VERSION 5.8 ;
BUSBITCHARS "[]" ;
DIVIDERCHAR "/" ;
UNITS
    DATABASE MICRONS 1000 ;
END UNITS

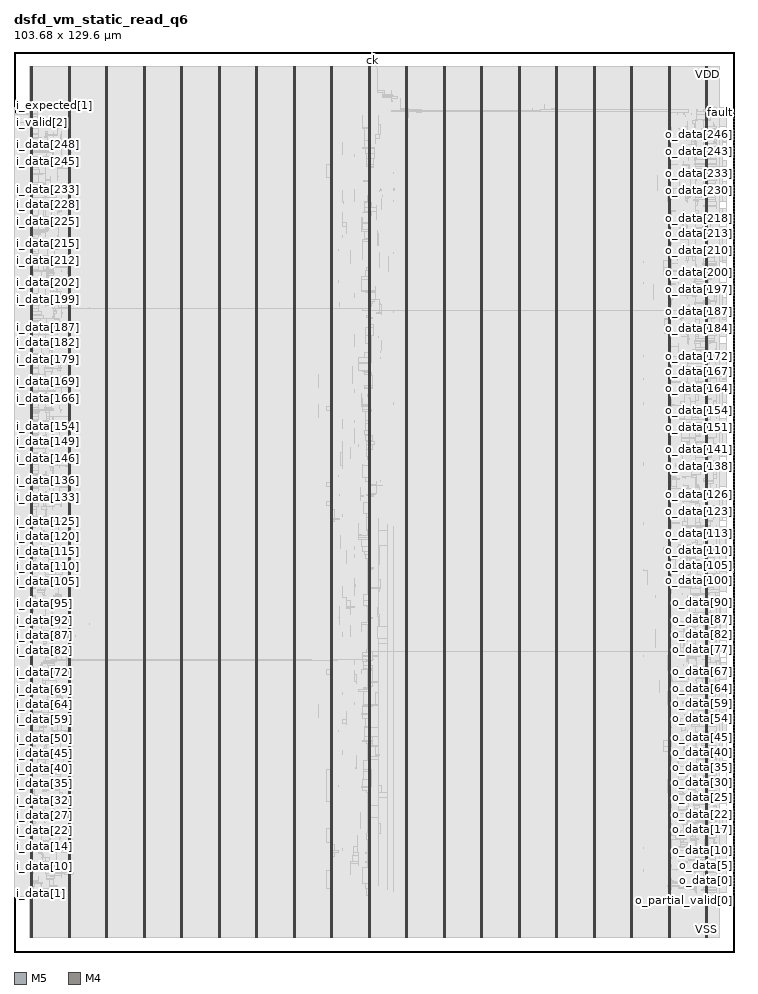
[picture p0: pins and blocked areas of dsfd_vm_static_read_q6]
MACRO dsfd_vm_static_read_q6
  FOREIGN dsfd_vm_static_read_q6 0 0 ;
  CLASS BLOCK ;
  SIZE 103.68 BY 129.6 ;
  PIN ck
    DIRECTION INPUT ;
    USE SIGNAL ;
    PORT
      LAYER M5 ;
        RECT  51.6 129.516 51.624 129.6 ;
    END
  END ck
  PIN fault
    DIRECTION OUTPUT ;
    USE SIGNAL ;
    PORT
      LAYER M4 ;
        RECT  103.596 120.912 103.68 120.936 ;
    END
  END fault
  PIN i_data[0]
    DIRECTION INPUT ;
    USE SIGNAL ;
    PORT
      LAYER M4 ;
        RECT  0 7.968 0.084 7.992 ;
    END
  END i_data[0]
  PIN i_data[100]
    DIRECTION INPUT ;
    USE SIGNAL ;
    PORT
      LAYER M4 ;
        RECT  0 51.168 0.084 51.192 ;
    END
  END i_data[100]
  PIN i_data[101]
    DIRECTION INPUT ;
    USE SIGNAL ;
    PORT
      LAYER M4 ;
        RECT  0 51.6 0.084 51.624 ;
    END
  END i_data[101]
  PIN i_data[102]
    DIRECTION INPUT ;
    USE SIGNAL ;
    PORT
      LAYER M4 ;
        RECT  0 52.032 0.084 52.056 ;
    END
  END i_data[102]
  PIN i_data[103]
    DIRECTION INPUT ;
    USE SIGNAL ;
    PORT
      LAYER M4 ;
        RECT  0 52.464 0.084 52.488 ;
    END
  END i_data[103]
  PIN i_data[104]
    DIRECTION INPUT ;
    USE SIGNAL ;
    PORT
      LAYER M4 ;
        RECT  0 52.896 0.084 52.92 ;
    END
  END i_data[104]
  PIN i_data[105]
    DIRECTION INPUT ;
    USE SIGNAL ;
    PORT
      LAYER M4 ;
        RECT  0 53.328 0.084 53.352 ;
    END
  END i_data[105]
  PIN i_data[106]
    DIRECTION INPUT ;
    USE SIGNAL ;
    PORT
      LAYER M4 ;
        RECT  0 53.76 0.084 53.784 ;
    END
  END i_data[106]
  PIN i_data[107]
    DIRECTION INPUT ;
    USE SIGNAL ;
    PORT
      LAYER M4 ;
        RECT  0 54.192 0.084 54.216 ;
    END
  END i_data[107]
  PIN i_data[108]
    DIRECTION INPUT ;
    USE SIGNAL ;
    PORT
      LAYER M4 ;
        RECT  0 54.624 0.084 54.648 ;
    END
  END i_data[108]
  PIN i_data[109]
    DIRECTION INPUT ;
    USE SIGNAL ;
    PORT
      LAYER M4 ;
        RECT  0 55.056 0.084 55.08 ;
    END
  END i_data[109]
  PIN i_data[10]
    DIRECTION INPUT ;
    USE SIGNAL ;
    PORT
      LAYER M4 ;
        RECT  0 12.288 0.084 12.312 ;
    END
  END i_data[10]
  PIN i_data[110]
    DIRECTION INPUT ;
    USE SIGNAL ;
    PORT
      LAYER M4 ;
        RECT  0 55.488 0.084 55.512 ;
    END
  END i_data[110]
  PIN i_data[111]
    DIRECTION INPUT ;
    USE SIGNAL ;
    PORT
      LAYER M4 ;
        RECT  0 55.92 0.084 55.944 ;
    END
  END i_data[111]
  PIN i_data[112]
    DIRECTION INPUT ;
    USE SIGNAL ;
    PORT
      LAYER M4 ;
        RECT  0 56.352 0.084 56.376 ;
    END
  END i_data[112]
  PIN i_data[113]
    DIRECTION INPUT ;
    USE SIGNAL ;
    PORT
      LAYER M4 ;
        RECT  0 56.784 0.084 56.808 ;
    END
  END i_data[113]
  PIN i_data[114]
    DIRECTION INPUT ;
    USE SIGNAL ;
    PORT
      LAYER M4 ;
        RECT  0 57.216 0.084 57.24 ;
    END
  END i_data[114]
  PIN i_data[115]
    DIRECTION INPUT ;
    USE SIGNAL ;
    PORT
      LAYER M4 ;
        RECT  0 57.648 0.084 57.672 ;
    END
  END i_data[115]
  PIN i_data[116]
    DIRECTION INPUT ;
    USE SIGNAL ;
    PORT
      LAYER M4 ;
        RECT  0 58.08 0.084 58.104 ;
    END
  END i_data[116]
  PIN i_data[117]
    DIRECTION INPUT ;
    USE SIGNAL ;
    PORT
      LAYER M4 ;
        RECT  0 58.512 0.084 58.536 ;
    END
  END i_data[117]
  PIN i_data[118]
    DIRECTION INPUT ;
    USE SIGNAL ;
    PORT
      LAYER M4 ;
        RECT  0 58.944 0.084 58.968 ;
    END
  END i_data[118]
  PIN i_data[119]
    DIRECTION INPUT ;
    USE SIGNAL ;
    PORT
      LAYER M4 ;
        RECT  0 59.376 0.084 59.4 ;
    END
  END i_data[119]
  PIN i_data[11]
    DIRECTION INPUT ;
    USE SIGNAL ;
    PORT
      LAYER M4 ;
        RECT  0 12.72 0.084 12.744 ;
    END
  END i_data[11]
  PIN i_data[120]
    DIRECTION INPUT ;
    USE SIGNAL ;
    PORT
      LAYER M4 ;
        RECT  0 59.808 0.084 59.832 ;
    END
  END i_data[120]
  PIN i_data[121]
    DIRECTION INPUT ;
    USE SIGNAL ;
    PORT
      LAYER M4 ;
        RECT  0 60.24 0.084 60.264 ;
    END
  END i_data[121]
  PIN i_data[122]
    DIRECTION INPUT ;
    USE SIGNAL ;
    PORT
      LAYER M4 ;
        RECT  0 60.672 0.084 60.696 ;
    END
  END i_data[122]
  PIN i_data[123]
    DIRECTION INPUT ;
    USE SIGNAL ;
    PORT
      LAYER M4 ;
        RECT  0 61.104 0.084 61.128 ;
    END
  END i_data[123]
  PIN i_data[124]
    DIRECTION INPUT ;
    USE SIGNAL ;
    PORT
      LAYER M4 ;
        RECT  0 61.536 0.084 61.56 ;
    END
  END i_data[124]
  PIN i_data[125]
    DIRECTION INPUT ;
    USE SIGNAL ;
    PORT
      LAYER M4 ;
        RECT  0 61.968 0.084 61.992 ;
    END
  END i_data[125]
  PIN i_data[126]
    DIRECTION INPUT ;
    USE SIGNAL ;
    PORT
      LAYER M4 ;
        RECT  0 62.4 0.084 62.424 ;
    END
  END i_data[126]
  PIN i_data[127]
    DIRECTION INPUT ;
    USE SIGNAL ;
    PORT
      LAYER M4 ;
        RECT  0 62.832 0.084 62.856 ;
    END
  END i_data[127]
  PIN i_data[128]
    DIRECTION INPUT ;
    USE SIGNAL ;
    PORT
      LAYER M4 ;
        RECT  0 63.264 0.084 63.288 ;
    END
  END i_data[128]
  PIN i_data[129]
    DIRECTION INPUT ;
    USE SIGNAL ;
    PORT
      LAYER M4 ;
        RECT  0 63.696 0.084 63.72 ;
    END
  END i_data[129]
  PIN i_data[12]
    DIRECTION INPUT ;
    USE SIGNAL ;
    PORT
      LAYER M4 ;
        RECT  0 13.152 0.084 13.176 ;
    END
  END i_data[12]
  PIN i_data[130]
    DIRECTION INPUT ;
    USE SIGNAL ;
    PORT
      LAYER M4 ;
        RECT  0 64.128 0.084 64.152 ;
    END
  END i_data[130]
  PIN i_data[131]
    DIRECTION INPUT ;
    USE SIGNAL ;
    PORT
      LAYER M4 ;
        RECT  0 64.56 0.084 64.584 ;
    END
  END i_data[131]
  PIN i_data[132]
    DIRECTION INPUT ;
    USE SIGNAL ;
    PORT
      LAYER M4 ;
        RECT  0 64.992 0.084 65.016 ;
    END
  END i_data[132]
  PIN i_data[133]
    DIRECTION INPUT ;
    USE SIGNAL ;
    PORT
      LAYER M4 ;
        RECT  0 65.424 0.084 65.448 ;
    END
  END i_data[133]
  PIN i_data[134]
    DIRECTION INPUT ;
    USE SIGNAL ;
    PORT
      LAYER M4 ;
        RECT  0 65.856 0.084 65.88 ;
    END
  END i_data[134]
  PIN i_data[135]
    DIRECTION INPUT ;
    USE SIGNAL ;
    PORT
      LAYER M4 ;
        RECT  0 66.288 0.084 66.312 ;
    END
  END i_data[135]
  PIN i_data[136]
    DIRECTION INPUT ;
    USE SIGNAL ;
    PORT
      LAYER M4 ;
        RECT  0 66.72 0.084 66.744 ;
    END
  END i_data[136]
  PIN i_data[137]
    DIRECTION INPUT ;
    USE SIGNAL ;
    PORT
      LAYER M4 ;
        RECT  0 67.152 0.084 67.176 ;
    END
  END i_data[137]
  PIN i_data[138]
    DIRECTION INPUT ;
    USE SIGNAL ;
    PORT
      LAYER M4 ;
        RECT  0 67.584 0.084 67.608 ;
    END
  END i_data[138]
  PIN i_data[139]
    DIRECTION INPUT ;
    USE SIGNAL ;
    PORT
      LAYER M4 ;
        RECT  0 68.016 0.084 68.04 ;
    END
  END i_data[139]
  PIN i_data[13]
    DIRECTION INPUT ;
    USE SIGNAL ;
    PORT
      LAYER M4 ;
        RECT  0 13.584 0.084 13.608 ;
    END
  END i_data[13]
  PIN i_data[140]
    DIRECTION INPUT ;
    USE SIGNAL ;
    PORT
      LAYER M4 ;
        RECT  0 68.448 0.084 68.472 ;
    END
  END i_data[140]
  PIN i_data[141]
    DIRECTION INPUT ;
    USE SIGNAL ;
    PORT
      LAYER M4 ;
        RECT  0 68.88 0.084 68.904 ;
    END
  END i_data[141]
  PIN i_data[142]
    DIRECTION INPUT ;
    USE SIGNAL ;
    PORT
      LAYER M4 ;
        RECT  0 69.312 0.084 69.336 ;
    END
  END i_data[142]
  PIN i_data[143]
    DIRECTION INPUT ;
    USE SIGNAL ;
    PORT
      LAYER M4 ;
        RECT  0 69.744 0.084 69.768 ;
    END
  END i_data[143]
  PIN i_data[144]
    DIRECTION INPUT ;
    USE SIGNAL ;
    PORT
      LAYER M4 ;
        RECT  0 70.176 0.084 70.2 ;
    END
  END i_data[144]
  PIN i_data[145]
    DIRECTION INPUT ;
    USE SIGNAL ;
    PORT
      LAYER M4 ;
        RECT  0 70.608 0.084 70.632 ;
    END
  END i_data[145]
  PIN i_data[146]
    DIRECTION INPUT ;
    USE SIGNAL ;
    PORT
      LAYER M4 ;
        RECT  0 71.04 0.084 71.064 ;
    END
  END i_data[146]
  PIN i_data[147]
    DIRECTION INPUT ;
    USE SIGNAL ;
    PORT
      LAYER M4 ;
        RECT  0 71.472 0.084 71.496 ;
    END
  END i_data[147]
  PIN i_data[148]
    DIRECTION INPUT ;
    USE SIGNAL ;
    PORT
      LAYER M4 ;
        RECT  0 71.904 0.084 71.928 ;
    END
  END i_data[148]
  PIN i_data[149]
    DIRECTION INPUT ;
    USE SIGNAL ;
    PORT
      LAYER M4 ;
        RECT  0 72.336 0.084 72.36 ;
    END
  END i_data[149]
  PIN i_data[14]
    DIRECTION INPUT ;
    USE SIGNAL ;
    PORT
      LAYER M4 ;
        RECT  0 14.016 0.084 14.04 ;
    END
  END i_data[14]
  PIN i_data[150]
    DIRECTION INPUT ;
    USE SIGNAL ;
    PORT
      LAYER M4 ;
        RECT  0 72.768 0.084 72.792 ;
    END
  END i_data[150]
  PIN i_data[151]
    DIRECTION INPUT ;
    USE SIGNAL ;
    PORT
      LAYER M4 ;
        RECT  0 73.2 0.084 73.224 ;
    END
  END i_data[151]
  PIN i_data[152]
    DIRECTION INPUT ;
    USE SIGNAL ;
    PORT
      LAYER M4 ;
        RECT  0 73.632 0.084 73.656 ;
    END
  END i_data[152]
  PIN i_data[153]
    DIRECTION INPUT ;
    USE SIGNAL ;
    PORT
      LAYER M4 ;
        RECT  0 74.064 0.084 74.088 ;
    END
  END i_data[153]
  PIN i_data[154]
    DIRECTION INPUT ;
    USE SIGNAL ;
    PORT
      LAYER M4 ;
        RECT  0 74.496 0.084 74.52 ;
    END
  END i_data[154]
  PIN i_data[155]
    DIRECTION INPUT ;
    USE SIGNAL ;
    PORT
      LAYER M4 ;
        RECT  0 74.928 0.084 74.952 ;
    END
  END i_data[155]
  PIN i_data[156]
    DIRECTION INPUT ;
    USE SIGNAL ;
    PORT
      LAYER M4 ;
        RECT  0 75.36 0.084 75.384 ;
    END
  END i_data[156]
  PIN i_data[157]
    DIRECTION INPUT ;
    USE SIGNAL ;
    PORT
      LAYER M4 ;
        RECT  0 75.792 0.084 75.816 ;
    END
  END i_data[157]
  PIN i_data[158]
    DIRECTION INPUT ;
    USE SIGNAL ;
    PORT
      LAYER M4 ;
        RECT  0 76.224 0.084 76.248 ;
    END
  END i_data[158]
  PIN i_data[159]
    DIRECTION INPUT ;
    USE SIGNAL ;
    PORT
      LAYER M4 ;
        RECT  0 76.656 0.084 76.68 ;
    END
  END i_data[159]
  PIN i_data[15]
    DIRECTION INPUT ;
    USE SIGNAL ;
    PORT
      LAYER M4 ;
        RECT  0 14.448 0.084 14.472 ;
    END
  END i_data[15]
  PIN i_data[160]
    DIRECTION INPUT ;
    USE SIGNAL ;
    PORT
      LAYER M4 ;
        RECT  0 77.088 0.084 77.112 ;
    END
  END i_data[160]
  PIN i_data[161]
    DIRECTION INPUT ;
    USE SIGNAL ;
    PORT
      LAYER M4 ;
        RECT  0 77.52 0.084 77.544 ;
    END
  END i_data[161]
  PIN i_data[162]
    DIRECTION INPUT ;
    USE SIGNAL ;
    PORT
      LAYER M4 ;
        RECT  0 77.952 0.084 77.976 ;
    END
  END i_data[162]
  PIN i_data[163]
    DIRECTION INPUT ;
    USE SIGNAL ;
    PORT
      LAYER M4 ;
        RECT  0 78.384 0.084 78.408 ;
    END
  END i_data[163]
  PIN i_data[164]
    DIRECTION INPUT ;
    USE SIGNAL ;
    PORT
      LAYER M4 ;
        RECT  0 78.816 0.084 78.84 ;
    END
  END i_data[164]
  PIN i_data[165]
    DIRECTION INPUT ;
    USE SIGNAL ;
    PORT
      LAYER M4 ;
        RECT  0 79.248 0.084 79.272 ;
    END
  END i_data[165]
  PIN i_data[166]
    DIRECTION INPUT ;
    USE SIGNAL ;
    PORT
      LAYER M4 ;
        RECT  0 79.68 0.084 79.704 ;
    END
  END i_data[166]
  PIN i_data[167]
    DIRECTION INPUT ;
    USE SIGNAL ;
    PORT
      LAYER M4 ;
        RECT  0 80.112 0.084 80.136 ;
    END
  END i_data[167]
  PIN i_data[168]
    DIRECTION INPUT ;
    USE SIGNAL ;
    PORT
      LAYER M4 ;
        RECT  0 80.544 0.084 80.568 ;
    END
  END i_data[168]
  PIN i_data[169]
    DIRECTION INPUT ;
    USE SIGNAL ;
    PORT
      LAYER M4 ;
        RECT  0 80.976 0.084 81 ;
    END
  END i_data[169]
  PIN i_data[16]
    DIRECTION INPUT ;
    USE SIGNAL ;
    PORT
      LAYER M4 ;
        RECT  0 14.88 0.084 14.904 ;
    END
  END i_data[16]
  PIN i_data[170]
    DIRECTION INPUT ;
    USE SIGNAL ;
    PORT
      LAYER M4 ;
        RECT  0 81.408 0.084 81.432 ;
    END
  END i_data[170]
  PIN i_data[171]
    DIRECTION INPUT ;
    USE SIGNAL ;
    PORT
      LAYER M4 ;
        RECT  0 81.84 0.084 81.864 ;
    END
  END i_data[171]
  PIN i_data[172]
    DIRECTION INPUT ;
    USE SIGNAL ;
    PORT
      LAYER M4 ;
        RECT  0 82.272 0.084 82.296 ;
    END
  END i_data[172]
  PIN i_data[173]
    DIRECTION INPUT ;
    USE SIGNAL ;
    PORT
      LAYER M4 ;
        RECT  0 82.704 0.084 82.728 ;
    END
  END i_data[173]
  PIN i_data[174]
    DIRECTION INPUT ;
    USE SIGNAL ;
    PORT
      LAYER M4 ;
        RECT  0 83.136 0.084 83.16 ;
    END
  END i_data[174]
  PIN i_data[175]
    DIRECTION INPUT ;
    USE SIGNAL ;
    PORT
      LAYER M4 ;
        RECT  0 83.568 0.084 83.592 ;
    END
  END i_data[175]
  PIN i_data[176]
    DIRECTION INPUT ;
    USE SIGNAL ;
    PORT
      LAYER M4 ;
        RECT  0 84 0.084 84.024 ;
    END
  END i_data[176]
  PIN i_data[177]
    DIRECTION INPUT ;
    USE SIGNAL ;
    PORT
      LAYER M4 ;
        RECT  0 84.432 0.084 84.456 ;
    END
  END i_data[177]
  PIN i_data[178]
    DIRECTION INPUT ;
    USE SIGNAL ;
    PORT
      LAYER M4 ;
        RECT  0 84.864 0.084 84.888 ;
    END
  END i_data[178]
  PIN i_data[179]
    DIRECTION INPUT ;
    USE SIGNAL ;
    PORT
      LAYER M4 ;
        RECT  0 85.296 0.084 85.32 ;
    END
  END i_data[179]
  PIN i_data[17]
    DIRECTION INPUT ;
    USE SIGNAL ;
    PORT
      LAYER M4 ;
        RECT  0 15.312 0.084 15.336 ;
    END
  END i_data[17]
  PIN i_data[180]
    DIRECTION INPUT ;
    USE SIGNAL ;
    PORT
      LAYER M4 ;
        RECT  0 85.728 0.084 85.752 ;
    END
  END i_data[180]
  PIN i_data[181]
    DIRECTION INPUT ;
    USE SIGNAL ;
    PORT
      LAYER M4 ;
        RECT  0 86.16 0.084 86.184 ;
    END
  END i_data[181]
  PIN i_data[182]
    DIRECTION INPUT ;
    USE SIGNAL ;
    PORT
      LAYER M4 ;
        RECT  0 86.592 0.084 86.616 ;
    END
  END i_data[182]
  PIN i_data[183]
    DIRECTION INPUT ;
    USE SIGNAL ;
    PORT
      LAYER M4 ;
        RECT  0 87.024 0.084 87.048 ;
    END
  END i_data[183]
  PIN i_data[184]
    DIRECTION INPUT ;
    USE SIGNAL ;
    PORT
      LAYER M4 ;
        RECT  0 87.456 0.084 87.48 ;
    END
  END i_data[184]
  PIN i_data[185]
    DIRECTION INPUT ;
    USE SIGNAL ;
    PORT
      LAYER M4 ;
        RECT  0 87.888 0.084 87.912 ;
    END
  END i_data[185]
  PIN i_data[186]
    DIRECTION INPUT ;
    USE SIGNAL ;
    PORT
      LAYER M4 ;
        RECT  0 88.32 0.084 88.344 ;
    END
  END i_data[186]
  PIN i_data[187]
    DIRECTION INPUT ;
    USE SIGNAL ;
    PORT
      LAYER M4 ;
        RECT  0 88.752 0.084 88.776 ;
    END
  END i_data[187]
  PIN i_data[188]
    DIRECTION INPUT ;
    USE SIGNAL ;
    PORT
      LAYER M4 ;
        RECT  0 89.184 0.084 89.208 ;
    END
  END i_data[188]
  PIN i_data[189]
    DIRECTION INPUT ;
    USE SIGNAL ;
    PORT
      LAYER M4 ;
        RECT  0 89.616 0.084 89.64 ;
    END
  END i_data[189]
  PIN i_data[18]
    DIRECTION INPUT ;
    USE SIGNAL ;
    PORT
      LAYER M4 ;
        RECT  0 15.744 0.084 15.768 ;
    END
  END i_data[18]
  PIN i_data[190]
    DIRECTION INPUT ;
    USE SIGNAL ;
    PORT
      LAYER M4 ;
        RECT  0 90.048 0.084 90.072 ;
    END
  END i_data[190]
  PIN i_data[191]
    DIRECTION INPUT ;
    USE SIGNAL ;
    PORT
      LAYER M4 ;
        RECT  0 90.48 0.084 90.504 ;
    END
  END i_data[191]
  PIN i_data[192]
    DIRECTION INPUT ;
    USE SIGNAL ;
    PORT
      LAYER M4 ;
        RECT  0 90.912 0.084 90.936 ;
    END
  END i_data[192]
  PIN i_data[193]
    DIRECTION INPUT ;
    USE SIGNAL ;
    PORT
      LAYER M4 ;
        RECT  0 91.344 0.084 91.368 ;
    END
  END i_data[193]
  PIN i_data[194]
    DIRECTION INPUT ;
    USE SIGNAL ;
    PORT
      LAYER M4 ;
        RECT  0 91.776 0.084 91.8 ;
    END
  END i_data[194]
  PIN i_data[195]
    DIRECTION INPUT ;
    USE SIGNAL ;
    PORT
      LAYER M4 ;
        RECT  0 92.208 0.084 92.232 ;
    END
  END i_data[195]
  PIN i_data[196]
    DIRECTION INPUT ;
    USE SIGNAL ;
    PORT
      LAYER M4 ;
        RECT  0 92.64 0.084 92.664 ;
    END
  END i_data[196]
  PIN i_data[197]
    DIRECTION INPUT ;
    USE SIGNAL ;
    PORT
      LAYER M4 ;
        RECT  0 93.072 0.084 93.096 ;
    END
  END i_data[197]
  PIN i_data[198]
    DIRECTION INPUT ;
    USE SIGNAL ;
    PORT
      LAYER M4 ;
        RECT  0 93.504 0.084 93.528 ;
    END
  END i_data[198]
  PIN i_data[199]
    DIRECTION INPUT ;
    USE SIGNAL ;
    PORT
      LAYER M4 ;
        RECT  0 93.936 0.084 93.96 ;
    END
  END i_data[199]
  PIN i_data[19]
    DIRECTION INPUT ;
    USE SIGNAL ;
    PORT
      LAYER M4 ;
        RECT  0 16.176 0.084 16.2 ;
    END
  END i_data[19]
  PIN i_data[1]
    DIRECTION INPUT ;
    USE SIGNAL ;
    PORT
      LAYER M4 ;
        RECT  0 8.4 0.084 8.424 ;
    END
  END i_data[1]
  PIN i_data[200]
    DIRECTION INPUT ;
    USE SIGNAL ;
    PORT
      LAYER M4 ;
        RECT  0 94.368 0.084 94.392 ;
    END
  END i_data[200]
  PIN i_data[201]
    DIRECTION INPUT ;
    USE SIGNAL ;
    PORT
      LAYER M4 ;
        RECT  0 94.8 0.084 94.824 ;
    END
  END i_data[201]
  PIN i_data[202]
    DIRECTION INPUT ;
    USE SIGNAL ;
    PORT
      LAYER M4 ;
        RECT  0 95.232 0.084 95.256 ;
    END
  END i_data[202]
  PIN i_data[203]
    DIRECTION INPUT ;
    USE SIGNAL ;
    PORT
      LAYER M4 ;
        RECT  0 95.664 0.084 95.688 ;
    END
  END i_data[203]
  PIN i_data[204]
    DIRECTION INPUT ;
    USE SIGNAL ;
    PORT
      LAYER M4 ;
        RECT  0 96.096 0.084 96.12 ;
    END
  END i_data[204]
  PIN i_data[205]
    DIRECTION INPUT ;
    USE SIGNAL ;
    PORT
      LAYER M4 ;
        RECT  0 96.528 0.084 96.552 ;
    END
  END i_data[205]
  PIN i_data[206]
    DIRECTION INPUT ;
    USE SIGNAL ;
    PORT
      LAYER M4 ;
        RECT  0 96.96 0.084 96.984 ;
    END
  END i_data[206]
  PIN i_data[207]
    DIRECTION INPUT ;
    USE SIGNAL ;
    PORT
      LAYER M4 ;
        RECT  0 97.392 0.084 97.416 ;
    END
  END i_data[207]
  PIN i_data[208]
    DIRECTION INPUT ;
    USE SIGNAL ;
    PORT
      LAYER M4 ;
        RECT  0 97.824 0.084 97.848 ;
    END
  END i_data[208]
  PIN i_data[209]
    DIRECTION INPUT ;
    USE SIGNAL ;
    PORT
      LAYER M4 ;
        RECT  0 98.256 0.084 98.28 ;
    END
  END i_data[209]
  PIN i_data[20]
    DIRECTION INPUT ;
    USE SIGNAL ;
    PORT
      LAYER M4 ;
        RECT  0 16.608 0.084 16.632 ;
    END
  END i_data[20]
  PIN i_data[210]
    DIRECTION INPUT ;
    USE SIGNAL ;
    PORT
      LAYER M4 ;
        RECT  0 98.688 0.084 98.712 ;
    END
  END i_data[210]
  PIN i_data[211]
    DIRECTION INPUT ;
    USE SIGNAL ;
    PORT
      LAYER M4 ;
        RECT  0 99.12 0.084 99.144 ;
    END
  END i_data[211]
  PIN i_data[212]
    DIRECTION INPUT ;
    USE SIGNAL ;
    PORT
      LAYER M4 ;
        RECT  0 99.552 0.084 99.576 ;
    END
  END i_data[212]
  PIN i_data[213]
    DIRECTION INPUT ;
    USE SIGNAL ;
    PORT
      LAYER M4 ;
        RECT  0 99.984 0.084 100.008 ;
    END
  END i_data[213]
  PIN i_data[214]
    DIRECTION INPUT ;
    USE SIGNAL ;
    PORT
      LAYER M4 ;
        RECT  0 100.416 0.084 100.44 ;
    END
  END i_data[214]
  PIN i_data[215]
    DIRECTION INPUT ;
    USE SIGNAL ;
    PORT
      LAYER M4 ;
        RECT  0 100.848 0.084 100.872 ;
    END
  END i_data[215]
  PIN i_data[216]
    DIRECTION INPUT ;
    USE SIGNAL ;
    PORT
      LAYER M4 ;
        RECT  0 101.28 0.084 101.304 ;
    END
  END i_data[216]
  PIN i_data[217]
    DIRECTION INPUT ;
    USE SIGNAL ;
    PORT
      LAYER M4 ;
        RECT  0 101.712 0.084 101.736 ;
    END
  END i_data[217]
  PIN i_data[218]
    DIRECTION INPUT ;
    USE SIGNAL ;
    PORT
      LAYER M4 ;
        RECT  0 102.144 0.084 102.168 ;
    END
  END i_data[218]
  PIN i_data[219]
    DIRECTION INPUT ;
    USE SIGNAL ;
    PORT
      LAYER M4 ;
        RECT  0 102.576 0.084 102.6 ;
    END
  END i_data[219]
  PIN i_data[21]
    DIRECTION INPUT ;
    USE SIGNAL ;
    PORT
      LAYER M4 ;
        RECT  0 17.04 0.084 17.064 ;
    END
  END i_data[21]
  PIN i_data[220]
    DIRECTION INPUT ;
    USE SIGNAL ;
    PORT
      LAYER M4 ;
        RECT  0 103.008 0.084 103.032 ;
    END
  END i_data[220]
  PIN i_data[221]
    DIRECTION INPUT ;
    USE SIGNAL ;
    PORT
      LAYER M4 ;
        RECT  0 103.44 0.084 103.464 ;
    END
  END i_data[221]
  PIN i_data[222]
    DIRECTION INPUT ;
    USE SIGNAL ;
    PORT
      LAYER M4 ;
        RECT  0 103.872 0.084 103.896 ;
    END
  END i_data[222]
  PIN i_data[223]
    DIRECTION INPUT ;
    USE SIGNAL ;
    PORT
      LAYER M4 ;
        RECT  0 104.304 0.084 104.328 ;
    END
  END i_data[223]
  PIN i_data[224]
    DIRECTION INPUT ;
    USE SIGNAL ;
    PORT
      LAYER M4 ;
        RECT  0 104.736 0.084 104.76 ;
    END
  END i_data[224]
  PIN i_data[225]
    DIRECTION INPUT ;
    USE SIGNAL ;
    PORT
      LAYER M4 ;
        RECT  0 105.168 0.084 105.192 ;
    END
  END i_data[225]
  PIN i_data[226]
    DIRECTION INPUT ;
    USE SIGNAL ;
    PORT
      LAYER M4 ;
        RECT  0 105.6 0.084 105.624 ;
    END
  END i_data[226]
  PIN i_data[227]
    DIRECTION INPUT ;
    USE SIGNAL ;
    PORT
      LAYER M4 ;
        RECT  0 106.032 0.084 106.056 ;
    END
  END i_data[227]
  PIN i_data[228]
    DIRECTION INPUT ;
    USE SIGNAL ;
    PORT
      LAYER M4 ;
        RECT  0 106.464 0.084 106.488 ;
    END
  END i_data[228]
  PIN i_data[229]
    DIRECTION INPUT ;
    USE SIGNAL ;
    PORT
      LAYER M4 ;
        RECT  0 106.896 0.084 106.92 ;
    END
  END i_data[229]
  PIN i_data[22]
    DIRECTION INPUT ;
    USE SIGNAL ;
    PORT
      LAYER M4 ;
        RECT  0 17.472 0.084 17.496 ;
    END
  END i_data[22]
  PIN i_data[230]
    DIRECTION INPUT ;
    USE SIGNAL ;
    PORT
      LAYER M4 ;
        RECT  0 107.328 0.084 107.352 ;
    END
  END i_data[230]
  PIN i_data[231]
    DIRECTION INPUT ;
    USE SIGNAL ;
    PORT
      LAYER M4 ;
        RECT  0 107.76 0.084 107.784 ;
    END
  END i_data[231]
  PIN i_data[232]
    DIRECTION INPUT ;
    USE SIGNAL ;
    PORT
      LAYER M4 ;
        RECT  0 108.192 0.084 108.216 ;
    END
  END i_data[232]
  PIN i_data[233]
    DIRECTION INPUT ;
    USE SIGNAL ;
    PORT
      LAYER M4 ;
        RECT  0 108.624 0.084 108.648 ;
    END
  END i_data[233]
  PIN i_data[234]
    DIRECTION INPUT ;
    USE SIGNAL ;
    PORT
      LAYER M4 ;
        RECT  0 109.056 0.084 109.08 ;
    END
  END i_data[234]
  PIN i_data[235]
    DIRECTION INPUT ;
    USE SIGNAL ;
    PORT
      LAYER M4 ;
        RECT  0 109.488 0.084 109.512 ;
    END
  END i_data[235]
  PIN i_data[236]
    DIRECTION INPUT ;
    USE SIGNAL ;
    PORT
      LAYER M4 ;
        RECT  0 109.92 0.084 109.944 ;
    END
  END i_data[236]
  PIN i_data[237]
    DIRECTION INPUT ;
    USE SIGNAL ;
    PORT
      LAYER M4 ;
        RECT  0 110.352 0.084 110.376 ;
    END
  END i_data[237]
  PIN i_data[238]
    DIRECTION INPUT ;
    USE SIGNAL ;
    PORT
      LAYER M4 ;
        RECT  0 110.784 0.084 110.808 ;
    END
  END i_data[238]
  PIN i_data[239]
    DIRECTION INPUT ;
    USE SIGNAL ;
    PORT
      LAYER M4 ;
        RECT  0 111.216 0.084 111.24 ;
    END
  END i_data[239]
  PIN i_data[23]
    DIRECTION INPUT ;
    USE SIGNAL ;
    PORT
      LAYER M4 ;
        RECT  0 17.904 0.084 17.928 ;
    END
  END i_data[23]
  PIN i_data[240]
    DIRECTION INPUT ;
    USE SIGNAL ;
    PORT
      LAYER M4 ;
        RECT  0 111.648 0.084 111.672 ;
    END
  END i_data[240]
  PIN i_data[241]
    DIRECTION INPUT ;
    USE SIGNAL ;
    PORT
      LAYER M4 ;
        RECT  0 112.08 0.084 112.104 ;
    END
  END i_data[241]
  PIN i_data[242]
    DIRECTION INPUT ;
    USE SIGNAL ;
    PORT
      LAYER M4 ;
        RECT  0 112.512 0.084 112.536 ;
    END
  END i_data[242]
  PIN i_data[243]
    DIRECTION INPUT ;
    USE SIGNAL ;
    PORT
      LAYER M4 ;
        RECT  0 112.944 0.084 112.968 ;
    END
  END i_data[243]
  PIN i_data[244]
    DIRECTION INPUT ;
    USE SIGNAL ;
    PORT
      LAYER M4 ;
        RECT  0 113.376 0.084 113.4 ;
    END
  END i_data[244]
  PIN i_data[245]
    DIRECTION INPUT ;
    USE SIGNAL ;
    PORT
      LAYER M4 ;
        RECT  0 113.808 0.084 113.832 ;
    END
  END i_data[245]
  PIN i_data[246]
    DIRECTION INPUT ;
    USE SIGNAL ;
    PORT
      LAYER M4 ;
        RECT  0 114.24 0.084 114.264 ;
    END
  END i_data[246]
  PIN i_data[247]
    DIRECTION INPUT ;
    USE SIGNAL ;
    PORT
      LAYER M4 ;
        RECT  0 114.672 0.084 114.696 ;
    END
  END i_data[247]
  PIN i_data[248]
    DIRECTION INPUT ;
    USE SIGNAL ;
    PORT
      LAYER M4 ;
        RECT  0 115.104 0.084 115.128 ;
    END
  END i_data[248]
  PIN i_data[249]
    DIRECTION INPUT ;
    USE SIGNAL ;
    PORT
      LAYER M4 ;
        RECT  0 115.536 0.084 115.56 ;
    END
  END i_data[249]
  PIN i_data[24]
    DIRECTION INPUT ;
    USE SIGNAL ;
    PORT
      LAYER M4 ;
        RECT  0 18.336 0.084 18.36 ;
    END
  END i_data[24]
  PIN i_data[250]
    DIRECTION INPUT ;
    USE SIGNAL ;
    PORT
      LAYER M4 ;
        RECT  0 115.968 0.084 115.992 ;
    END
  END i_data[250]
  PIN i_data[251]
    DIRECTION INPUT ;
    USE SIGNAL ;
    PORT
      LAYER M4 ;
        RECT  0 116.4 0.084 116.424 ;
    END
  END i_data[251]
  PIN i_data[252]
    DIRECTION INPUT ;
    USE SIGNAL ;
    PORT
      LAYER M4 ;
        RECT  0 116.832 0.084 116.856 ;
    END
  END i_data[252]
  PIN i_data[253]
    DIRECTION INPUT ;
    USE SIGNAL ;
    PORT
      LAYER M4 ;
        RECT  0 117.264 0.084 117.288 ;
    END
  END i_data[253]
  PIN i_data[254]
    DIRECTION INPUT ;
    USE SIGNAL ;
    PORT
      LAYER M4 ;
        RECT  0 117.696 0.084 117.72 ;
    END
  END i_data[254]
  PIN i_data[255]
    DIRECTION INPUT ;
    USE SIGNAL ;
    PORT
      LAYER M4 ;
        RECT  0 118.128 0.084 118.152 ;
    END
  END i_data[255]
  PIN i_data[25]
    DIRECTION INPUT ;
    USE SIGNAL ;
    PORT
      LAYER M4 ;
        RECT  0 18.768 0.084 18.792 ;
    END
  END i_data[25]
  PIN i_data[26]
    DIRECTION INPUT ;
    USE SIGNAL ;
    PORT
      LAYER M4 ;
        RECT  0 19.2 0.084 19.224 ;
    END
  END i_data[26]
  PIN i_data[27]
    DIRECTION INPUT ;
    USE SIGNAL ;
    PORT
      LAYER M4 ;
        RECT  0 19.632 0.084 19.656 ;
    END
  END i_data[27]
  PIN i_data[28]
    DIRECTION INPUT ;
    USE SIGNAL ;
    PORT
      LAYER M4 ;
        RECT  0 20.064 0.084 20.088 ;
    END
  END i_data[28]
  PIN i_data[29]
    DIRECTION INPUT ;
    USE SIGNAL ;
    PORT
      LAYER M4 ;
        RECT  0 20.496 0.084 20.52 ;
    END
  END i_data[29]
  PIN i_data[2]
    DIRECTION INPUT ;
    USE SIGNAL ;
    PORT
      LAYER M4 ;
        RECT  0 8.832 0.084 8.856 ;
    END
  END i_data[2]
  PIN i_data[30]
    DIRECTION INPUT ;
    USE SIGNAL ;
    PORT
      LAYER M4 ;
        RECT  0 20.928 0.084 20.952 ;
    END
  END i_data[30]
  PIN i_data[31]
    DIRECTION INPUT ;
    USE SIGNAL ;
    PORT
      LAYER M4 ;
        RECT  0 21.36 0.084 21.384 ;
    END
  END i_data[31]
  PIN i_data[32]
    DIRECTION INPUT ;
    USE SIGNAL ;
    PORT
      LAYER M4 ;
        RECT  0 21.792 0.084 21.816 ;
    END
  END i_data[32]
  PIN i_data[33]
    DIRECTION INPUT ;
    USE SIGNAL ;
    PORT
      LAYER M4 ;
        RECT  0 22.224 0.084 22.248 ;
    END
  END i_data[33]
  PIN i_data[34]
    DIRECTION INPUT ;
    USE SIGNAL ;
    PORT
      LAYER M4 ;
        RECT  0 22.656 0.084 22.68 ;
    END
  END i_data[34]
  PIN i_data[35]
    DIRECTION INPUT ;
    USE SIGNAL ;
    PORT
      LAYER M4 ;
        RECT  0 23.088 0.084 23.112 ;
    END
  END i_data[35]
  PIN i_data[36]
    DIRECTION INPUT ;
    USE SIGNAL ;
    PORT
      LAYER M4 ;
        RECT  0 23.52 0.084 23.544 ;
    END
  END i_data[36]
  PIN i_data[37]
    DIRECTION INPUT ;
    USE SIGNAL ;
    PORT
      LAYER M4 ;
        RECT  0 23.952 0.084 23.976 ;
    END
  END i_data[37]
  PIN i_data[38]
    DIRECTION INPUT ;
    USE SIGNAL ;
    PORT
      LAYER M4 ;
        RECT  0 24.384 0.084 24.408 ;
    END
  END i_data[38]
  PIN i_data[39]
    DIRECTION INPUT ;
    USE SIGNAL ;
    PORT
      LAYER M4 ;
        RECT  0 24.816 0.084 24.84 ;
    END
  END i_data[39]
  PIN i_data[3]
    DIRECTION INPUT ;
    USE SIGNAL ;
    PORT
      LAYER M4 ;
        RECT  0 9.264 0.084 9.288 ;
    END
  END i_data[3]
  PIN i_data[40]
    DIRECTION INPUT ;
    USE SIGNAL ;
    PORT
      LAYER M4 ;
        RECT  0 25.248 0.084 25.272 ;
    END
  END i_data[40]
  PIN i_data[41]
    DIRECTION INPUT ;
    USE SIGNAL ;
    PORT
      LAYER M4 ;
        RECT  0 25.68 0.084 25.704 ;
    END
  END i_data[41]
  PIN i_data[42]
    DIRECTION INPUT ;
    USE SIGNAL ;
    PORT
      LAYER M4 ;
        RECT  0 26.112 0.084 26.136 ;
    END
  END i_data[42]
  PIN i_data[43]
    DIRECTION INPUT ;
    USE SIGNAL ;
    PORT
      LAYER M4 ;
        RECT  0 26.544 0.084 26.568 ;
    END
  END i_data[43]
  PIN i_data[44]
    DIRECTION INPUT ;
    USE SIGNAL ;
    PORT
      LAYER M4 ;
        RECT  0 26.976 0.084 27 ;
    END
  END i_data[44]
  PIN i_data[45]
    DIRECTION INPUT ;
    USE SIGNAL ;
    PORT
      LAYER M4 ;
        RECT  0 27.408 0.084 27.432 ;
    END
  END i_data[45]
  PIN i_data[46]
    DIRECTION INPUT ;
    USE SIGNAL ;
    PORT
      LAYER M4 ;
        RECT  0 27.84 0.084 27.864 ;
    END
  END i_data[46]
  PIN i_data[47]
    DIRECTION INPUT ;
    USE SIGNAL ;
    PORT
      LAYER M4 ;
        RECT  0 28.272 0.084 28.296 ;
    END
  END i_data[47]
  PIN i_data[48]
    DIRECTION INPUT ;
    USE SIGNAL ;
    PORT
      LAYER M4 ;
        RECT  0 28.704 0.084 28.728 ;
    END
  END i_data[48]
  PIN i_data[49]
    DIRECTION INPUT ;
    USE SIGNAL ;
    PORT
      LAYER M4 ;
        RECT  0 29.136 0.084 29.16 ;
    END
  END i_data[49]
  PIN i_data[4]
    DIRECTION INPUT ;
    USE SIGNAL ;
    PORT
      LAYER M4 ;
        RECT  0 9.696 0.084 9.72 ;
    END
  END i_data[4]
  PIN i_data[50]
    DIRECTION INPUT ;
    USE SIGNAL ;
    PORT
      LAYER M4 ;
        RECT  0 29.568 0.084 29.592 ;
    END
  END i_data[50]
  PIN i_data[51]
    DIRECTION INPUT ;
    USE SIGNAL ;
    PORT
      LAYER M4 ;
        RECT  0 30 0.084 30.024 ;
    END
  END i_data[51]
  PIN i_data[52]
    DIRECTION INPUT ;
    USE SIGNAL ;
    PORT
      LAYER M4 ;
        RECT  0 30.432 0.084 30.456 ;
    END
  END i_data[52]
  PIN i_data[53]
    DIRECTION INPUT ;
    USE SIGNAL ;
    PORT
      LAYER M4 ;
        RECT  0 30.864 0.084 30.888 ;
    END
  END i_data[53]
  PIN i_data[54]
    DIRECTION INPUT ;
    USE SIGNAL ;
    PORT
      LAYER M4 ;
        RECT  0 31.296 0.084 31.32 ;
    END
  END i_data[54]
  PIN i_data[55]
    DIRECTION INPUT ;
    USE SIGNAL ;
    PORT
      LAYER M4 ;
        RECT  0 31.728 0.084 31.752 ;
    END
  END i_data[55]
  PIN i_data[56]
    DIRECTION INPUT ;
    USE SIGNAL ;
    PORT
      LAYER M4 ;
        RECT  0 32.16 0.084 32.184 ;
    END
  END i_data[56]
  PIN i_data[57]
    DIRECTION INPUT ;
    USE SIGNAL ;
    PORT
      LAYER M4 ;
        RECT  0 32.592 0.084 32.616 ;
    END
  END i_data[57]
  PIN i_data[58]
    DIRECTION INPUT ;
    USE SIGNAL ;
    PORT
      LAYER M4 ;
        RECT  0 33.024 0.084 33.048 ;
    END
  END i_data[58]
  PIN i_data[59]
    DIRECTION INPUT ;
    USE SIGNAL ;
    PORT
      LAYER M4 ;
        RECT  0 33.456 0.084 33.48 ;
    END
  END i_data[59]
  PIN i_data[5]
    DIRECTION INPUT ;
    USE SIGNAL ;
    PORT
      LAYER M4 ;
        RECT  0 10.128 0.084 10.152 ;
    END
  END i_data[5]
  PIN i_data[60]
    DIRECTION INPUT ;
    USE SIGNAL ;
    PORT
      LAYER M4 ;
        RECT  0 33.888 0.084 33.912 ;
    END
  END i_data[60]
  PIN i_data[61]
    DIRECTION INPUT ;
    USE SIGNAL ;
    PORT
      LAYER M4 ;
        RECT  0 34.32 0.084 34.344 ;
    END
  END i_data[61]
  PIN i_data[62]
    DIRECTION INPUT ;
    USE SIGNAL ;
    PORT
      LAYER M4 ;
        RECT  0 34.752 0.084 34.776 ;
    END
  END i_data[62]
  PIN i_data[63]
    DIRECTION INPUT ;
    USE SIGNAL ;
    PORT
      LAYER M4 ;
        RECT  0 35.184 0.084 35.208 ;
    END
  END i_data[63]
  PIN i_data[64]
    DIRECTION INPUT ;
    USE SIGNAL ;
    PORT
      LAYER M4 ;
        RECT  0 35.616 0.084 35.64 ;
    END
  END i_data[64]
  PIN i_data[65]
    DIRECTION INPUT ;
    USE SIGNAL ;
    PORT
      LAYER M4 ;
        RECT  0 36.048 0.084 36.072 ;
    END
  END i_data[65]
  PIN i_data[66]
    DIRECTION INPUT ;
    USE SIGNAL ;
    PORT
      LAYER M4 ;
        RECT  0 36.48 0.084 36.504 ;
    END
  END i_data[66]
  PIN i_data[67]
    DIRECTION INPUT ;
    USE SIGNAL ;
    PORT
      LAYER M4 ;
        RECT  0 36.912 0.084 36.936 ;
    END
  END i_data[67]
  PIN i_data[68]
    DIRECTION INPUT ;
    USE SIGNAL ;
    PORT
      LAYER M4 ;
        RECT  0 37.344 0.084 37.368 ;
    END
  END i_data[68]
  PIN i_data[69]
    DIRECTION INPUT ;
    USE SIGNAL ;
    PORT
      LAYER M4 ;
        RECT  0 37.776 0.084 37.8 ;
    END
  END i_data[69]
  PIN i_data[6]
    DIRECTION INPUT ;
    USE SIGNAL ;
    PORT
      LAYER M4 ;
        RECT  0 10.56 0.084 10.584 ;
    END
  END i_data[6]
  PIN i_data[70]
    DIRECTION INPUT ;
    USE SIGNAL ;
    PORT
      LAYER M4 ;
        RECT  0 38.208 0.084 38.232 ;
    END
  END i_data[70]
  PIN i_data[71]
    DIRECTION INPUT ;
    USE SIGNAL ;
    PORT
      LAYER M4 ;
        RECT  0 38.64 0.084 38.664 ;
    END
  END i_data[71]
  PIN i_data[72]
    DIRECTION INPUT ;
    USE SIGNAL ;
    PORT
      LAYER M4 ;
        RECT  0 39.072 0.084 39.096 ;
    END
  END i_data[72]
  PIN i_data[73]
    DIRECTION INPUT ;
    USE SIGNAL ;
    PORT
      LAYER M4 ;
        RECT  0 39.504 0.084 39.528 ;
    END
  END i_data[73]
  PIN i_data[74]
    DIRECTION INPUT ;
    USE SIGNAL ;
    PORT
      LAYER M4 ;
        RECT  0 39.936 0.084 39.96 ;
    END
  END i_data[74]
  PIN i_data[75]
    DIRECTION INPUT ;
    USE SIGNAL ;
    PORT
      LAYER M4 ;
        RECT  0 40.368 0.084 40.392 ;
    END
  END i_data[75]
  PIN i_data[76]
    DIRECTION INPUT ;
    USE SIGNAL ;
    PORT
      LAYER M4 ;
        RECT  0 40.8 0.084 40.824 ;
    END
  END i_data[76]
  PIN i_data[77]
    DIRECTION INPUT ;
    USE SIGNAL ;
    PORT
      LAYER M4 ;
        RECT  0 41.232 0.084 41.256 ;
    END
  END i_data[77]
  PIN i_data[78]
    DIRECTION INPUT ;
    USE SIGNAL ;
    PORT
      LAYER M4 ;
        RECT  0 41.664 0.084 41.688 ;
    END
  END i_data[78]
  PIN i_data[79]
    DIRECTION INPUT ;
    USE SIGNAL ;
    PORT
      LAYER M4 ;
        RECT  0 42.096 0.084 42.12 ;
    END
  END i_data[79]
  PIN i_data[7]
    DIRECTION INPUT ;
    USE SIGNAL ;
    PORT
      LAYER M4 ;
        RECT  0 10.992 0.084 11.016 ;
    END
  END i_data[7]
  PIN i_data[80]
    DIRECTION INPUT ;
    USE SIGNAL ;
    PORT
      LAYER M4 ;
        RECT  0 42.528 0.084 42.552 ;
    END
  END i_data[80]
  PIN i_data[81]
    DIRECTION INPUT ;
    USE SIGNAL ;
    PORT
      LAYER M4 ;
        RECT  0 42.96 0.084 42.984 ;
    END
  END i_data[81]
  PIN i_data[82]
    DIRECTION INPUT ;
    USE SIGNAL ;
    PORT
      LAYER M4 ;
        RECT  0 43.392 0.084 43.416 ;
    END
  END i_data[82]
  PIN i_data[83]
    DIRECTION INPUT ;
    USE SIGNAL ;
    PORT
      LAYER M4 ;
        RECT  0 43.824 0.084 43.848 ;
    END
  END i_data[83]
  PIN i_data[84]
    DIRECTION INPUT ;
    USE SIGNAL ;
    PORT
      LAYER M4 ;
        RECT  0 44.256 0.084 44.28 ;
    END
  END i_data[84]
  PIN i_data[85]
    DIRECTION INPUT ;
    USE SIGNAL ;
    PORT
      LAYER M4 ;
        RECT  0 44.688 0.084 44.712 ;
    END
  END i_data[85]
  PIN i_data[86]
    DIRECTION INPUT ;
    USE SIGNAL ;
    PORT
      LAYER M4 ;
        RECT  0 45.12 0.084 45.144 ;
    END
  END i_data[86]
  PIN i_data[87]
    DIRECTION INPUT ;
    USE SIGNAL ;
    PORT
      LAYER M4 ;
        RECT  0 45.552 0.084 45.576 ;
    END
  END i_data[87]
  PIN i_data[88]
    DIRECTION INPUT ;
    USE SIGNAL ;
    PORT
      LAYER M4 ;
        RECT  0 45.984 0.084 46.008 ;
    END
  END i_data[88]
  PIN i_data[89]
    DIRECTION INPUT ;
    USE SIGNAL ;
    PORT
      LAYER M4 ;
        RECT  0 46.416 0.084 46.44 ;
    END
  END i_data[89]
  PIN i_data[8]
    DIRECTION INPUT ;
    USE SIGNAL ;
    PORT
      LAYER M4 ;
        RECT  0 11.424 0.084 11.448 ;
    END
  END i_data[8]
  PIN i_data[90]
    DIRECTION INPUT ;
    USE SIGNAL ;
    PORT
      LAYER M4 ;
        RECT  0 46.848 0.084 46.872 ;
    END
  END i_data[90]
  PIN i_data[91]
    DIRECTION INPUT ;
    USE SIGNAL ;
    PORT
      LAYER M4 ;
        RECT  0 47.28 0.084 47.304 ;
    END
  END i_data[91]
  PIN i_data[92]
    DIRECTION INPUT ;
    USE SIGNAL ;
    PORT
      LAYER M4 ;
        RECT  0 47.712 0.084 47.736 ;
    END
  END i_data[92]
  PIN i_data[93]
    DIRECTION INPUT ;
    USE SIGNAL ;
    PORT
      LAYER M4 ;
        RECT  0 48.144 0.084 48.168 ;
    END
  END i_data[93]
  PIN i_data[94]
    DIRECTION INPUT ;
    USE SIGNAL ;
    PORT
      LAYER M4 ;
        RECT  0 48.576 0.084 48.6 ;
    END
  END i_data[94]
  PIN i_data[95]
    DIRECTION INPUT ;
    USE SIGNAL ;
    PORT
      LAYER M4 ;
        RECT  0 49.008 0.084 49.032 ;
    END
  END i_data[95]
  PIN i_data[96]
    DIRECTION INPUT ;
    USE SIGNAL ;
    PORT
      LAYER M4 ;
        RECT  0 49.44 0.084 49.464 ;
    END
  END i_data[96]
  PIN i_data[97]
    DIRECTION INPUT ;
    USE SIGNAL ;
    PORT
      LAYER M4 ;
        RECT  0 49.872 0.084 49.896 ;
    END
  END i_data[97]
  PIN i_data[98]
    DIRECTION INPUT ;
    USE SIGNAL ;
    PORT
      LAYER M4 ;
        RECT  0 50.304 0.084 50.328 ;
    END
  END i_data[98]
  PIN i_data[99]
    DIRECTION INPUT ;
    USE SIGNAL ;
    PORT
      LAYER M4 ;
        RECT  0 50.736 0.084 50.76 ;
    END
  END i_data[99]
  PIN i_data[9]
    DIRECTION INPUT ;
    USE SIGNAL ;
    PORT
      LAYER M4 ;
        RECT  0 11.856 0.084 11.88 ;
    END
  END i_data[9]
  PIN i_expected[0]
    DIRECTION INPUT ;
    USE SIGNAL ;
    PORT
      LAYER M4 ;
        RECT  0 120.288 0.084 120.312 ;
    END
  END i_expected[0]
  PIN i_expected[1]
    DIRECTION INPUT ;
    USE SIGNAL ;
    PORT
      LAYER M4 ;
        RECT  0 120.72 0.084 120.744 ;
    END
  END i_expected[1]
  PIN i_expected[2]
    DIRECTION INPUT ;
    USE SIGNAL ;
    PORT
      LAYER M4 ;
        RECT  0 121.152 0.084 121.176 ;
    END
  END i_expected[2]
  PIN i_expected[3]
    DIRECTION INPUT ;
    USE SIGNAL ;
    PORT
      LAYER M4 ;
        RECT  0 121.584 0.084 121.608 ;
    END
  END i_expected[3]
  PIN i_valid[0]
    DIRECTION INPUT ;
    USE SIGNAL ;
    PORT
      LAYER M4 ;
        RECT  0 118.56 0.084 118.584 ;
    END
  END i_valid[0]
  PIN i_valid[1]
    DIRECTION INPUT ;
    USE SIGNAL ;
    PORT
      LAYER M4 ;
        RECT  0 118.992 0.084 119.016 ;
    END
  END i_valid[1]
  PIN i_valid[2]
    DIRECTION INPUT ;
    USE SIGNAL ;
    PORT
      LAYER M4 ;
        RECT  0 119.424 0.084 119.448 ;
    END
  END i_valid[2]
  PIN i_valid[3]
    DIRECTION INPUT ;
    USE SIGNAL ;
    PORT
      LAYER M4 ;
        RECT  0 119.856 0.084 119.88 ;
    END
  END i_valid[3]
  PIN o_data[0]
    DIRECTION OUTPUT ;
    USE SIGNAL ;
    PORT
      LAYER M4 ;
        RECT  103.596 10.32 103.68 10.344 ;
    END
  END o_data[0]
  PIN o_data[100]
    DIRECTION OUTPUT ;
    USE SIGNAL ;
    PORT
      LAYER M4 ;
        RECT  103.596 53.52 103.68 53.544 ;
    END
  END o_data[100]
  PIN o_data[101]
    DIRECTION OUTPUT ;
    USE SIGNAL ;
    PORT
      LAYER M4 ;
        RECT  103.596 53.952 103.68 53.976 ;
    END
  END o_data[101]
  PIN o_data[102]
    DIRECTION OUTPUT ;
    USE SIGNAL ;
    PORT
      LAYER M4 ;
        RECT  103.596 54.384 103.68 54.408 ;
    END
  END o_data[102]
  PIN o_data[103]
    DIRECTION OUTPUT ;
    USE SIGNAL ;
    PORT
      LAYER M4 ;
        RECT  103.596 54.816 103.68 54.84 ;
    END
  END o_data[103]
  PIN o_data[104]
    DIRECTION OUTPUT ;
    USE SIGNAL ;
    PORT
      LAYER M4 ;
        RECT  103.596 55.248 103.68 55.272 ;
    END
  END o_data[104]
  PIN o_data[105]
    DIRECTION OUTPUT ;
    USE SIGNAL ;
    PORT
      LAYER M4 ;
        RECT  103.596 55.68 103.68 55.704 ;
    END
  END o_data[105]
  PIN o_data[106]
    DIRECTION OUTPUT ;
    USE SIGNAL ;
    PORT
      LAYER M4 ;
        RECT  103.596 56.112 103.68 56.136 ;
    END
  END o_data[106]
  PIN o_data[107]
    DIRECTION OUTPUT ;
    USE SIGNAL ;
    PORT
      LAYER M4 ;
        RECT  103.596 56.544 103.68 56.568 ;
    END
  END o_data[107]
  PIN o_data[108]
    DIRECTION OUTPUT ;
    USE SIGNAL ;
    PORT
      LAYER M4 ;
        RECT  103.596 56.976 103.68 57 ;
    END
  END o_data[108]
  PIN o_data[109]
    DIRECTION OUTPUT ;
    USE SIGNAL ;
    PORT
      LAYER M4 ;
        RECT  103.596 57.408 103.68 57.432 ;
    END
  END o_data[109]
  PIN o_data[10]
    DIRECTION OUTPUT ;
    USE SIGNAL ;
    PORT
      LAYER M4 ;
        RECT  103.596 14.64 103.68 14.664 ;
    END
  END o_data[10]
  PIN o_data[110]
    DIRECTION OUTPUT ;
    USE SIGNAL ;
    PORT
      LAYER M4 ;
        RECT  103.596 57.84 103.68 57.864 ;
    END
  END o_data[110]
  PIN o_data[111]
    DIRECTION OUTPUT ;
    USE SIGNAL ;
    PORT
      LAYER M4 ;
        RECT  103.596 58.272 103.68 58.296 ;
    END
  END o_data[111]
  PIN o_data[112]
    DIRECTION OUTPUT ;
    USE SIGNAL ;
    PORT
      LAYER M4 ;
        RECT  103.596 58.704 103.68 58.728 ;
    END
  END o_data[112]
  PIN o_data[113]
    DIRECTION OUTPUT ;
    USE SIGNAL ;
    PORT
      LAYER M4 ;
        RECT  103.596 59.136 103.68 59.16 ;
    END
  END o_data[113]
  PIN o_data[114]
    DIRECTION OUTPUT ;
    USE SIGNAL ;
    PORT
      LAYER M4 ;
        RECT  103.596 59.568 103.68 59.592 ;
    END
  END o_data[114]
  PIN o_data[115]
    DIRECTION OUTPUT ;
    USE SIGNAL ;
    PORT
      LAYER M4 ;
        RECT  103.596 60 103.68 60.024 ;
    END
  END o_data[115]
  PIN o_data[116]
    DIRECTION OUTPUT ;
    USE SIGNAL ;
    PORT
      LAYER M4 ;
        RECT  103.596 60.432 103.68 60.456 ;
    END
  END o_data[116]
  PIN o_data[117]
    DIRECTION OUTPUT ;
    USE SIGNAL ;
    PORT
      LAYER M4 ;
        RECT  103.596 60.864 103.68 60.888 ;
    END
  END o_data[117]
  PIN o_data[118]
    DIRECTION OUTPUT ;
    USE SIGNAL ;
    PORT
      LAYER M4 ;
        RECT  103.596 61.296 103.68 61.32 ;
    END
  END o_data[118]
  PIN o_data[119]
    DIRECTION OUTPUT ;
    USE SIGNAL ;
    PORT
      LAYER M4 ;
        RECT  103.596 61.728 103.68 61.752 ;
    END
  END o_data[119]
  PIN o_data[11]
    DIRECTION OUTPUT ;
    USE SIGNAL ;
    PORT
      LAYER M4 ;
        RECT  103.596 15.072 103.68 15.096 ;
    END
  END o_data[11]
  PIN o_data[120]
    DIRECTION OUTPUT ;
    USE SIGNAL ;
    PORT
      LAYER M4 ;
        RECT  103.596 62.16 103.68 62.184 ;
    END
  END o_data[120]
  PIN o_data[121]
    DIRECTION OUTPUT ;
    USE SIGNAL ;
    PORT
      LAYER M4 ;
        RECT  103.596 62.592 103.68 62.616 ;
    END
  END o_data[121]
  PIN o_data[122]
    DIRECTION OUTPUT ;
    USE SIGNAL ;
    PORT
      LAYER M4 ;
        RECT  103.596 63.024 103.68 63.048 ;
    END
  END o_data[122]
  PIN o_data[123]
    DIRECTION OUTPUT ;
    USE SIGNAL ;
    PORT
      LAYER M4 ;
        RECT  103.596 63.456 103.68 63.48 ;
    END
  END o_data[123]
  PIN o_data[124]
    DIRECTION OUTPUT ;
    USE SIGNAL ;
    PORT
      LAYER M4 ;
        RECT  103.596 63.888 103.68 63.912 ;
    END
  END o_data[124]
  PIN o_data[125]
    DIRECTION OUTPUT ;
    USE SIGNAL ;
    PORT
      LAYER M4 ;
        RECT  103.596 64.32 103.68 64.344 ;
    END
  END o_data[125]
  PIN o_data[126]
    DIRECTION OUTPUT ;
    USE SIGNAL ;
    PORT
      LAYER M4 ;
        RECT  103.596 64.752 103.68 64.776 ;
    END
  END o_data[126]
  PIN o_data[127]
    DIRECTION OUTPUT ;
    USE SIGNAL ;
    PORT
      LAYER M4 ;
        RECT  103.596 65.184 103.68 65.208 ;
    END
  END o_data[127]
  PIN o_data[128]
    DIRECTION OUTPUT ;
    USE SIGNAL ;
    PORT
      LAYER M4 ;
        RECT  103.596 65.616 103.68 65.64 ;
    END
  END o_data[128]
  PIN o_data[129]
    DIRECTION OUTPUT ;
    USE SIGNAL ;
    PORT
      LAYER M4 ;
        RECT  103.596 66.048 103.68 66.072 ;
    END
  END o_data[129]
  PIN o_data[12]
    DIRECTION OUTPUT ;
    USE SIGNAL ;
    PORT
      LAYER M4 ;
        RECT  103.596 15.504 103.68 15.528 ;
    END
  END o_data[12]
  PIN o_data[130]
    DIRECTION OUTPUT ;
    USE SIGNAL ;
    PORT
      LAYER M4 ;
        RECT  103.596 66.48 103.68 66.504 ;
    END
  END o_data[130]
  PIN o_data[131]
    DIRECTION OUTPUT ;
    USE SIGNAL ;
    PORT
      LAYER M4 ;
        RECT  103.596 66.912 103.68 66.936 ;
    END
  END o_data[131]
  PIN o_data[132]
    DIRECTION OUTPUT ;
    USE SIGNAL ;
    PORT
      LAYER M4 ;
        RECT  103.596 67.344 103.68 67.368 ;
    END
  END o_data[132]
  PIN o_data[133]
    DIRECTION OUTPUT ;
    USE SIGNAL ;
    PORT
      LAYER M4 ;
        RECT  103.596 67.776 103.68 67.8 ;
    END
  END o_data[133]
  PIN o_data[134]
    DIRECTION OUTPUT ;
    USE SIGNAL ;
    PORT
      LAYER M4 ;
        RECT  103.596 68.208 103.68 68.232 ;
    END
  END o_data[134]
  PIN o_data[135]
    DIRECTION OUTPUT ;
    USE SIGNAL ;
    PORT
      LAYER M4 ;
        RECT  103.596 68.64 103.68 68.664 ;
    END
  END o_data[135]
  PIN o_data[136]
    DIRECTION OUTPUT ;
    USE SIGNAL ;
    PORT
      LAYER M4 ;
        RECT  103.596 69.072 103.68 69.096 ;
    END
  END o_data[136]
  PIN o_data[137]
    DIRECTION OUTPUT ;
    USE SIGNAL ;
    PORT
      LAYER M4 ;
        RECT  103.596 69.504 103.68 69.528 ;
    END
  END o_data[137]
  PIN o_data[138]
    DIRECTION OUTPUT ;
    USE SIGNAL ;
    PORT
      LAYER M4 ;
        RECT  103.596 69.936 103.68 69.96 ;
    END
  END o_data[138]
  PIN o_data[139]
    DIRECTION OUTPUT ;
    USE SIGNAL ;
    PORT
      LAYER M4 ;
        RECT  103.596 70.368 103.68 70.392 ;
    END
  END o_data[139]
  PIN o_data[13]
    DIRECTION OUTPUT ;
    USE SIGNAL ;
    PORT
      LAYER M4 ;
        RECT  103.596 15.936 103.68 15.96 ;
    END
  END o_data[13]
  PIN o_data[140]
    DIRECTION OUTPUT ;
    USE SIGNAL ;
    PORT
      LAYER M4 ;
        RECT  103.596 70.8 103.68 70.824 ;
    END
  END o_data[140]
  PIN o_data[141]
    DIRECTION OUTPUT ;
    USE SIGNAL ;
    PORT
      LAYER M4 ;
        RECT  103.596 71.232 103.68 71.256 ;
    END
  END o_data[141]
  PIN o_data[142]
    DIRECTION OUTPUT ;
    USE SIGNAL ;
    PORT
      LAYER M4 ;
        RECT  103.596 71.664 103.68 71.688 ;
    END
  END o_data[142]
  PIN o_data[143]
    DIRECTION OUTPUT ;
    USE SIGNAL ;
    PORT
      LAYER M4 ;
        RECT  103.596 72.096 103.68 72.12 ;
    END
  END o_data[143]
  PIN o_data[144]
    DIRECTION OUTPUT ;
    USE SIGNAL ;
    PORT
      LAYER M4 ;
        RECT  103.596 72.528 103.68 72.552 ;
    END
  END o_data[144]
  PIN o_data[145]
    DIRECTION OUTPUT ;
    USE SIGNAL ;
    PORT
      LAYER M4 ;
        RECT  103.596 72.96 103.68 72.984 ;
    END
  END o_data[145]
  PIN o_data[146]
    DIRECTION OUTPUT ;
    USE SIGNAL ;
    PORT
      LAYER M4 ;
        RECT  103.596 73.392 103.68 73.416 ;
    END
  END o_data[146]
  PIN o_data[147]
    DIRECTION OUTPUT ;
    USE SIGNAL ;
    PORT
      LAYER M4 ;
        RECT  103.596 73.824 103.68 73.848 ;
    END
  END o_data[147]
  PIN o_data[148]
    DIRECTION OUTPUT ;
    USE SIGNAL ;
    PORT
      LAYER M4 ;
        RECT  103.596 74.256 103.68 74.28 ;
    END
  END o_data[148]
  PIN o_data[149]
    DIRECTION OUTPUT ;
    USE SIGNAL ;
    PORT
      LAYER M4 ;
        RECT  103.596 74.688 103.68 74.712 ;
    END
  END o_data[149]
  PIN o_data[14]
    DIRECTION OUTPUT ;
    USE SIGNAL ;
    PORT
      LAYER M4 ;
        RECT  103.596 16.368 103.68 16.392 ;
    END
  END o_data[14]
  PIN o_data[150]
    DIRECTION OUTPUT ;
    USE SIGNAL ;
    PORT
      LAYER M4 ;
        RECT  103.596 75.12 103.68 75.144 ;
    END
  END o_data[150]
  PIN o_data[151]
    DIRECTION OUTPUT ;
    USE SIGNAL ;
    PORT
      LAYER M4 ;
        RECT  103.596 75.552 103.68 75.576 ;
    END
  END o_data[151]
  PIN o_data[152]
    DIRECTION OUTPUT ;
    USE SIGNAL ;
    PORT
      LAYER M4 ;
        RECT  103.596 75.984 103.68 76.008 ;
    END
  END o_data[152]
  PIN o_data[153]
    DIRECTION OUTPUT ;
    USE SIGNAL ;
    PORT
      LAYER M4 ;
        RECT  103.596 76.416 103.68 76.44 ;
    END
  END o_data[153]
  PIN o_data[154]
    DIRECTION OUTPUT ;
    USE SIGNAL ;
    PORT
      LAYER M4 ;
        RECT  103.596 76.848 103.68 76.872 ;
    END
  END o_data[154]
  PIN o_data[155]
    DIRECTION OUTPUT ;
    USE SIGNAL ;
    PORT
      LAYER M4 ;
        RECT  103.596 77.28 103.68 77.304 ;
    END
  END o_data[155]
  PIN o_data[156]
    DIRECTION OUTPUT ;
    USE SIGNAL ;
    PORT
      LAYER M4 ;
        RECT  103.596 77.712 103.68 77.736 ;
    END
  END o_data[156]
  PIN o_data[157]
    DIRECTION OUTPUT ;
    USE SIGNAL ;
    PORT
      LAYER M4 ;
        RECT  103.596 78.144 103.68 78.168 ;
    END
  END o_data[157]
  PIN o_data[158]
    DIRECTION OUTPUT ;
    USE SIGNAL ;
    PORT
      LAYER M4 ;
        RECT  103.596 78.576 103.68 78.6 ;
    END
  END o_data[158]
  PIN o_data[159]
    DIRECTION OUTPUT ;
    USE SIGNAL ;
    PORT
      LAYER M4 ;
        RECT  103.596 79.008 103.68 79.032 ;
    END
  END o_data[159]
  PIN o_data[15]
    DIRECTION OUTPUT ;
    USE SIGNAL ;
    PORT
      LAYER M4 ;
        RECT  103.596 16.8 103.68 16.824 ;
    END
  END o_data[15]
  PIN o_data[160]
    DIRECTION OUTPUT ;
    USE SIGNAL ;
    PORT
      LAYER M4 ;
        RECT  103.596 79.44 103.68 79.464 ;
    END
  END o_data[160]
  PIN o_data[161]
    DIRECTION OUTPUT ;
    USE SIGNAL ;
    PORT
      LAYER M4 ;
        RECT  103.596 79.872 103.68 79.896 ;
    END
  END o_data[161]
  PIN o_data[162]
    DIRECTION OUTPUT ;
    USE SIGNAL ;
    PORT
      LAYER M4 ;
        RECT  103.596 80.304 103.68 80.328 ;
    END
  END o_data[162]
  PIN o_data[163]
    DIRECTION OUTPUT ;
    USE SIGNAL ;
    PORT
      LAYER M4 ;
        RECT  103.596 80.736 103.68 80.76 ;
    END
  END o_data[163]
  PIN o_data[164]
    DIRECTION OUTPUT ;
    USE SIGNAL ;
    PORT
      LAYER M4 ;
        RECT  103.596 81.168 103.68 81.192 ;
    END
  END o_data[164]
  PIN o_data[165]
    DIRECTION OUTPUT ;
    USE SIGNAL ;
    PORT
      LAYER M4 ;
        RECT  103.596 81.6 103.68 81.624 ;
    END
  END o_data[165]
  PIN o_data[166]
    DIRECTION OUTPUT ;
    USE SIGNAL ;
    PORT
      LAYER M4 ;
        RECT  103.596 82.032 103.68 82.056 ;
    END
  END o_data[166]
  PIN o_data[167]
    DIRECTION OUTPUT ;
    USE SIGNAL ;
    PORT
      LAYER M4 ;
        RECT  103.596 82.464 103.68 82.488 ;
    END
  END o_data[167]
  PIN o_data[168]
    DIRECTION OUTPUT ;
    USE SIGNAL ;
    PORT
      LAYER M4 ;
        RECT  103.596 82.896 103.68 82.92 ;
    END
  END o_data[168]
  PIN o_data[169]
    DIRECTION OUTPUT ;
    USE SIGNAL ;
    PORT
      LAYER M4 ;
        RECT  103.596 83.328 103.68 83.352 ;
    END
  END o_data[169]
  PIN o_data[16]
    DIRECTION OUTPUT ;
    USE SIGNAL ;
    PORT
      LAYER M4 ;
        RECT  103.596 17.232 103.68 17.256 ;
    END
  END o_data[16]
  PIN o_data[170]
    DIRECTION OUTPUT ;
    USE SIGNAL ;
    PORT
      LAYER M4 ;
        RECT  103.596 83.76 103.68 83.784 ;
    END
  END o_data[170]
  PIN o_data[171]
    DIRECTION OUTPUT ;
    USE SIGNAL ;
    PORT
      LAYER M4 ;
        RECT  103.596 84.192 103.68 84.216 ;
    END
  END o_data[171]
  PIN o_data[172]
    DIRECTION OUTPUT ;
    USE SIGNAL ;
    PORT
      LAYER M4 ;
        RECT  103.596 84.624 103.68 84.648 ;
    END
  END o_data[172]
  PIN o_data[173]
    DIRECTION OUTPUT ;
    USE SIGNAL ;
    PORT
      LAYER M4 ;
        RECT  103.596 85.056 103.68 85.08 ;
    END
  END o_data[173]
  PIN o_data[174]
    DIRECTION OUTPUT ;
    USE SIGNAL ;
    PORT
      LAYER M4 ;
        RECT  103.596 85.488 103.68 85.512 ;
    END
  END o_data[174]
  PIN o_data[175]
    DIRECTION OUTPUT ;
    USE SIGNAL ;
    PORT
      LAYER M4 ;
        RECT  103.596 85.92 103.68 85.944 ;
    END
  END o_data[175]
  PIN o_data[176]
    DIRECTION OUTPUT ;
    USE SIGNAL ;
    PORT
      LAYER M4 ;
        RECT  103.596 86.352 103.68 86.376 ;
    END
  END o_data[176]
  PIN o_data[177]
    DIRECTION OUTPUT ;
    USE SIGNAL ;
    PORT
      LAYER M4 ;
        RECT  103.596 86.784 103.68 86.808 ;
    END
  END o_data[177]
  PIN o_data[178]
    DIRECTION OUTPUT ;
    USE SIGNAL ;
    PORT
      LAYER M4 ;
        RECT  103.596 87.216 103.68 87.24 ;
    END
  END o_data[178]
  PIN o_data[179]
    DIRECTION OUTPUT ;
    USE SIGNAL ;
    PORT
      LAYER M4 ;
        RECT  103.596 87.648 103.68 87.672 ;
    END
  END o_data[179]
  PIN o_data[17]
    DIRECTION OUTPUT ;
    USE SIGNAL ;
    PORT
      LAYER M4 ;
        RECT  103.596 17.664 103.68 17.688 ;
    END
  END o_data[17]
  PIN o_data[180]
    DIRECTION OUTPUT ;
    USE SIGNAL ;
    PORT
      LAYER M4 ;
        RECT  103.596 88.08 103.68 88.104 ;
    END
  END o_data[180]
  PIN o_data[181]
    DIRECTION OUTPUT ;
    USE SIGNAL ;
    PORT
      LAYER M4 ;
        RECT  103.596 88.512 103.68 88.536 ;
    END
  END o_data[181]
  PIN o_data[182]
    DIRECTION OUTPUT ;
    USE SIGNAL ;
    PORT
      LAYER M4 ;
        RECT  103.596 88.944 103.68 88.968 ;
    END
  END o_data[182]
  PIN o_data[183]
    DIRECTION OUTPUT ;
    USE SIGNAL ;
    PORT
      LAYER M4 ;
        RECT  103.596 89.376 103.68 89.4 ;
    END
  END o_data[183]
  PIN o_data[184]
    DIRECTION OUTPUT ;
    USE SIGNAL ;
    PORT
      LAYER M4 ;
        RECT  103.596 89.808 103.68 89.832 ;
    END
  END o_data[184]
  PIN o_data[185]
    DIRECTION OUTPUT ;
    USE SIGNAL ;
    PORT
      LAYER M4 ;
        RECT  103.596 90.24 103.68 90.264 ;
    END
  END o_data[185]
  PIN o_data[186]
    DIRECTION OUTPUT ;
    USE SIGNAL ;
    PORT
      LAYER M4 ;
        RECT  103.596 90.672 103.68 90.696 ;
    END
  END o_data[186]
  PIN o_data[187]
    DIRECTION OUTPUT ;
    USE SIGNAL ;
    PORT
      LAYER M4 ;
        RECT  103.596 91.104 103.68 91.128 ;
    END
  END o_data[187]
  PIN o_data[188]
    DIRECTION OUTPUT ;
    USE SIGNAL ;
    PORT
      LAYER M4 ;
        RECT  103.596 91.536 103.68 91.56 ;
    END
  END o_data[188]
  PIN o_data[189]
    DIRECTION OUTPUT ;
    USE SIGNAL ;
    PORT
      LAYER M4 ;
        RECT  103.596 91.968 103.68 91.992 ;
    END
  END o_data[189]
  PIN o_data[18]
    DIRECTION OUTPUT ;
    USE SIGNAL ;
    PORT
      LAYER M4 ;
        RECT  103.596 18.096 103.68 18.12 ;
    END
  END o_data[18]
  PIN o_data[190]
    DIRECTION OUTPUT ;
    USE SIGNAL ;
    PORT
      LAYER M4 ;
        RECT  103.596 92.4 103.68 92.424 ;
    END
  END o_data[190]
  PIN o_data[191]
    DIRECTION OUTPUT ;
    USE SIGNAL ;
    PORT
      LAYER M4 ;
        RECT  103.596 92.832 103.68 92.856 ;
    END
  END o_data[191]
  PIN o_data[192]
    DIRECTION OUTPUT ;
    USE SIGNAL ;
    PORT
      LAYER M4 ;
        RECT  103.596 93.264 103.68 93.288 ;
    END
  END o_data[192]
  PIN o_data[193]
    DIRECTION OUTPUT ;
    USE SIGNAL ;
    PORT
      LAYER M4 ;
        RECT  103.596 93.696 103.68 93.72 ;
    END
  END o_data[193]
  PIN o_data[194]
    DIRECTION OUTPUT ;
    USE SIGNAL ;
    PORT
      LAYER M4 ;
        RECT  103.596 94.128 103.68 94.152 ;
    END
  END o_data[194]
  PIN o_data[195]
    DIRECTION OUTPUT ;
    USE SIGNAL ;
    PORT
      LAYER M4 ;
        RECT  103.596 94.56 103.68 94.584 ;
    END
  END o_data[195]
  PIN o_data[196]
    DIRECTION OUTPUT ;
    USE SIGNAL ;
    PORT
      LAYER M4 ;
        RECT  103.596 94.992 103.68 95.016 ;
    END
  END o_data[196]
  PIN o_data[197]
    DIRECTION OUTPUT ;
    USE SIGNAL ;
    PORT
      LAYER M4 ;
        RECT  103.596 95.424 103.68 95.448 ;
    END
  END o_data[197]
  PIN o_data[198]
    DIRECTION OUTPUT ;
    USE SIGNAL ;
    PORT
      LAYER M4 ;
        RECT  103.596 95.856 103.68 95.88 ;
    END
  END o_data[198]
  PIN o_data[199]
    DIRECTION OUTPUT ;
    USE SIGNAL ;
    PORT
      LAYER M4 ;
        RECT  103.596 96.288 103.68 96.312 ;
    END
  END o_data[199]
  PIN o_data[19]
    DIRECTION OUTPUT ;
    USE SIGNAL ;
    PORT
      LAYER M4 ;
        RECT  103.596 18.528 103.68 18.552 ;
    END
  END o_data[19]
  PIN o_data[1]
    DIRECTION OUTPUT ;
    USE SIGNAL ;
    PORT
      LAYER M4 ;
        RECT  103.596 10.752 103.68 10.776 ;
    END
  END o_data[1]
  PIN o_data[200]
    DIRECTION OUTPUT ;
    USE SIGNAL ;
    PORT
      LAYER M4 ;
        RECT  103.596 96.72 103.68 96.744 ;
    END
  END o_data[200]
  PIN o_data[201]
    DIRECTION OUTPUT ;
    USE SIGNAL ;
    PORT
      LAYER M4 ;
        RECT  103.596 97.152 103.68 97.176 ;
    END
  END o_data[201]
  PIN o_data[202]
    DIRECTION OUTPUT ;
    USE SIGNAL ;
    PORT
      LAYER M4 ;
        RECT  103.596 97.584 103.68 97.608 ;
    END
  END o_data[202]
  PIN o_data[203]
    DIRECTION OUTPUT ;
    USE SIGNAL ;
    PORT
      LAYER M4 ;
        RECT  103.596 98.016 103.68 98.04 ;
    END
  END o_data[203]
  PIN o_data[204]
    DIRECTION OUTPUT ;
    USE SIGNAL ;
    PORT
      LAYER M4 ;
        RECT  103.596 98.448 103.68 98.472 ;
    END
  END o_data[204]
  PIN o_data[205]
    DIRECTION OUTPUT ;
    USE SIGNAL ;
    PORT
      LAYER M4 ;
        RECT  103.596 98.88 103.68 98.904 ;
    END
  END o_data[205]
  PIN o_data[206]
    DIRECTION OUTPUT ;
    USE SIGNAL ;
    PORT
      LAYER M4 ;
        RECT  103.596 99.312 103.68 99.336 ;
    END
  END o_data[206]
  PIN o_data[207]
    DIRECTION OUTPUT ;
    USE SIGNAL ;
    PORT
      LAYER M4 ;
        RECT  103.596 99.744 103.68 99.768 ;
    END
  END o_data[207]
  PIN o_data[208]
    DIRECTION OUTPUT ;
    USE SIGNAL ;
    PORT
      LAYER M4 ;
        RECT  103.596 100.176 103.68 100.2 ;
    END
  END o_data[208]
  PIN o_data[209]
    DIRECTION OUTPUT ;
    USE SIGNAL ;
    PORT
      LAYER M4 ;
        RECT  103.596 100.608 103.68 100.632 ;
    END
  END o_data[209]
  PIN o_data[20]
    DIRECTION OUTPUT ;
    USE SIGNAL ;
    PORT
      LAYER M4 ;
        RECT  103.596 18.96 103.68 18.984 ;
    END
  END o_data[20]
  PIN o_data[210]
    DIRECTION OUTPUT ;
    USE SIGNAL ;
    PORT
      LAYER M4 ;
        RECT  103.596 101.04 103.68 101.064 ;
    END
  END o_data[210]
  PIN o_data[211]
    DIRECTION OUTPUT ;
    USE SIGNAL ;
    PORT
      LAYER M4 ;
        RECT  103.596 101.472 103.68 101.496 ;
    END
  END o_data[211]
  PIN o_data[212]
    DIRECTION OUTPUT ;
    USE SIGNAL ;
    PORT
      LAYER M4 ;
        RECT  103.596 101.904 103.68 101.928 ;
    END
  END o_data[212]
  PIN o_data[213]
    DIRECTION OUTPUT ;
    USE SIGNAL ;
    PORT
      LAYER M4 ;
        RECT  103.596 102.336 103.68 102.36 ;
    END
  END o_data[213]
  PIN o_data[214]
    DIRECTION OUTPUT ;
    USE SIGNAL ;
    PORT
      LAYER M4 ;
        RECT  103.596 102.768 103.68 102.792 ;
    END
  END o_data[214]
  PIN o_data[215]
    DIRECTION OUTPUT ;
    USE SIGNAL ;
    PORT
      LAYER M4 ;
        RECT  103.596 103.2 103.68 103.224 ;
    END
  END o_data[215]
  PIN o_data[216]
    DIRECTION OUTPUT ;
    USE SIGNAL ;
    PORT
      LAYER M4 ;
        RECT  103.596 103.632 103.68 103.656 ;
    END
  END o_data[216]
  PIN o_data[217]
    DIRECTION OUTPUT ;
    USE SIGNAL ;
    PORT
      LAYER M4 ;
        RECT  103.596 104.064 103.68 104.088 ;
    END
  END o_data[217]
  PIN o_data[218]
    DIRECTION OUTPUT ;
    USE SIGNAL ;
    PORT
      LAYER M4 ;
        RECT  103.596 104.496 103.68 104.52 ;
    END
  END o_data[218]
  PIN o_data[219]
    DIRECTION OUTPUT ;
    USE SIGNAL ;
    PORT
      LAYER M4 ;
        RECT  103.596 104.928 103.68 104.952 ;
    END
  END o_data[219]
  PIN o_data[21]
    DIRECTION OUTPUT ;
    USE SIGNAL ;
    PORT
      LAYER M4 ;
        RECT  103.596 19.392 103.68 19.416 ;
    END
  END o_data[21]
  PIN o_data[220]
    DIRECTION OUTPUT ;
    USE SIGNAL ;
    PORT
      LAYER M4 ;
        RECT  103.596 105.36 103.68 105.384 ;
    END
  END o_data[220]
  PIN o_data[221]
    DIRECTION OUTPUT ;
    USE SIGNAL ;
    PORT
      LAYER M4 ;
        RECT  103.596 105.792 103.68 105.816 ;
    END
  END o_data[221]
  PIN o_data[222]
    DIRECTION OUTPUT ;
    USE SIGNAL ;
    PORT
      LAYER M4 ;
        RECT  103.596 106.224 103.68 106.248 ;
    END
  END o_data[222]
  PIN o_data[223]
    DIRECTION OUTPUT ;
    USE SIGNAL ;
    PORT
      LAYER M4 ;
        RECT  103.596 106.656 103.68 106.68 ;
    END
  END o_data[223]
  PIN o_data[224]
    DIRECTION OUTPUT ;
    USE SIGNAL ;
    PORT
      LAYER M4 ;
        RECT  103.596 107.088 103.68 107.112 ;
    END
  END o_data[224]
  PIN o_data[225]
    DIRECTION OUTPUT ;
    USE SIGNAL ;
    PORT
      LAYER M4 ;
        RECT  103.596 107.52 103.68 107.544 ;
    END
  END o_data[225]
  PIN o_data[226]
    DIRECTION OUTPUT ;
    USE SIGNAL ;
    PORT
      LAYER M4 ;
        RECT  103.596 107.952 103.68 107.976 ;
    END
  END o_data[226]
  PIN o_data[227]
    DIRECTION OUTPUT ;
    USE SIGNAL ;
    PORT
      LAYER M4 ;
        RECT  103.596 108.384 103.68 108.408 ;
    END
  END o_data[227]
  PIN o_data[228]
    DIRECTION OUTPUT ;
    USE SIGNAL ;
    PORT
      LAYER M4 ;
        RECT  103.596 108.816 103.68 108.84 ;
    END
  END o_data[228]
  PIN o_data[229]
    DIRECTION OUTPUT ;
    USE SIGNAL ;
    PORT
      LAYER M4 ;
        RECT  103.596 109.248 103.68 109.272 ;
    END
  END o_data[229]
  PIN o_data[22]
    DIRECTION OUTPUT ;
    USE SIGNAL ;
    PORT
      LAYER M4 ;
        RECT  103.596 19.824 103.68 19.848 ;
    END
  END o_data[22]
  PIN o_data[230]
    DIRECTION OUTPUT ;
    USE SIGNAL ;
    PORT
      LAYER M4 ;
        RECT  103.596 109.68 103.68 109.704 ;
    END
  END o_data[230]
  PIN o_data[231]
    DIRECTION OUTPUT ;
    USE SIGNAL ;
    PORT
      LAYER M4 ;
        RECT  103.596 110.112 103.68 110.136 ;
    END
  END o_data[231]
  PIN o_data[232]
    DIRECTION OUTPUT ;
    USE SIGNAL ;
    PORT
      LAYER M4 ;
        RECT  103.596 110.544 103.68 110.568 ;
    END
  END o_data[232]
  PIN o_data[233]
    DIRECTION OUTPUT ;
    USE SIGNAL ;
    PORT
      LAYER M4 ;
        RECT  103.596 110.976 103.68 111 ;
    END
  END o_data[233]
  PIN o_data[234]
    DIRECTION OUTPUT ;
    USE SIGNAL ;
    PORT
      LAYER M4 ;
        RECT  103.596 111.408 103.68 111.432 ;
    END
  END o_data[234]
  PIN o_data[235]
    DIRECTION OUTPUT ;
    USE SIGNAL ;
    PORT
      LAYER M4 ;
        RECT  103.596 111.84 103.68 111.864 ;
    END
  END o_data[235]
  PIN o_data[236]
    DIRECTION OUTPUT ;
    USE SIGNAL ;
    PORT
      LAYER M4 ;
        RECT  103.596 112.272 103.68 112.296 ;
    END
  END o_data[236]
  PIN o_data[237]
    DIRECTION OUTPUT ;
    USE SIGNAL ;
    PORT
      LAYER M4 ;
        RECT  103.596 112.704 103.68 112.728 ;
    END
  END o_data[237]
  PIN o_data[238]
    DIRECTION OUTPUT ;
    USE SIGNAL ;
    PORT
      LAYER M4 ;
        RECT  103.596 113.136 103.68 113.16 ;
    END
  END o_data[238]
  PIN o_data[239]
    DIRECTION OUTPUT ;
    USE SIGNAL ;
    PORT
      LAYER M4 ;
        RECT  103.596 113.568 103.68 113.592 ;
    END
  END o_data[239]
  PIN o_data[23]
    DIRECTION OUTPUT ;
    USE SIGNAL ;
    PORT
      LAYER M4 ;
        RECT  103.596 20.256 103.68 20.28 ;
    END
  END o_data[23]
  PIN o_data[240]
    DIRECTION OUTPUT ;
    USE SIGNAL ;
    PORT
      LAYER M4 ;
        RECT  103.596 114 103.68 114.024 ;
    END
  END o_data[240]
  PIN o_data[241]
    DIRECTION OUTPUT ;
    USE SIGNAL ;
    PORT
      LAYER M4 ;
        RECT  103.596 114.432 103.68 114.456 ;
    END
  END o_data[241]
  PIN o_data[242]
    DIRECTION OUTPUT ;
    USE SIGNAL ;
    PORT
      LAYER M4 ;
        RECT  103.596 114.864 103.68 114.888 ;
    END
  END o_data[242]
  PIN o_data[243]
    DIRECTION OUTPUT ;
    USE SIGNAL ;
    PORT
      LAYER M4 ;
        RECT  103.596 115.296 103.68 115.32 ;
    END
  END o_data[243]
  PIN o_data[244]
    DIRECTION OUTPUT ;
    USE SIGNAL ;
    PORT
      LAYER M4 ;
        RECT  103.596 115.728 103.68 115.752 ;
    END
  END o_data[244]
  PIN o_data[245]
    DIRECTION OUTPUT ;
    USE SIGNAL ;
    PORT
      LAYER M4 ;
        RECT  103.596 116.16 103.68 116.184 ;
    END
  END o_data[245]
  PIN o_data[246]
    DIRECTION OUTPUT ;
    USE SIGNAL ;
    PORT
      LAYER M4 ;
        RECT  103.596 116.592 103.68 116.616 ;
    END
  END o_data[246]
  PIN o_data[247]
    DIRECTION OUTPUT ;
    USE SIGNAL ;
    PORT
      LAYER M4 ;
        RECT  103.596 117.024 103.68 117.048 ;
    END
  END o_data[247]
  PIN o_data[248]
    DIRECTION OUTPUT ;
    USE SIGNAL ;
    PORT
      LAYER M4 ;
        RECT  103.596 117.456 103.68 117.48 ;
    END
  END o_data[248]
  PIN o_data[249]
    DIRECTION OUTPUT ;
    USE SIGNAL ;
    PORT
      LAYER M4 ;
        RECT  103.596 117.888 103.68 117.912 ;
    END
  END o_data[249]
  PIN o_data[24]
    DIRECTION OUTPUT ;
    USE SIGNAL ;
    PORT
      LAYER M4 ;
        RECT  103.596 20.688 103.68 20.712 ;
    END
  END o_data[24]
  PIN o_data[250]
    DIRECTION OUTPUT ;
    USE SIGNAL ;
    PORT
      LAYER M4 ;
        RECT  103.596 118.32 103.68 118.344 ;
    END
  END o_data[250]
  PIN o_data[251]
    DIRECTION OUTPUT ;
    USE SIGNAL ;
    PORT
      LAYER M4 ;
        RECT  103.596 118.752 103.68 118.776 ;
    END
  END o_data[251]
  PIN o_data[252]
    DIRECTION OUTPUT ;
    USE SIGNAL ;
    PORT
      LAYER M4 ;
        RECT  103.596 119.184 103.68 119.208 ;
    END
  END o_data[252]
  PIN o_data[253]
    DIRECTION OUTPUT ;
    USE SIGNAL ;
    PORT
      LAYER M4 ;
        RECT  103.596 119.616 103.68 119.64 ;
    END
  END o_data[253]
  PIN o_data[254]
    DIRECTION OUTPUT ;
    USE SIGNAL ;
    PORT
      LAYER M4 ;
        RECT  103.596 120.048 103.68 120.072 ;
    END
  END o_data[254]
  PIN o_data[255]
    DIRECTION OUTPUT ;
    USE SIGNAL ;
    PORT
      LAYER M4 ;
        RECT  103.596 120.48 103.68 120.504 ;
    END
  END o_data[255]
  PIN o_data[25]
    DIRECTION OUTPUT ;
    USE SIGNAL ;
    PORT
      LAYER M4 ;
        RECT  103.596 21.12 103.68 21.144 ;
    END
  END o_data[25]
  PIN o_data[26]
    DIRECTION OUTPUT ;
    USE SIGNAL ;
    PORT
      LAYER M4 ;
        RECT  103.596 21.552 103.68 21.576 ;
    END
  END o_data[26]
  PIN o_data[27]
    DIRECTION OUTPUT ;
    USE SIGNAL ;
    PORT
      LAYER M4 ;
        RECT  103.596 21.984 103.68 22.008 ;
    END
  END o_data[27]
  PIN o_data[28]
    DIRECTION OUTPUT ;
    USE SIGNAL ;
    PORT
      LAYER M4 ;
        RECT  103.596 22.416 103.68 22.44 ;
    END
  END o_data[28]
  PIN o_data[29]
    DIRECTION OUTPUT ;
    USE SIGNAL ;
    PORT
      LAYER M4 ;
        RECT  103.596 22.848 103.68 22.872 ;
    END
  END o_data[29]
  PIN o_data[2]
    DIRECTION OUTPUT ;
    USE SIGNAL ;
    PORT
      LAYER M4 ;
        RECT  103.596 11.184 103.68 11.208 ;
    END
  END o_data[2]
  PIN o_data[30]
    DIRECTION OUTPUT ;
    USE SIGNAL ;
    PORT
      LAYER M4 ;
        RECT  103.596 23.28 103.68 23.304 ;
    END
  END o_data[30]
  PIN o_data[31]
    DIRECTION OUTPUT ;
    USE SIGNAL ;
    PORT
      LAYER M4 ;
        RECT  103.596 23.712 103.68 23.736 ;
    END
  END o_data[31]
  PIN o_data[32]
    DIRECTION OUTPUT ;
    USE SIGNAL ;
    PORT
      LAYER M4 ;
        RECT  103.596 24.144 103.68 24.168 ;
    END
  END o_data[32]
  PIN o_data[33]
    DIRECTION OUTPUT ;
    USE SIGNAL ;
    PORT
      LAYER M4 ;
        RECT  103.596 24.576 103.68 24.6 ;
    END
  END o_data[33]
  PIN o_data[34]
    DIRECTION OUTPUT ;
    USE SIGNAL ;
    PORT
      LAYER M4 ;
        RECT  103.596 25.008 103.68 25.032 ;
    END
  END o_data[34]
  PIN o_data[35]
    DIRECTION OUTPUT ;
    USE SIGNAL ;
    PORT
      LAYER M4 ;
        RECT  103.596 25.44 103.68 25.464 ;
    END
  END o_data[35]
  PIN o_data[36]
    DIRECTION OUTPUT ;
    USE SIGNAL ;
    PORT
      LAYER M4 ;
        RECT  103.596 25.872 103.68 25.896 ;
    END
  END o_data[36]
  PIN o_data[37]
    DIRECTION OUTPUT ;
    USE SIGNAL ;
    PORT
      LAYER M4 ;
        RECT  103.596 26.304 103.68 26.328 ;
    END
  END o_data[37]
  PIN o_data[38]
    DIRECTION OUTPUT ;
    USE SIGNAL ;
    PORT
      LAYER M4 ;
        RECT  103.596 26.736 103.68 26.76 ;
    END
  END o_data[38]
  PIN o_data[39]
    DIRECTION OUTPUT ;
    USE SIGNAL ;
    PORT
      LAYER M4 ;
        RECT  103.596 27.168 103.68 27.192 ;
    END
  END o_data[39]
  PIN o_data[3]
    DIRECTION OUTPUT ;
    USE SIGNAL ;
    PORT
      LAYER M4 ;
        RECT  103.596 11.616 103.68 11.64 ;
    END
  END o_data[3]
  PIN o_data[40]
    DIRECTION OUTPUT ;
    USE SIGNAL ;
    PORT
      LAYER M4 ;
        RECT  103.596 27.6 103.68 27.624 ;
    END
  END o_data[40]
  PIN o_data[41]
    DIRECTION OUTPUT ;
    USE SIGNAL ;
    PORT
      LAYER M4 ;
        RECT  103.596 28.032 103.68 28.056 ;
    END
  END o_data[41]
  PIN o_data[42]
    DIRECTION OUTPUT ;
    USE SIGNAL ;
    PORT
      LAYER M4 ;
        RECT  103.596 28.464 103.68 28.488 ;
    END
  END o_data[42]
  PIN o_data[43]
    DIRECTION OUTPUT ;
    USE SIGNAL ;
    PORT
      LAYER M4 ;
        RECT  103.596 28.896 103.68 28.92 ;
    END
  END o_data[43]
  PIN o_data[44]
    DIRECTION OUTPUT ;
    USE SIGNAL ;
    PORT
      LAYER M4 ;
        RECT  103.596 29.328 103.68 29.352 ;
    END
  END o_data[44]
  PIN o_data[45]
    DIRECTION OUTPUT ;
    USE SIGNAL ;
    PORT
      LAYER M4 ;
        RECT  103.596 29.76 103.68 29.784 ;
    END
  END o_data[45]
  PIN o_data[46]
    DIRECTION OUTPUT ;
    USE SIGNAL ;
    PORT
      LAYER M4 ;
        RECT  103.596 30.192 103.68 30.216 ;
    END
  END o_data[46]
  PIN o_data[47]
    DIRECTION OUTPUT ;
    USE SIGNAL ;
    PORT
      LAYER M4 ;
        RECT  103.596 30.624 103.68 30.648 ;
    END
  END o_data[47]
  PIN o_data[48]
    DIRECTION OUTPUT ;
    USE SIGNAL ;
    PORT
      LAYER M4 ;
        RECT  103.596 31.056 103.68 31.08 ;
    END
  END o_data[48]
  PIN o_data[49]
    DIRECTION OUTPUT ;
    USE SIGNAL ;
    PORT
      LAYER M4 ;
        RECT  103.596 31.488 103.68 31.512 ;
    END
  END o_data[49]
  PIN o_data[4]
    DIRECTION OUTPUT ;
    USE SIGNAL ;
    PORT
      LAYER M4 ;
        RECT  103.596 12.048 103.68 12.072 ;
    END
  END o_data[4]
  PIN o_data[50]
    DIRECTION OUTPUT ;
    USE SIGNAL ;
    PORT
      LAYER M4 ;
        RECT  103.596 31.92 103.68 31.944 ;
    END
  END o_data[50]
  PIN o_data[51]
    DIRECTION OUTPUT ;
    USE SIGNAL ;
    PORT
      LAYER M4 ;
        RECT  103.596 32.352 103.68 32.376 ;
    END
  END o_data[51]
  PIN o_data[52]
    DIRECTION OUTPUT ;
    USE SIGNAL ;
    PORT
      LAYER M4 ;
        RECT  103.596 32.784 103.68 32.808 ;
    END
  END o_data[52]
  PIN o_data[53]
    DIRECTION OUTPUT ;
    USE SIGNAL ;
    PORT
      LAYER M4 ;
        RECT  103.596 33.216 103.68 33.24 ;
    END
  END o_data[53]
  PIN o_data[54]
    DIRECTION OUTPUT ;
    USE SIGNAL ;
    PORT
      LAYER M4 ;
        RECT  103.596 33.648 103.68 33.672 ;
    END
  END o_data[54]
  PIN o_data[55]
    DIRECTION OUTPUT ;
    USE SIGNAL ;
    PORT
      LAYER M4 ;
        RECT  103.596 34.08 103.68 34.104 ;
    END
  END o_data[55]
  PIN o_data[56]
    DIRECTION OUTPUT ;
    USE SIGNAL ;
    PORT
      LAYER M4 ;
        RECT  103.596 34.512 103.68 34.536 ;
    END
  END o_data[56]
  PIN o_data[57]
    DIRECTION OUTPUT ;
    USE SIGNAL ;
    PORT
      LAYER M4 ;
        RECT  103.596 34.944 103.68 34.968 ;
    END
  END o_data[57]
  PIN o_data[58]
    DIRECTION OUTPUT ;
    USE SIGNAL ;
    PORT
      LAYER M4 ;
        RECT  103.596 35.376 103.68 35.4 ;
    END
  END o_data[58]
  PIN o_data[59]
    DIRECTION OUTPUT ;
    USE SIGNAL ;
    PORT
      LAYER M4 ;
        RECT  103.596 35.808 103.68 35.832 ;
    END
  END o_data[59]
  PIN o_data[5]
    DIRECTION OUTPUT ;
    USE SIGNAL ;
    PORT
      LAYER M4 ;
        RECT  103.596 12.48 103.68 12.504 ;
    END
  END o_data[5]
  PIN o_data[60]
    DIRECTION OUTPUT ;
    USE SIGNAL ;
    PORT
      LAYER M4 ;
        RECT  103.596 36.24 103.68 36.264 ;
    END
  END o_data[60]
  PIN o_data[61]
    DIRECTION OUTPUT ;
    USE SIGNAL ;
    PORT
      LAYER M4 ;
        RECT  103.596 36.672 103.68 36.696 ;
    END
  END o_data[61]
  PIN o_data[62]
    DIRECTION OUTPUT ;
    USE SIGNAL ;
    PORT
      LAYER M4 ;
        RECT  103.596 37.104 103.68 37.128 ;
    END
  END o_data[62]
  PIN o_data[63]
    DIRECTION OUTPUT ;
    USE SIGNAL ;
    PORT
      LAYER M4 ;
        RECT  103.596 37.536 103.68 37.56 ;
    END
  END o_data[63]
  PIN o_data[64]
    DIRECTION OUTPUT ;
    USE SIGNAL ;
    PORT
      LAYER M4 ;
        RECT  103.596 37.968 103.68 37.992 ;
    END
  END o_data[64]
  PIN o_data[65]
    DIRECTION OUTPUT ;
    USE SIGNAL ;
    PORT
      LAYER M4 ;
        RECT  103.596 38.4 103.68 38.424 ;
    END
  END o_data[65]
  PIN o_data[66]
    DIRECTION OUTPUT ;
    USE SIGNAL ;
    PORT
      LAYER M4 ;
        RECT  103.596 38.832 103.68 38.856 ;
    END
  END o_data[66]
  PIN o_data[67]
    DIRECTION OUTPUT ;
    USE SIGNAL ;
    PORT
      LAYER M4 ;
        RECT  103.596 39.264 103.68 39.288 ;
    END
  END o_data[67]
  PIN o_data[68]
    DIRECTION OUTPUT ;
    USE SIGNAL ;
    PORT
      LAYER M4 ;
        RECT  103.596 39.696 103.68 39.72 ;
    END
  END o_data[68]
  PIN o_data[69]
    DIRECTION OUTPUT ;
    USE SIGNAL ;
    PORT
      LAYER M4 ;
        RECT  103.596 40.128 103.68 40.152 ;
    END
  END o_data[69]
  PIN o_data[6]
    DIRECTION OUTPUT ;
    USE SIGNAL ;
    PORT
      LAYER M4 ;
        RECT  103.596 12.912 103.68 12.936 ;
    END
  END o_data[6]
  PIN o_data[70]
    DIRECTION OUTPUT ;
    USE SIGNAL ;
    PORT
      LAYER M4 ;
        RECT  103.596 40.56 103.68 40.584 ;
    END
  END o_data[70]
  PIN o_data[71]
    DIRECTION OUTPUT ;
    USE SIGNAL ;
    PORT
      LAYER M4 ;
        RECT  103.596 40.992 103.68 41.016 ;
    END
  END o_data[71]
  PIN o_data[72]
    DIRECTION OUTPUT ;
    USE SIGNAL ;
    PORT
      LAYER M4 ;
        RECT  103.596 41.424 103.68 41.448 ;
    END
  END o_data[72]
  PIN o_data[73]
    DIRECTION OUTPUT ;
    USE SIGNAL ;
    PORT
      LAYER M4 ;
        RECT  103.596 41.856 103.68 41.88 ;
    END
  END o_data[73]
  PIN o_data[74]
    DIRECTION OUTPUT ;
    USE SIGNAL ;
    PORT
      LAYER M4 ;
        RECT  103.596 42.288 103.68 42.312 ;
    END
  END o_data[74]
  PIN o_data[75]
    DIRECTION OUTPUT ;
    USE SIGNAL ;
    PORT
      LAYER M4 ;
        RECT  103.596 42.72 103.68 42.744 ;
    END
  END o_data[75]
  PIN o_data[76]
    DIRECTION OUTPUT ;
    USE SIGNAL ;
    PORT
      LAYER M4 ;
        RECT  103.596 43.152 103.68 43.176 ;
    END
  END o_data[76]
  PIN o_data[77]
    DIRECTION OUTPUT ;
    USE SIGNAL ;
    PORT
      LAYER M4 ;
        RECT  103.596 43.584 103.68 43.608 ;
    END
  END o_data[77]
  PIN o_data[78]
    DIRECTION OUTPUT ;
    USE SIGNAL ;
    PORT
      LAYER M4 ;
        RECT  103.596 44.016 103.68 44.04 ;
    END
  END o_data[78]
  PIN o_data[79]
    DIRECTION OUTPUT ;
    USE SIGNAL ;
    PORT
      LAYER M4 ;
        RECT  103.596 44.448 103.68 44.472 ;
    END
  END o_data[79]
  PIN o_data[7]
    DIRECTION OUTPUT ;
    USE SIGNAL ;
    PORT
      LAYER M4 ;
        RECT  103.596 13.344 103.68 13.368 ;
    END
  END o_data[7]
  PIN o_data[80]
    DIRECTION OUTPUT ;
    USE SIGNAL ;
    PORT
      LAYER M4 ;
        RECT  103.596 44.88 103.68 44.904 ;
    END
  END o_data[80]
  PIN o_data[81]
    DIRECTION OUTPUT ;
    USE SIGNAL ;
    PORT
      LAYER M4 ;
        RECT  103.596 45.312 103.68 45.336 ;
    END
  END o_data[81]
  PIN o_data[82]
    DIRECTION OUTPUT ;
    USE SIGNAL ;
    PORT
      LAYER M4 ;
        RECT  103.596 45.744 103.68 45.768 ;
    END
  END o_data[82]
  PIN o_data[83]
    DIRECTION OUTPUT ;
    USE SIGNAL ;
    PORT
      LAYER M4 ;
        RECT  103.596 46.176 103.68 46.2 ;
    END
  END o_data[83]
  PIN o_data[84]
    DIRECTION OUTPUT ;
    USE SIGNAL ;
    PORT
      LAYER M4 ;
        RECT  103.596 46.608 103.68 46.632 ;
    END
  END o_data[84]
  PIN o_data[85]
    DIRECTION OUTPUT ;
    USE SIGNAL ;
    PORT
      LAYER M4 ;
        RECT  103.596 47.04 103.68 47.064 ;
    END
  END o_data[85]
  PIN o_data[86]
    DIRECTION OUTPUT ;
    USE SIGNAL ;
    PORT
      LAYER M4 ;
        RECT  103.596 47.472 103.68 47.496 ;
    END
  END o_data[86]
  PIN o_data[87]
    DIRECTION OUTPUT ;
    USE SIGNAL ;
    PORT
      LAYER M4 ;
        RECT  103.596 47.904 103.68 47.928 ;
    END
  END o_data[87]
  PIN o_data[88]
    DIRECTION OUTPUT ;
    USE SIGNAL ;
    PORT
      LAYER M4 ;
        RECT  103.596 48.336 103.68 48.36 ;
    END
  END o_data[88]
  PIN o_data[89]
    DIRECTION OUTPUT ;
    USE SIGNAL ;
    PORT
      LAYER M4 ;
        RECT  103.596 48.768 103.68 48.792 ;
    END
  END o_data[89]
  PIN o_data[8]
    DIRECTION OUTPUT ;
    USE SIGNAL ;
    PORT
      LAYER M4 ;
        RECT  103.596 13.776 103.68 13.8 ;
    END
  END o_data[8]
  PIN o_data[90]
    DIRECTION OUTPUT ;
    USE SIGNAL ;
    PORT
      LAYER M4 ;
        RECT  103.596 49.2 103.68 49.224 ;
    END
  END o_data[90]
  PIN o_data[91]
    DIRECTION OUTPUT ;
    USE SIGNAL ;
    PORT
      LAYER M4 ;
        RECT  103.596 49.632 103.68 49.656 ;
    END
  END o_data[91]
  PIN o_data[92]
    DIRECTION OUTPUT ;
    USE SIGNAL ;
    PORT
      LAYER M4 ;
        RECT  103.596 50.064 103.68 50.088 ;
    END
  END o_data[92]
  PIN o_data[93]
    DIRECTION OUTPUT ;
    USE SIGNAL ;
    PORT
      LAYER M4 ;
        RECT  103.596 50.496 103.68 50.52 ;
    END
  END o_data[93]
  PIN o_data[94]
    DIRECTION OUTPUT ;
    USE SIGNAL ;
    PORT
      LAYER M4 ;
        RECT  103.596 50.928 103.68 50.952 ;
    END
  END o_data[94]
  PIN o_data[95]
    DIRECTION OUTPUT ;
    USE SIGNAL ;
    PORT
      LAYER M4 ;
        RECT  103.596 51.36 103.68 51.384 ;
    END
  END o_data[95]
  PIN o_data[96]
    DIRECTION OUTPUT ;
    USE SIGNAL ;
    PORT
      LAYER M4 ;
        RECT  103.596 51.792 103.68 51.816 ;
    END
  END o_data[96]
  PIN o_data[97]
    DIRECTION OUTPUT ;
    USE SIGNAL ;
    PORT
      LAYER M4 ;
        RECT  103.596 52.224 103.68 52.248 ;
    END
  END o_data[97]
  PIN o_data[98]
    DIRECTION OUTPUT ;
    USE SIGNAL ;
    PORT
      LAYER M4 ;
        RECT  103.596 52.656 103.68 52.68 ;
    END
  END o_data[98]
  PIN o_data[99]
    DIRECTION OUTPUT ;
    USE SIGNAL ;
    PORT
      LAYER M4 ;
        RECT  103.596 53.088 103.68 53.112 ;
    END
  END o_data[99]
  PIN o_data[9]
    DIRECTION OUTPUT ;
    USE SIGNAL ;
    PORT
      LAYER M4 ;
        RECT  103.596 14.208 103.68 14.232 ;
    END
  END o_data[9]
  PIN o_partial_valid[0]
    DIRECTION OUTPUT ;
    USE SIGNAL ;
    PORT
      LAYER M4 ;
        RECT  103.596 8.592 103.68 8.616 ;
    END
  END o_partial_valid[0]
  PIN o_partial_valid[1]
    DIRECTION OUTPUT ;
    USE SIGNAL ;
    PORT
      LAYER M4 ;
        RECT  103.596 9.024 103.68 9.048 ;
    END
  END o_partial_valid[1]
  PIN o_partial_valid[2]
    DIRECTION OUTPUT ;
    USE SIGNAL ;
    PORT
      LAYER M4 ;
        RECT  103.596 9.456 103.68 9.48 ;
    END
  END o_partial_valid[2]
  PIN o_partial_valid[3]
    DIRECTION OUTPUT ;
    USE SIGNAL ;
    PORT
      LAYER M4 ;
        RECT  103.596 9.888 103.68 9.912 ;
    END
  END o_partial_valid[3]
  PIN rst_n
    DIRECTION INPUT ;
    USE SIGNAL ;
    PORT
      LAYER M5 ;
        RECT  52.032 129.516 52.056 129.6 ;
    END
  END rst_n
  PIN VDD
    DIRECTION INOUT ;
    USE POWER ;
    PORT
      LAYER M5 ;
        RECT  99.792 2.151 99.912 127.449 ;
        RECT  94.392 2.151 94.512 127.449 ;
        RECT  88.992 2.151 89.112 127.449 ;
        RECT  83.592 2.151 83.712 127.449 ;
        RECT  78.192 2.151 78.312 127.449 ;
        RECT  72.792 2.151 72.912 127.449 ;
        RECT  67.392 2.151 67.512 127.449 ;
        RECT  61.992 2.151 62.112 127.449 ;
        RECT  56.592 2.151 56.712 127.449 ;
        RECT  51.192 2.151 51.312 127.449 ;
        RECT  45.792 2.151 45.912 127.449 ;
        RECT  40.392 2.151 40.512 127.449 ;
        RECT  34.992 2.151 35.112 127.449 ;
        RECT  29.592 2.151 29.712 127.449 ;
        RECT  24.192 2.151 24.312 127.449 ;
        RECT  18.792 2.151 18.912 127.449 ;
        RECT  13.392 2.151 13.512 127.449 ;
        RECT  7.992 2.151 8.112 127.449 ;
        RECT  2.592 2.151 2.712 127.449 ;
    END
  END VDD
  PIN VSS
    DIRECTION INOUT ;
    USE GROUND ;
    PORT
      LAYER M5 ;
        RECT  99.6 2.137 99.72 127.463 ;
        RECT  94.2 2.137 94.32 127.463 ;
        RECT  88.8 2.137 88.92 127.463 ;
        RECT  83.4 2.137 83.52 127.463 ;
        RECT  78 2.137 78.12 127.463 ;
        RECT  72.6 2.137 72.72 127.463 ;
        RECT  67.2 2.137 67.32 127.463 ;
        RECT  61.8 2.137 61.92 127.463 ;
        RECT  56.4 2.137 56.52 127.463 ;
        RECT  51 2.137 51.12 127.463 ;
        RECT  45.6 2.137 45.72 127.463 ;
        RECT  40.2 2.137 40.32 127.463 ;
        RECT  34.8 2.137 34.92 127.463 ;
        RECT  29.4 2.137 29.52 127.463 ;
        RECT  24 2.137 24.12 127.463 ;
        RECT  18.6 2.137 18.72 127.463 ;
        RECT  13.2 2.137 13.32 127.463 ;
        RECT  7.8 2.137 7.92 127.463 ;
        RECT  2.4 2.137 2.52 127.463 ;
    END
  END VSS
  # OT_OBS_CLOSED layer=M5 d_um=1.536 added=92
  OBS
    LAYER RVTN ;
     RECT  2.16 2.16 101.52 2.295 ;
     RECT  2.16 2.565 101.52 2.835 ;
     RECT  2.16 3.105 101.52 3.375 ;
     RECT  2.16 3.645 101.52 3.915 ;
     RECT  2.16 4.185 101.52 4.455 ;
     RECT  2.16 4.725 101.52 4.995 ;
     RECT  2.16 5.265 101.52 5.535 ;
     RECT  2.16 5.805 101.52 6.075 ;
     RECT  2.16 6.345 101.52 6.615 ;
     RECT  2.16 6.885 101.52 7.155 ;
     RECT  2.16 7.425 101.52 7.695 ;
     RECT  2.16 7.965 101.52 8.235 ;
     RECT  2.16 8.505 101.52 8.775 ;
     RECT  2.16 9.045 101.52 9.315 ;
     RECT  2.16 9.585 101.52 9.855 ;
     RECT  2.16 10.125 101.52 10.395 ;
     RECT  2.16 10.665 101.52 10.935 ;
     RECT  2.16 11.205 101.52 11.475 ;
     RECT  2.16 11.745 101.52 12.015 ;
     RECT  2.16 12.285 101.52 12.555 ;
     RECT  2.16 12.825 101.52 13.095 ;
     RECT  2.16 13.365 101.52 13.635 ;
     RECT  2.16 13.905 101.52 14.175 ;
     RECT  2.16 14.445 101.52 14.715 ;
     RECT  2.16 14.985 101.52 15.255 ;
     RECT  2.16 15.525 101.52 15.795 ;
     RECT  2.16 16.065 101.52 16.335 ;
     RECT  2.16 16.605 101.52 16.875 ;
     RECT  2.16 17.145 101.52 17.415 ;
     RECT  2.16 17.685 101.52 17.955 ;
     RECT  2.16 18.225 101.52 18.495 ;
     RECT  2.16 18.765 101.52 19.035 ;
     RECT  2.16 19.305 101.52 19.575 ;
     RECT  2.16 19.845 101.52 20.115 ;
     RECT  2.16 20.385 101.52 20.655 ;
     RECT  2.16 20.925 101.52 21.195 ;
     RECT  2.16 21.465 101.52 21.735 ;
     RECT  2.16 22.005 101.52 22.275 ;
     RECT  2.16 22.545 101.52 22.815 ;
     RECT  2.16 23.085 101.52 23.355 ;
     RECT  2.16 23.625 101.52 23.895 ;
     RECT  2.16 24.165 101.52 24.435 ;
     RECT  2.16 24.705 101.52 24.975 ;
     RECT  2.16 25.245 101.52 25.515 ;
     RECT  2.16 25.785 101.52 26.055 ;
     RECT  2.16 26.325 101.52 26.595 ;
     RECT  2.16 26.865 101.52 27.135 ;
     RECT  2.16 27.405 101.52 27.675 ;
     RECT  2.16 27.945 101.52 28.215 ;
     RECT  2.16 28.485 101.52 28.755 ;
     RECT  2.16 29.025 101.52 29.295 ;
     RECT  2.16 29.565 101.52 29.835 ;
     RECT  2.16 30.105 101.52 30.375 ;
     RECT  2.16 30.645 101.52 30.915 ;
     RECT  2.16 31.185 101.52 31.455 ;
     RECT  2.16 31.725 101.52 31.995 ;
     RECT  2.16 32.265 101.52 32.535 ;
     RECT  2.16 32.805 101.52 33.075 ;
     RECT  2.16 33.345 101.52 33.615 ;
     RECT  2.16 33.885 101.52 34.155 ;
     RECT  2.16 34.425 101.52 34.695 ;
     RECT  2.16 34.965 101.52 35.235 ;
     RECT  2.16 35.505 101.52 35.775 ;
     RECT  2.16 36.045 101.52 36.315 ;
     RECT  2.16 36.585 101.52 36.855 ;
     RECT  2.16 37.125 101.52 37.395 ;
     RECT  2.16 37.665 101.52 37.935 ;
     RECT  2.16 38.205 101.52 38.475 ;
     RECT  2.16 38.745 101.52 39.015 ;
     RECT  2.16 39.285 101.52 39.555 ;
     RECT  2.16 39.825 101.52 40.095 ;
     RECT  2.16 40.365 101.52 40.635 ;
     RECT  2.16 40.905 101.52 41.175 ;
     RECT  2.16 41.445 101.52 41.715 ;
     RECT  2.16 41.985 101.52 42.255 ;
     RECT  2.16 42.525 101.52 42.795 ;
     RECT  2.16 43.065 101.52 43.335 ;
     RECT  2.16 43.605 101.52 43.875 ;
     RECT  2.16 44.145 101.52 44.415 ;
     RECT  2.16 44.685 101.52 44.955 ;
     RECT  2.16 45.225 101.52 45.495 ;
     RECT  2.16 45.765 101.52 46.035 ;
     RECT  2.16 46.305 101.52 46.575 ;
     RECT  2.16 46.845 101.52 47.115 ;
     RECT  2.16 47.385 101.52 47.655 ;
     RECT  2.16 47.925 101.52 48.195 ;
     RECT  2.16 48.465 101.52 48.735 ;
     RECT  2.16 49.005 101.52 49.275 ;
     RECT  2.16 49.545 101.52 49.815 ;
     RECT  2.16 50.085 101.52 50.355 ;
     RECT  2.16 50.625 101.52 50.895 ;
     RECT  2.16 51.165 101.52 51.435 ;
     RECT  2.16 51.705 101.52 51.975 ;
     RECT  2.16 52.245 101.52 52.515 ;
     RECT  2.16 52.785 101.52 53.055 ;
     RECT  2.16 53.325 101.52 53.595 ;
     RECT  2.16 53.865 101.52 54.135 ;
     RECT  2.16 54.405 101.52 54.675 ;
     RECT  2.16 54.945 101.52 55.215 ;
     RECT  2.16 55.485 101.52 55.755 ;
     RECT  2.16 56.025 101.52 56.295 ;
     RECT  2.16 56.565 101.52 56.835 ;
     RECT  2.16 57.105 101.52 57.375 ;
     RECT  2.16 57.645 101.52 57.915 ;
     RECT  2.16 58.185 101.52 58.455 ;
     RECT  2.16 58.725 101.52 58.995 ;
     RECT  2.16 59.265 101.52 59.535 ;
     RECT  2.16 59.805 101.52 60.075 ;
     RECT  2.16 60.345 101.52 60.615 ;
     RECT  2.16 60.885 101.52 61.155 ;
     RECT  2.16 61.425 101.52 61.695 ;
     RECT  2.16 61.965 101.52 62.235 ;
     RECT  2.16 62.505 101.52 62.775 ;
     RECT  2.16 63.045 101.52 63.315 ;
     RECT  2.16 63.585 101.52 63.855 ;
     RECT  2.16 64.125 101.52 64.395 ;
     RECT  2.16 64.665 101.52 64.935 ;
     RECT  2.16 65.205 101.52 65.475 ;
     RECT  2.16 65.745 101.52 66.015 ;
     RECT  2.16 66.285 101.52 66.555 ;
     RECT  2.16 66.825 101.52 67.095 ;
     RECT  2.16 67.365 101.52 67.635 ;
     RECT  2.16 67.905 101.52 68.175 ;
     RECT  2.16 68.445 101.52 68.715 ;
     RECT  2.16 68.985 101.52 69.255 ;
     RECT  2.16 69.525 101.52 69.795 ;
     RECT  2.16 70.065 101.52 70.335 ;
     RECT  2.16 70.605 101.52 70.875 ;
     RECT  2.16 71.145 101.52 71.415 ;
     RECT  2.16 71.685 101.52 71.955 ;
     RECT  2.16 72.225 101.52 72.495 ;
     RECT  2.16 72.765 101.52 73.035 ;
     RECT  2.16 73.305 101.52 73.575 ;
     RECT  2.16 73.845 101.52 74.115 ;
     RECT  2.16 74.385 101.52 74.655 ;
     RECT  2.16 74.925 101.52 75.195 ;
     RECT  2.16 75.465 101.52 75.735 ;
     RECT  2.16 76.005 101.52 76.275 ;
     RECT  2.16 76.545 101.52 76.815 ;
     RECT  2.16 77.085 101.52 77.355 ;
     RECT  2.16 77.625 101.52 77.895 ;
     RECT  2.16 78.165 101.52 78.435 ;
     RECT  2.16 78.705 101.52 78.975 ;
     RECT  2.16 79.245 101.52 79.515 ;
     RECT  2.16 79.785 101.52 80.055 ;
     RECT  2.16 80.325 101.52 80.595 ;
     RECT  2.16 80.865 101.52 81.135 ;
     RECT  2.16 81.405 101.52 81.675 ;
     RECT  2.16 81.945 101.52 82.215 ;
     RECT  2.16 82.485 101.52 82.755 ;
     RECT  2.16 83.025 101.52 83.295 ;
     RECT  2.16 83.565 101.52 83.835 ;
     RECT  2.16 84.105 101.52 84.375 ;
     RECT  2.16 84.645 101.52 84.915 ;
     RECT  2.16 85.185 101.52 85.455 ;
     RECT  2.16 85.725 101.52 85.995 ;
     RECT  2.16 86.265 101.52 86.535 ;
     RECT  2.16 86.805 101.52 87.075 ;
     RECT  2.16 87.345 101.52 87.615 ;
     RECT  2.16 87.885 101.52 88.155 ;
     RECT  2.16 88.425 101.52 88.695 ;
     RECT  2.16 88.965 101.52 89.235 ;
     RECT  2.16 89.505 101.52 89.775 ;
     RECT  2.16 90.045 101.52 90.315 ;
     RECT  2.16 90.585 101.52 90.855 ;
     RECT  2.16 91.125 101.52 91.395 ;
     RECT  2.16 91.665 101.52 91.935 ;
     RECT  2.16 92.205 101.52 92.475 ;
     RECT  2.16 92.745 101.52 93.015 ;
     RECT  2.16 93.285 101.52 93.555 ;
     RECT  2.16 93.825 101.52 94.095 ;
     RECT  2.16 94.365 101.52 94.635 ;
     RECT  2.16 94.905 101.52 95.175 ;
     RECT  2.16 95.445 101.52 95.715 ;
     RECT  2.16 95.985 101.52 96.255 ;
     RECT  2.16 96.525 101.52 96.795 ;
     RECT  2.16 97.065 101.52 97.335 ;
     RECT  2.16 97.605 101.52 97.875 ;
     RECT  2.16 98.145 101.52 98.415 ;
     RECT  2.16 98.685 101.52 98.955 ;
     RECT  2.16 99.225 101.52 99.495 ;
     RECT  2.16 99.765 101.52 100.035 ;
     RECT  2.16 100.305 101.52 100.575 ;
     RECT  2.16 100.845 101.52 101.115 ;
     RECT  2.16 101.385 101.52 101.655 ;
     RECT  2.16 101.925 101.52 102.195 ;
     RECT  2.16 102.465 101.52 102.735 ;
     RECT  2.16 103.005 101.52 103.275 ;
     RECT  2.16 103.545 101.52 103.815 ;
     RECT  2.16 104.085 101.52 104.355 ;
     RECT  2.16 104.625 101.52 104.895 ;
     RECT  2.16 105.165 101.52 105.435 ;
     RECT  2.16 105.705 101.52 105.975 ;
     RECT  2.16 106.245 101.52 106.515 ;
     RECT  2.16 106.785 101.52 107.055 ;
     RECT  2.16 107.325 101.52 107.595 ;
     RECT  2.16 107.865 101.52 108.135 ;
     RECT  2.16 108.405 101.52 108.675 ;
     RECT  2.16 108.945 101.52 109.215 ;
     RECT  2.16 109.485 101.52 109.755 ;
     RECT  2.16 110.025 101.52 110.295 ;
     RECT  2.16 110.565 101.52 110.835 ;
     RECT  2.16 111.105 101.52 111.375 ;
     RECT  2.16 111.645 101.52 111.915 ;
     RECT  2.16 112.185 101.52 112.455 ;
     RECT  2.16 112.725 101.52 112.995 ;
     RECT  2.16 113.265 101.52 113.535 ;
     RECT  2.16 113.805 101.52 114.075 ;
     RECT  2.16 114.345 101.52 114.615 ;
     RECT  2.16 114.885 101.52 115.155 ;
     RECT  2.16 115.425 101.52 115.695 ;
     RECT  2.16 115.965 101.52 116.235 ;
     RECT  2.16 116.505 101.52 116.775 ;
     RECT  2.16 117.045 101.52 117.315 ;
     RECT  2.16 117.585 101.52 117.855 ;
     RECT  2.16 118.125 101.52 118.395 ;
     RECT  2.16 118.665 101.52 118.935 ;
     RECT  2.16 119.205 101.52 119.475 ;
     RECT  2.16 119.745 101.52 120.015 ;
     RECT  2.16 120.285 101.52 120.555 ;
     RECT  2.16 120.825 101.52 121.095 ;
     RECT  2.16 121.365 101.52 121.635 ;
     RECT  2.16 121.905 101.52 122.175 ;
     RECT  2.16 122.445 101.52 122.715 ;
     RECT  2.16 122.985 101.52 123.255 ;
     RECT  2.16 123.525 101.52 123.795 ;
     RECT  2.16 124.065 101.52 124.335 ;
     RECT  2.16 124.605 101.52 124.875 ;
     RECT  2.16 125.145 101.52 125.415 ;
     RECT  2.16 125.685 101.52 125.955 ;
     RECT  2.16 126.225 101.52 126.495 ;
     RECT  2.16 126.765 101.52 127.035 ;
     RECT  2.16 127.305 101.52 127.44 ;
    LAYER RVTP ;
     RECT  2.16 2.295 101.52 2.565 ;
     RECT  2.16 2.835 101.52 3.105 ;
     RECT  2.16 3.375 101.52 3.645 ;
     RECT  2.16 3.915 101.52 4.185 ;
     RECT  2.16 4.455 101.52 4.725 ;
     RECT  2.16 4.995 101.52 5.265 ;
     RECT  2.16 5.535 101.52 5.805 ;
     RECT  2.16 6.075 101.52 6.345 ;
     RECT  2.16 6.615 101.52 6.885 ;
     RECT  2.16 7.155 101.52 7.425 ;
     RECT  2.16 7.695 101.52 7.965 ;
     RECT  2.16 8.235 101.52 8.505 ;
     RECT  2.16 8.775 101.52 9.045 ;
     RECT  2.16 9.315 101.52 9.585 ;
     RECT  2.16 9.855 101.52 10.125 ;
     RECT  2.16 10.395 101.52 10.665 ;
     RECT  2.16 10.935 101.52 11.205 ;
     RECT  2.16 11.475 101.52 11.745 ;
     RECT  2.16 12.015 101.52 12.285 ;
     RECT  2.16 12.555 101.52 12.825 ;
     RECT  2.16 13.095 101.52 13.365 ;
     RECT  2.16 13.635 101.52 13.905 ;
     RECT  2.16 14.175 101.52 14.445 ;
     RECT  2.16 14.715 101.52 14.985 ;
     RECT  2.16 15.255 101.52 15.525 ;
     RECT  2.16 15.795 101.52 16.065 ;
     RECT  2.16 16.335 101.52 16.605 ;
     RECT  2.16 16.875 101.52 17.145 ;
     RECT  2.16 17.415 101.52 17.685 ;
     RECT  2.16 17.955 101.52 18.225 ;
     RECT  2.16 18.495 101.52 18.765 ;
     RECT  2.16 19.035 101.52 19.305 ;
     RECT  2.16 19.575 101.52 19.845 ;
     RECT  2.16 20.115 101.52 20.385 ;
     RECT  2.16 20.655 101.52 20.925 ;
     RECT  2.16 21.195 101.52 21.465 ;
     RECT  2.16 21.735 101.52 22.005 ;
     RECT  2.16 22.275 101.52 22.545 ;
     RECT  2.16 22.815 101.52 23.085 ;
     RECT  2.16 23.355 101.52 23.625 ;
     RECT  2.16 23.895 101.52 24.165 ;
     RECT  2.16 24.435 101.52 24.705 ;
     RECT  2.16 24.975 101.52 25.245 ;
     RECT  2.16 25.515 101.52 25.785 ;
     RECT  2.16 26.055 101.52 26.325 ;
     RECT  2.16 26.595 101.52 26.865 ;
     RECT  2.16 27.135 101.52 27.405 ;
     RECT  2.16 27.675 101.52 27.945 ;
     RECT  2.16 28.215 101.52 28.485 ;
     RECT  2.16 28.755 101.52 29.025 ;
     RECT  2.16 29.295 101.52 29.565 ;
     RECT  2.16 29.835 101.52 30.105 ;
     RECT  2.16 30.375 101.52 30.645 ;
     RECT  2.16 30.915 101.52 31.185 ;
     RECT  2.16 31.455 101.52 31.725 ;
     RECT  2.16 31.995 101.52 32.265 ;
     RECT  2.16 32.535 101.52 32.805 ;
     RECT  2.16 33.075 101.52 33.345 ;
     RECT  2.16 33.615 101.52 33.885 ;
     RECT  2.16 34.155 101.52 34.425 ;
     RECT  2.16 34.695 101.52 34.965 ;
     RECT  2.16 35.235 101.52 35.505 ;
     RECT  2.16 35.775 101.52 36.045 ;
     RECT  2.16 36.315 101.52 36.585 ;
     RECT  2.16 36.855 101.52 37.125 ;
     RECT  2.16 37.395 101.52 37.665 ;
     RECT  2.16 37.935 101.52 38.205 ;
     RECT  2.16 38.475 101.52 38.745 ;
     RECT  2.16 39.015 101.52 39.285 ;
     RECT  2.16 39.555 101.52 39.825 ;
     RECT  2.16 40.095 101.52 40.365 ;
     RECT  2.16 40.635 101.52 40.905 ;
     RECT  2.16 41.175 101.52 41.445 ;
     RECT  2.16 41.715 101.52 41.985 ;
     RECT  2.16 42.255 101.52 42.525 ;
     RECT  2.16 42.795 101.52 43.065 ;
     RECT  2.16 43.335 101.52 43.605 ;
     RECT  2.16 43.875 101.52 44.145 ;
     RECT  2.16 44.415 101.52 44.685 ;
     RECT  2.16 44.955 101.52 45.225 ;
     RECT  2.16 45.495 101.52 45.765 ;
     RECT  2.16 46.035 101.52 46.305 ;
     RECT  2.16 46.575 101.52 46.845 ;
     RECT  2.16 47.115 101.52 47.385 ;
     RECT  2.16 47.655 101.52 47.925 ;
     RECT  2.16 48.195 101.52 48.465 ;
     RECT  2.16 48.735 101.52 49.005 ;
     RECT  2.16 49.275 101.52 49.545 ;
     RECT  2.16 49.815 101.52 50.085 ;
     RECT  2.16 50.355 101.52 50.625 ;
     RECT  2.16 50.895 101.52 51.165 ;
     RECT  2.16 51.435 101.52 51.705 ;
     RECT  2.16 51.975 101.52 52.245 ;
     RECT  2.16 52.515 101.52 52.785 ;
     RECT  2.16 53.055 101.52 53.325 ;
     RECT  2.16 53.595 101.52 53.865 ;
     RECT  2.16 54.135 101.52 54.405 ;
     RECT  2.16 54.675 101.52 54.945 ;
     RECT  2.16 55.215 101.52 55.485 ;
     RECT  2.16 55.755 101.52 56.025 ;
     RECT  2.16 56.295 101.52 56.565 ;
     RECT  2.16 56.835 101.52 57.105 ;
     RECT  2.16 57.375 101.52 57.645 ;
     RECT  2.16 57.915 101.52 58.185 ;
     RECT  2.16 58.455 101.52 58.725 ;
     RECT  2.16 58.995 101.52 59.265 ;
     RECT  2.16 59.535 101.52 59.805 ;
     RECT  2.16 60.075 101.52 60.345 ;
     RECT  2.16 60.615 101.52 60.885 ;
     RECT  2.16 61.155 101.52 61.425 ;
     RECT  2.16 61.695 101.52 61.965 ;
     RECT  2.16 62.235 101.52 62.505 ;
     RECT  2.16 62.775 101.52 63.045 ;
     RECT  2.16 63.315 101.52 63.585 ;
     RECT  2.16 63.855 101.52 64.125 ;
     RECT  2.16 64.395 101.52 64.665 ;
     RECT  2.16 64.935 101.52 65.205 ;
     RECT  2.16 65.475 101.52 65.745 ;
     RECT  2.16 66.015 101.52 66.285 ;
     RECT  2.16 66.555 101.52 66.825 ;
     RECT  2.16 67.095 101.52 67.365 ;
     RECT  2.16 67.635 101.52 67.905 ;
     RECT  2.16 68.175 101.52 68.445 ;
     RECT  2.16 68.715 101.52 68.985 ;
     RECT  2.16 69.255 101.52 69.525 ;
     RECT  2.16 69.795 101.52 70.065 ;
     RECT  2.16 70.335 101.52 70.605 ;
     RECT  2.16 70.875 101.52 71.145 ;
     RECT  2.16 71.415 101.52 71.685 ;
     RECT  2.16 71.955 101.52 72.225 ;
     RECT  2.16 72.495 101.52 72.765 ;
     RECT  2.16 73.035 101.52 73.305 ;
     RECT  2.16 73.575 101.52 73.845 ;
     RECT  2.16 74.115 101.52 74.385 ;
     RECT  2.16 74.655 101.52 74.925 ;
     RECT  2.16 75.195 101.52 75.465 ;
     RECT  2.16 75.735 101.52 76.005 ;
     RECT  2.16 76.275 101.52 76.545 ;
     RECT  2.16 76.815 101.52 77.085 ;
     RECT  2.16 77.355 101.52 77.625 ;
     RECT  2.16 77.895 101.52 78.165 ;
     RECT  2.16 78.435 101.52 78.705 ;
     RECT  2.16 78.975 101.52 79.245 ;
     RECT  2.16 79.515 101.52 79.785 ;
     RECT  2.16 80.055 101.52 80.325 ;
     RECT  2.16 80.595 101.52 80.865 ;
     RECT  2.16 81.135 101.52 81.405 ;
     RECT  2.16 81.675 101.52 81.945 ;
     RECT  2.16 82.215 101.52 82.485 ;
     RECT  2.16 82.755 101.52 83.025 ;
     RECT  2.16 83.295 101.52 83.565 ;
     RECT  2.16 83.835 101.52 84.105 ;
     RECT  2.16 84.375 101.52 84.645 ;
     RECT  2.16 84.915 101.52 85.185 ;
     RECT  2.16 85.455 101.52 85.725 ;
     RECT  2.16 85.995 101.52 86.265 ;
     RECT  2.16 86.535 101.52 86.805 ;
     RECT  2.16 87.075 101.52 87.345 ;
     RECT  2.16 87.615 101.52 87.885 ;
     RECT  2.16 88.155 101.52 88.425 ;
     RECT  2.16 88.695 101.52 88.965 ;
     RECT  2.16 89.235 101.52 89.505 ;
     RECT  2.16 89.775 101.52 90.045 ;
     RECT  2.16 90.315 101.52 90.585 ;
     RECT  2.16 90.855 101.52 91.125 ;
     RECT  2.16 91.395 101.52 91.665 ;
     RECT  2.16 91.935 101.52 92.205 ;
     RECT  2.16 92.475 101.52 92.745 ;
     RECT  2.16 93.015 101.52 93.285 ;
     RECT  2.16 93.555 101.52 93.825 ;
     RECT  2.16 94.095 101.52 94.365 ;
     RECT  2.16 94.635 101.52 94.905 ;
     RECT  2.16 95.175 101.52 95.445 ;
     RECT  2.16 95.715 101.52 95.985 ;
     RECT  2.16 96.255 101.52 96.525 ;
     RECT  2.16 96.795 101.52 97.065 ;
     RECT  2.16 97.335 101.52 97.605 ;
     RECT  2.16 97.875 101.52 98.145 ;
     RECT  2.16 98.415 101.52 98.685 ;
     RECT  2.16 98.955 101.52 99.225 ;
     RECT  2.16 99.495 101.52 99.765 ;
     RECT  2.16 100.035 101.52 100.305 ;
     RECT  2.16 100.575 101.52 100.845 ;
     RECT  2.16 101.115 101.52 101.385 ;
     RECT  2.16 101.655 101.52 101.925 ;
     RECT  2.16 102.195 101.52 102.465 ;
     RECT  2.16 102.735 101.52 103.005 ;
     RECT  2.16 103.275 101.52 103.545 ;
     RECT  2.16 103.815 101.52 104.085 ;
     RECT  2.16 104.355 101.52 104.625 ;
     RECT  2.16 104.895 101.52 105.165 ;
     RECT  2.16 105.435 101.52 105.705 ;
     RECT  2.16 105.975 101.52 106.245 ;
     RECT  2.16 106.515 101.52 106.785 ;
     RECT  2.16 107.055 101.52 107.325 ;
     RECT  2.16 107.595 101.52 107.865 ;
     RECT  2.16 108.135 101.52 108.405 ;
     RECT  2.16 108.675 101.52 108.945 ;
     RECT  2.16 109.215 101.52 109.485 ;
     RECT  2.16 109.755 101.52 110.025 ;
     RECT  2.16 110.295 101.52 110.565 ;
     RECT  2.16 110.835 101.52 111.105 ;
     RECT  2.16 111.375 101.52 111.645 ;
     RECT  2.16 111.915 101.52 112.185 ;
     RECT  2.16 112.455 101.52 112.725 ;
     RECT  2.16 112.995 101.52 113.265 ;
     RECT  2.16 113.535 101.52 113.805 ;
     RECT  2.16 114.075 101.52 114.345 ;
     RECT  2.16 114.615 101.52 114.885 ;
     RECT  2.16 115.155 101.52 115.425 ;
     RECT  2.16 115.695 101.52 115.965 ;
     RECT  2.16 116.235 101.52 116.505 ;
     RECT  2.16 116.775 101.52 117.045 ;
     RECT  2.16 117.315 101.52 117.585 ;
     RECT  2.16 117.855 101.52 118.125 ;
     RECT  2.16 118.395 101.52 118.665 ;
     RECT  2.16 118.935 101.52 119.205 ;
     RECT  2.16 119.475 101.52 119.745 ;
     RECT  2.16 120.015 101.52 120.285 ;
     RECT  2.16 120.555 101.52 120.825 ;
     RECT  2.16 121.095 101.52 121.365 ;
     RECT  2.16 121.635 101.52 121.905 ;
     RECT  2.16 122.175 101.52 122.445 ;
     RECT  2.16 122.715 101.52 122.985 ;
     RECT  2.16 123.255 101.52 123.525 ;
     RECT  2.16 123.795 101.52 124.065 ;
     RECT  2.16 124.335 101.52 124.605 ;
     RECT  2.16 124.875 101.52 125.145 ;
     RECT  2.16 125.415 101.52 125.685 ;
     RECT  2.16 125.955 101.52 126.225 ;
     RECT  2.16 126.495 101.52 126.765 ;
     RECT  2.16 127.035 101.52 127.305 ;
    LAYER M1 ;
     RECT  2.16 2.151 101.52 127.449 ;
    LAYER M2 ;
     RECT  0.535 13.068 2.16 13.086 ;
     RECT  0.103 22.212 2.16 22.23 ;
     RECT  0.535 27.342 2.16 27.36 ;
     RECT  0.535 38.178 2.16 38.196 ;
     RECT  0.535 43.272 2.16 43.29 ;
     RECT  0.103 48.942 2.16 48.96 ;
     RECT  0.103 54.072 2.16 54.09 ;
     RECT  0.535 63.252 2.16 63.27 ;
     RECT  0.103 64.944 2.16 64.962 ;
     RECT  0.103 68.382 2.16 68.4 ;
     RECT  0.535 73.512 2.16 73.53 ;
     RECT  0.103 79.218 2.16 79.236 ;
     RECT  0.103 90.018 2.16 90.036 ;
     RECT  0.103 95.148 2.16 95.166 ;
     RECT  0.103 104.292 2.16 104.31 ;
     RECT  0.103 109.422 2.16 109.44 ;
     RECT  0.103 114.552 2.16 114.57 ;
     RECT  0.103 119.52 2.16 120.546 ;
     RECT  0.103 121.302 2.16 121.32 ;
     RECT  2.16 2.151 101.52 127.449 ;
     RECT  101.52 113.076 101.615 118.044 ;
     RECT  101.52 36.216 101.651 40.284 ;
     RECT  101.52 41.076 101.723 42.444 ;
     RECT  101.52 44.856 101.723 49.734 ;
     RECT  101.52 17.856 102.011 20.304 ;
     RECT  101.52 25.956 102.011 33.606 ;
     RECT  101.52 108.036 102.011 112.284 ;
     RECT  102.011 28.458 102.047 33.606 ;
     RECT  101.52 62.136 102.047 66.204 ;
     RECT  101.52 71.316 102.047 74.844 ;
     RECT  101.52 77.706 102.047 81.324 ;
     RECT  101.52 92.916 102.047 96.444 ;
     RECT  101.52 99.396 102.047 104.544 ;
     RECT  101.52 105.336 102.047 107.118 ;
     RECT  102.011 111.852 102.047 112.284 ;
     RECT  101.615 113.166 102.047 118.044 ;
     RECT  101.52 55.692 102.515 61.344 ;
     RECT  101.52 23.796 102.551 25.164 ;
     RECT  102.011 25.956 102.551 27.63 ;
     RECT  101.52 34.506 102.551 35.424 ;
     RECT  101.723 41.076 102.551 41.634 ;
     RECT  101.52 43.236 102.551 44.064 ;
     RECT  102.047 62.946 102.551 66.204 ;
     RECT  101.52 66.996 102.551 70.524 ;
     RECT  102.047 71.316 102.551 71.604 ;
     RECT  101.52 82.116 102.551 82.944 ;
     RECT  101.52 86.436 102.551 87.678 ;
     RECT  101.52 88.596 102.551 92.124 ;
     RECT  102.047 92.916 102.551 94.284 ;
     RECT  101.52 97.236 102.551 98.604 ;
     RECT  102.047 106.146 102.551 107.118 ;
     RECT  102.011 108.036 102.551 111.024 ;
     RECT  101.52 118.836 102.551 120.204 ;
     RECT  101.52 121.266 102.551 121.554 ;
     RECT  101.52 8.514 102.587 17.064 ;
     RECT  102.011 18.126 102.587 20.304 ;
     RECT  101.52 21.366 102.587 22.194 ;
     RECT  101.52 22.986 102.587 23.004 ;
     RECT  102.551 24.066 102.587 25.164 ;
     RECT  102.551 26.226 102.587 27.63 ;
     RECT  102.047 28.458 102.587 29.484 ;
     RECT  102.047 30.276 102.587 33.606 ;
     RECT  102.551 34.866 102.587 35.424 ;
     RECT  101.651 36.216 102.587 38.43 ;
     RECT  101.651 39.258 102.587 40.284 ;
     RECT  102.551 41.346 102.587 41.634 ;
     RECT  101.723 42.426 102.587 42.444 ;
     RECT  102.551 43.506 102.587 44.064 ;
     RECT  101.723 44.856 102.587 47.574 ;
     RECT  101.723 48.366 102.587 49.734 ;
     RECT  101.52 50.526 102.587 50.958 ;
     RECT  101.52 51.876 102.587 54.864 ;
     RECT  102.515 55.692 102.587 58.14 ;
     RECT  102.515 58.896 102.587 61.344 ;
     RECT  102.047 62.136 102.587 62.154 ;
     RECT  102.551 63.216 102.587 66.204 ;
     RECT  102.551 67.266 102.587 70.524 ;
     RECT  102.551 71.586 102.587 71.604 ;
     RECT  102.047 72.396 102.587 74.844 ;
     RECT  101.52 75.636 102.587 76.878 ;
     RECT  102.047 78.066 102.587 78.354 ;
     RECT  102.047 79.146 102.587 81.324 ;
     RECT  102.551 82.386 102.587 82.944 ;
     RECT  101.52 83.736 102.587 85.644 ;
     RECT  102.551 86.706 102.587 87.678 ;
     RECT  102.551 88.776 102.587 92.124 ;
     RECT  102.551 93.186 102.587 94.284 ;
     RECT  102.047 95.346 102.587 96.444 ;
     RECT  102.551 97.506 102.587 98.604 ;
     RECT  102.047 99.396 102.587 102.924 ;
     RECT  102.047 103.986 102.587 104.544 ;
     RECT  102.047 105.336 102.587 105.354 ;
     RECT  102.551 106.686 102.587 107.118 ;
     RECT  102.551 108.306 102.587 111.024 ;
     RECT  102.047 111.852 102.587 111.87 ;
     RECT  102.047 113.166 102.587 113.994 ;
     RECT  102.047 115.056 102.587 115.884 ;
     RECT  102.047 116.676 102.587 118.044 ;
     RECT  102.551 119.106 102.587 120.204 ;
     RECT  102.551 121.536 102.587 121.554 ;
     RECT  102.587 8.514 102.623 8.532 ;
     RECT  102.587 17.046 102.623 17.064 ;
     RECT  102.587 20.124 102.623 20.142 ;
     RECT  102.587 22.176 102.623 22.194 ;
     RECT  102.587 33.588 102.623 33.606 ;
     RECT  102.587 37.026 102.623 37.044 ;
     RECT  102.587 52.992 102.623 53.01 ;
     RECT  102.587 58.122 102.623 58.14 ;
     RECT  102.587 60.246 102.623 60.264 ;
     RECT  102.587 65.52 102.623 65.538 ;
     RECT  102.587 68.958 102.623 68.976 ;
     RECT  102.587 72.936 102.623 72.954 ;
     RECT  102.587 88.902 102.623 88.92 ;
     RECT  102.587 99.666 102.623 99.684 ;
     RECT  102.587 101.286 102.623 101.304 ;
     RECT  102.587 109.998 102.623 110.016 ;
     RECT  102.587 113.976 102.623 113.994 ;
     RECT  102.587 117.324 102.623 117.342 ;
     RECT  102.587 54.684 103.595 54.702 ;
    LAYER M3 ;
     RECT  2.415 2.143 2.505 2.413 ;
     RECT  7.815 2.143 7.905 2.413 ;
     RECT  13.215 2.143 13.305 2.413 ;
     RECT  18.615 2.143 18.705 2.413 ;
     RECT  24.015 2.143 24.105 2.413 ;
     RECT  29.415 2.143 29.505 2.413 ;
     RECT  34.815 2.143 34.905 2.413 ;
     RECT  40.215 2.143 40.305 2.413 ;
     RECT  45.615 2.143 45.705 2.413 ;
     RECT  51.015 2.143 51.105 2.413 ;
     RECT  56.415 2.143 56.505 2.413 ;
     RECT  61.815 2.143 61.905 2.413 ;
     RECT  67.215 2.143 67.305 2.413 ;
     RECT  72.615 2.143 72.705 2.413 ;
     RECT  78.015 2.143 78.105 2.413 ;
     RECT  83.415 2.143 83.505 2.413 ;
     RECT  88.815 2.143 88.905 2.413 ;
     RECT  94.215 2.143 94.305 2.413 ;
     RECT  99.615 2.143 99.705 2.413 ;
     RECT  2.415 2.413 2.697 7.963 ;
     RECT  51.015 2.413 51.297 8.131 ;
     RECT  101.016 8.311 101.214 8.401 ;
     RECT  2.304 7.963 2.697 8.465 ;
     RECT  3.852 8.311 4.158 8.509 ;
     RECT  99.615 2.413 99.897 8.509 ;
     RECT  100.728 8.401 101.214 8.509 ;
     RECT  98.208 8.401 98.226 8.581 ;
     RECT  99.615 8.509 101.214 8.581 ;
     RECT  102.6 8.509 102.618 8.621 ;
     RECT  2.415 8.465 2.697 8.815 ;
     RECT  99.576 8.581 101.214 8.815 ;
     RECT  3.744 8.509 4.158 8.851 ;
     RECT  94.215 2.413 94.497 8.941 ;
     RECT  99 8.815 101.214 8.957 ;
     RECT  3.744 8.851 4.302 8.969 ;
     RECT  3.744 8.969 4.014 9.005 ;
     RECT  98.1 8.581 98.226 9.019 ;
     RECT  3.888 9.005 4.014 9.041 ;
     RECT  5.076 8.851 5.094 9.067 ;
     RECT  5.076 9.067 5.454 9.085 ;
     RECT  3.924 9.041 4.014 9.101 ;
     RECT  50.724 8.131 51.297 9.121 ;
     RECT  97.38 9.019 98.226 9.149 ;
     RECT  45.615 2.413 45.897 9.211 ;
     RECT  99.324 8.957 101.214 9.239 ;
     RECT  2.415 8.815 2.826 9.247 ;
     RECT  99.324 9.239 100.386 9.275 ;
     RECT  95.76 9.115 95.778 9.319 ;
     RECT  2.304 9.247 2.826 9.391 ;
     RECT  5.076 9.085 5.742 9.391 ;
     RECT  94.215 8.941 94.662 9.499 ;
     RECT  5.076 9.391 6.318 9.509 ;
     RECT  99.615 9.275 100.314 9.509 ;
     RECT  95.76 9.319 96.354 9.517 ;
     RECT  95.76 9.517 96.534 9.815 ;
     RECT  97.668 9.149 98.226 9.815 ;
     RECT  2.304 9.391 2.934 9.931 ;
     RECT  3.924 9.101 3.942 9.931 ;
     RECT  50.652 9.121 51.297 9.931 ;
     RECT  94.176 9.499 94.662 9.931 ;
     RECT  95.76 9.815 96.354 9.931 ;
     RECT  97.992 9.815 98.226 9.931 ;
     RECT  94.176 9.931 96.354 9.959 ;
     RECT  2.304 9.931 4.086 10.049 ;
     RECT  97.992 9.931 98.622 10.049 ;
     RECT  101.196 9.239 101.214 10.049 ;
     RECT  2.304 10.049 3.582 10.085 ;
     RECT  94.176 9.959 95.994 10.085 ;
     RECT  94.215 10.085 95.994 10.121 ;
     RECT  99.615 9.509 100.242 10.201 ;
     RECT  2.304 10.085 3.51 10.319 ;
     RECT  95.76 10.121 95.994 10.319 ;
     RECT  94.215 10.121 94.986 10.355 ;
     RECT  95.76 10.319 95.778 10.355 ;
     RECT  5.076 9.509 5.742 10.471 ;
     RECT  99.288 10.201 100.242 10.471 ;
     RECT  101.16 10.435 101.178 10.471 ;
     RECT  4.68 10.471 5.742 10.561 ;
     RECT  94.215 10.355 94.662 10.589 ;
     RECT  3.492 10.319 3.51 10.859 ;
     RECT  4.68 10.561 5.85 11.011 ;
     RECT  6.768 10.741 6.786 11.011 ;
     RECT  2.304 10.319 2.697 11.021 ;
     RECT  7.815 2.413 8.097 11.227 ;
     RECT  4.608 11.011 6.786 11.281 ;
     RECT  7.815 11.227 8.406 11.281 ;
     RECT  2.415 11.021 2.697 11.371 ;
     RECT  7.815 11.281 8.586 11.399 ;
     RECT  99.288 10.471 101.178 11.399 ;
     RECT  98.064 10.049 98.19 11.515 ;
     RECT  97.668 11.515 98.19 11.551 ;
     RECT  99.288 11.399 100.746 11.551 ;
     RECT  2.415 11.371 2.862 11.669 ;
     RECT  45.036 9.211 45.897 11.669 ;
     RECT  4.572 11.281 6.786 11.785 ;
     RECT  90.648 11.641 90.666 11.813 ;
     RECT  4.14 11.785 6.786 11.821 ;
     RECT  97.668 11.551 100.746 11.821 ;
     RECT  2.415 11.669 2.697 11.851 ;
     RECT  97.38 11.821 100.746 11.885 ;
     RECT  96.336 11.821 96.57 11.888 ;
     RECT  95.4 11.677 95.418 11.933 ;
     RECT  97.668 11.885 100.746 11.939 ;
     RECT  96.336 11.888 96.894 11.975 ;
     RECT  50.22 9.931 51.297 12.119 ;
     RECT  3.708 11.821 6.786 12.209 ;
     RECT  94.215 10.589 94.497 12.217 ;
     RECT  3.708 12.209 3.726 12.245 ;
     RECT  4.5 12.209 6.786 12.245 ;
     RECT  96.408 11.975 96.894 12.245 ;
     RECT  98.172 11.939 100.746 12.325 ;
     RECT  5.076 12.245 6.786 12.427 ;
     RECT  98.172 12.325 101.07 12.479 ;
     RECT  94.215 12.217 94.662 12.551 ;
     RECT  99.072 12.479 101.07 12.721 ;
     RECT  5.076 12.427 6.93 12.749 ;
     RECT  48.42 11.101 48.438 12.757 ;
     RECT  49.608 12.451 49.626 12.757 ;
     RECT  2.304 11.851 2.697 12.785 ;
     RECT  99.072 12.721 101.178 12.821 ;
     RECT  6.912 12.749 6.93 12.865 ;
     RECT  7.815 11.399 8.097 12.865 ;
     RECT  6.912 12.865 8.097 12.893 ;
     RECT  50.832 12.119 51.297 12.901 ;
     RECT  96.876 12.245 96.894 12.901 ;
     RECT  98.172 12.479 98.19 12.991 ;
     RECT  95.868 12.721 95.886 13.003 ;
     RECT  50.544 12.901 51.297 13.019 ;
     RECT  95.724 13.003 95.886 13.019 ;
     RECT  5.076 12.749 6.066 13.055 ;
     RECT  95.724 13.019 95.742 13.055 ;
     RECT  96.876 12.901 96.966 13.055 ;
     RECT  7.164 12.893 8.097 13.085 ;
     RECT  48.42 12.757 49.626 13.091 ;
     RECT  4.068 13.063 4.086 13.099 ;
     RECT  5.076 13.055 5.094 13.099 ;
     RECT  98.064 12.991 98.19 13.171 ;
     RECT  0.54 13.063 0.558 13.181 ;
     RECT  97.056 13.171 98.19 13.261 ;
     RECT  99.072 12.821 101.034 13.261 ;
     RECT  97.056 13.261 101.034 13.289 ;
     RECT  97.056 13.289 97.074 13.325 ;
     RECT  98.064 13.289 101.034 13.325 ;
     RECT  94.215 12.551 94.497 13.441 ;
     RECT  4.068 13.099 5.094 13.559 ;
     RECT  98.172 13.325 101.034 13.559 ;
     RECT  2.415 12.785 2.697 13.579 ;
     RECT  94.215 13.441 94.662 13.595 ;
     RECT  4.068 13.559 4.59 13.627 ;
     RECT  4.032 13.627 4.59 13.661 ;
     RECT  45.615 11.669 45.897 13.801 ;
     RECT  48.78 13.091 49.626 13.829 ;
     RECT  99.54 13.559 101.034 13.945 ;
     RECT  4.032 13.661 4.194 13.981 ;
     RECT  2.412 13.579 2.697 14.011 ;
     RECT  3.888 13.981 4.194 14.099 ;
     RECT  99.54 13.945 101.142 14.099 ;
     RECT  2.304 14.011 2.697 14.135 ;
     RECT  99.54 14.099 100.782 14.135 ;
     RECT  3.888 14.099 4.05 14.215 ;
     RECT  50.832 13.019 51.297 14.251 ;
     RECT  7.815 13.085 8.097 14.299 ;
     RECT  6.048 13.055 6.066 14.341 ;
     RECT  7.128 14.299 8.097 14.341 ;
     RECT  3.492 14.215 4.05 14.369 ;
     RECT  48.888 13.829 49.626 14.369 ;
     RECT  50.544 14.251 51.297 14.369 ;
     RECT  45.615 13.801 46.206 14.377 ;
     RECT  99.54 14.135 100.314 14.405 ;
     RECT  94.215 13.595 94.497 14.449 ;
     RECT  95.832 14.251 95.85 14.485 ;
     RECT  5.724 14.341 6.066 14.521 ;
     RECT  45.615 14.377 46.782 14.549 ;
     RECT  5.544 14.521 6.066 14.611 ;
     RECT  6.84 14.341 8.097 14.611 ;
     RECT  95.652 14.485 95.85 14.611 ;
     RECT  96.624 14.521 96.642 14.611 ;
     RECT  5.544 14.611 8.097 14.639 ;
     RECT  5.544 14.639 6.822 14.675 ;
     RECT  6.228 14.675 6.822 14.711 ;
     RECT  2.415 14.135 2.697 14.875 ;
     RECT  6.228 14.711 6.246 14.909 ;
     RECT  47.304 14.611 47.322 14.909 ;
     RECT  2.34 14.875 2.697 14.945 ;
     RECT  5.328 14.791 5.346 14.945 ;
     RECT  98.172 13.559 98.586 14.981 ;
     RECT  90.648 14.881 90.666 15.017 ;
     RECT  95.652 14.611 96.642 15.061 ;
     RECT  48.888 14.369 49.446 15.179 ;
     RECT  95.472 15.061 96.858 15.215 ;
     RECT  2.415 14.945 2.697 15.295 ;
     RECT  3.816 14.369 4.05 15.331 ;
     RECT  99.576 14.405 99.918 15.331 ;
     RECT  100.728 15.151 100.746 15.331 ;
     RECT  2.415 15.295 2.826 15.341 ;
     RECT  96.012 15.215 96.858 15.421 ;
     RECT  99.432 15.331 100.746 15.449 ;
     RECT  3.816 15.331 4.266 15.485 ;
     RECT  45.615 14.549 46.206 15.485 ;
     RECT  99.432 15.449 99.954 15.485 ;
     RECT  5.04 15.331 5.058 15.691 ;
     RECT  96.012 15.421 96.966 15.719 ;
     RECT  100.764 15.565 101.178 15.719 ;
     RECT  45.615 15.485 45.897 15.727 ;
     RECT  3.96 15.485 4.266 15.763 ;
     RECT  5.04 15.691 5.706 15.763 ;
     RECT  3.96 15.763 5.706 15.871 ;
     RECT  3.96 15.871 6.174 15.961 ;
     RECT  96.012 15.719 96.354 15.961 ;
     RECT  3.96 15.961 6.534 15.989 ;
     RECT  3.96 15.989 5.274 16.025 ;
     RECT  98.172 14.981 98.226 16.069 ;
     RECT  2.415 15.341 2.697 16.171 ;
     RECT  50.832 14.369 51.297 16.231 ;
     RECT  97.38 16.069 98.226 16.231 ;
     RECT  99.468 15.485 99.954 16.259 ;
     RECT  97.38 16.231 98.586 16.331 ;
     RECT  99.615 16.259 99.954 16.375 ;
     RECT  100.764 15.719 100.926 16.375 ;
     RECT  6.516 15.989 6.534 16.411 ;
     RECT  99.615 16.375 100.926 16.501 ;
     RECT  6.516 16.411 6.678 16.529 ;
     RECT  6.516 16.529 6.534 16.541 ;
     RECT  5.04 16.025 5.274 16.565 ;
     RECT  97.38 16.331 98.19 16.565 ;
     RECT  95.976 15.961 96.354 16.609 ;
     RECT  94.215 14.449 94.662 16.681 ;
     RECT  49.428 15.179 49.446 16.709 ;
     RECT  94.215 16.681 95.13 16.799 ;
     RECT  3.996 16.025 4.014 16.807 ;
     RECT  5.04 16.565 5.058 16.807 ;
     RECT  50.796 16.231 51.297 16.807 ;
     RECT  2.304 16.171 2.697 16.835 ;
     RECT  3.996 16.807 5.058 16.835 ;
     RECT  94.215 16.799 94.986 16.835 ;
     RECT  102.564 9.013 102.582 16.835 ;
     RECT  95.976 16.609 96.39 16.951 ;
     RECT  52.488 9.553 52.506 17.041 ;
     RECT  50.724 16.807 51.297 17.069 ;
     RECT  99.615 16.501 101.178 17.069 ;
     RECT  95.904 16.951 96.39 17.105 ;
     RECT  99.615 17.069 100.422 17.105 ;
     RECT  4.068 16.835 5.058 17.117 ;
     RECT  97.668 16.565 98.19 17.221 ;
     RECT  102.6 17.041 102.618 17.261 ;
     RECT  101.196 17.185 101.214 17.339 ;
     RECT  4.068 17.117 4.086 17.375 ;
     RECT  96.012 17.105 96.39 17.483 ;
     RECT  2.412 16.835 2.697 17.491 ;
     RECT  99.615 17.105 100.026 17.491 ;
     RECT  2.412 17.491 2.898 17.501 ;
     RECT  94.215 16.835 94.662 17.519 ;
     RECT  96.372 17.483 96.39 17.581 ;
     RECT  2.415 17.501 2.898 17.609 ;
     RECT  5.004 17.117 5.058 17.609 ;
     RECT  96.372 17.581 96.822 17.611 ;
     RECT  97.668 17.221 98.766 17.611 ;
     RECT  96.372 17.611 98.766 17.617 ;
     RECT  96.372 17.617 98.802 17.651 ;
     RECT  45.036 15.727 45.897 17.789 ;
     RECT  5.328 17.761 5.67 17.879 ;
     RECT  101.988 17.659 102.006 17.879 ;
     RECT  3.816 17.581 3.834 17.915 ;
     RECT  99.54 17.491 100.026 18.121 ;
     RECT  5.328 17.879 5.346 18.185 ;
     RECT  6.768 18.139 6.786 18.185 ;
     RECT  98.1 17.651 98.802 18.193 ;
     RECT  99.54 18.121 100.314 18.193 ;
     RECT  94.215 17.519 94.497 18.301 ;
     RECT  2.415 17.609 2.826 18.331 ;
     RECT  96.372 17.651 96.822 18.379 ;
     RECT  96.228 18.379 97.038 18.419 ;
     RECT  2.304 18.331 2.826 18.455 ;
     RECT  52.488 17.041 52.83 18.491 ;
     RECT  94.215 18.301 94.662 18.491 ;
     RECT  96.804 18.419 97.038 18.499 ;
     RECT  98.1 18.193 100.314 18.499 ;
     RECT  2.415 18.455 2.826 18.571 ;
     RECT  4.428 18.619 4.446 18.661 ;
     RECT  96.804 18.499 100.314 18.661 ;
     RECT  96.804 18.661 100.494 18.689 ;
     RECT  2.415 18.571 3.15 18.725 ;
     RECT  98.172 18.689 100.494 18.769 ;
     RECT  4.356 18.661 4.446 18.797 ;
     RECT  98.172 18.769 101.034 18.805 ;
     RECT  96.804 18.689 97.326 18.959 ;
     RECT  98.172 18.805 101.178 18.959 ;
     RECT  98.172 18.959 100.422 19.103 ;
     RECT  2.415 18.725 2.754 19.195 ;
     RECT  5.472 18.769 5.49 19.195 ;
     RECT  2.304 19.195 2.754 19.229 ;
     RECT  99.36 19.103 100.422 19.265 ;
     RECT  6.84 19.237 6.858 19.337 ;
     RECT  50.832 17.069 51.297 19.345 ;
     RECT  52.488 18.491 52.506 19.345 ;
     RECT  7.815 14.639 8.097 19.387 ;
     RECT  96.804 18.959 96.822 19.387 ;
     RECT  98.172 19.103 98.514 19.471 ;
     RECT  3.492 19.201 3.51 19.499 ;
     RECT  97.992 19.471 98.514 19.499 ;
     RECT  99.36 19.265 100.314 19.499 ;
     RECT  101.16 18.959 101.178 19.571 ;
     RECT  4.392 18.797 4.446 19.651 ;
     RECT  5.436 19.195 5.49 19.651 ;
     RECT  6.3 19.381 6.822 19.661 ;
     RECT  6.444 19.661 6.822 19.769 ;
     RECT  4.392 19.651 5.49 19.805 ;
     RECT  7.632 19.387 8.097 19.805 ;
     RECT  99.36 19.499 99.918 19.805 ;
     RECT  102.564 18.091 102.582 19.819 ;
     RECT  95.724 19.741 95.742 19.921 ;
     RECT  96.66 19.387 96.822 19.921 ;
     RECT  97.992 19.499 98.442 19.921 ;
     RECT  6.804 19.769 6.822 20.039 ;
     RECT  49.86 17.761 49.878 20.039 ;
     RECT  5.148 19.805 5.49 20.075 ;
     RECT  99.396 19.805 99.918 20.075 ;
     RECT  102.024 19.819 102.582 20.119 ;
     RECT  99.615 20.075 99.918 20.183 ;
     RECT  4.392 19.805 4.41 20.191 ;
     RECT  102.024 20.119 102.618 20.219 ;
     RECT  5.472 20.075 5.49 20.309 ;
     RECT  102.564 20.219 102.618 20.309 ;
     RECT  4.068 20.191 4.41 20.345 ;
     RECT  97.596 19.921 98.442 20.345 ;
     RECT  95.724 19.921 96.822 20.389 ;
     RECT  95.724 20.389 97.146 20.453 ;
     RECT  95.724 20.453 95.85 20.477 ;
     RECT  5.688 20.461 5.706 20.539 ;
     RECT  96.804 20.453 97.146 20.615 ;
     RECT  102.6 20.309 102.618 20.717 ;
     RECT  97.992 20.345 98.442 20.731 ;
     RECT  94.215 18.491 94.497 20.857 ;
     RECT  4.572 20.731 4.59 20.885 ;
     RECT  99.615 20.183 99.897 20.929 ;
     RECT  96.876 20.615 97.146 20.993 ;
     RECT  99.576 20.929 99.897 21.001 ;
     RECT  101.196 20.155 101.214 21.001 ;
     RECT  97.992 20.731 98.694 21.091 ;
     RECT  100.728 21.001 101.214 21.119 ;
     RECT  50.832 19.345 52.506 21.155 ;
     RECT  100.728 21.119 100.746 21.155 ;
     RECT  2.304 19.229 2.697 21.271 ;
     RECT  97.884 21.091 98.694 21.271 ;
     RECT  99.504 21.001 99.897 21.271 ;
     RECT  94.215 20.857 94.662 21.299 ;
     RECT  2.304 21.271 3.114 21.389 ;
     RECT  5.688 20.539 5.742 21.505 ;
     RECT  4.788 21.505 5.742 21.541 ;
     RECT  102.564 21.115 102.582 21.547 ;
     RECT  45.615 17.789 45.897 21.631 ;
     RECT  95.724 20.477 95.742 21.643 ;
     RECT  101.988 21.547 102.582 21.659 ;
     RECT  97.884 21.271 100.566 21.677 ;
     RECT  4.788 21.541 6.246 21.695 ;
     RECT  2.304 21.389 3.042 21.821 ;
     RECT  5.148 21.695 5.706 21.929 ;
     RECT  95.58 21.643 95.742 21.929 ;
     RECT  3.996 21.631 4.014 21.965 ;
     RECT  102.564 21.659 102.582 22.013 ;
     RECT  98.172 21.677 100.566 22.045 ;
     RECT  6.984 21.541 7.002 22.081 ;
     RECT  97.128 20.993 97.146 22.081 ;
     RECT  2.415 21.821 3.042 22.171 ;
     RECT  4.392 22.081 4.41 22.199 ;
     RECT  52.488 21.155 52.506 22.207 ;
     RECT  5.58 21.929 5.706 22.235 ;
     RECT  52.488 22.207 52.902 22.315 ;
     RECT  53.712 9.013 53.73 22.315 ;
     RECT  98.172 22.045 101.07 22.315 ;
     RECT  5.652 22.235 5.706 22.379 ;
     RECT  102.6 22.171 102.618 22.445 ;
     RECT  98.172 22.315 101.214 22.459 ;
     RECT  5.652 22.379 5.67 22.469 ;
     RECT  98.1 22.459 101.214 22.469 ;
     RECT  98.1 22.469 101.178 22.505 ;
     RECT  2.415 22.171 3.618 22.541 ;
     RECT  96.516 22.081 97.146 22.747 ;
     RECT  98.172 22.505 101.178 22.775 ;
     RECT  0.108 22.207 0.126 22.781 ;
     RECT  96.228 22.747 97.146 22.784 ;
     RECT  50.832 21.155 51.297 22.981 ;
     RECT  6.552 22.081 7.002 23.009 ;
     RECT  52.488 22.315 53.73 23.009 ;
     RECT  96.228 22.784 96.39 23.009 ;
     RECT  54.612 8.671 54.63 23.017 ;
     RECT  94.215 21.299 94.497 23.017 ;
     RECT  98.172 22.775 98.478 23.045 ;
     RECT  2.415 22.541 3.006 23.083 ;
     RECT  96.228 23.009 96.246 23.161 ;
     RECT  54.612 23.017 54.702 23.189 ;
     RECT  95.652 23.161 96.246 23.189 ;
     RECT  4.068 23.161 4.698 23.251 ;
     RECT  50.724 22.981 51.297 23.251 ;
     RECT  97.164 23.161 97.182 23.251 ;
     RECT  98.172 23.045 98.19 23.251 ;
     RECT  99.615 22.775 101.178 23.279 ;
     RECT  6.552 23.009 6.57 23.317 ;
     RECT  97.164 23.251 98.19 23.351 ;
     RECT  4.068 23.251 5.166 23.357 ;
     RECT  6.012 23.317 6.57 23.357 ;
     RECT  5.148 23.357 5.166 23.549 ;
     RECT  2.304 23.083 3.006 23.585 ;
     RECT  4.068 23.357 4.086 23.585 ;
     RECT  2.412 23.585 3.006 23.701 ;
     RECT  50.184 23.251 51.297 23.701 ;
     RECT  102.564 22.843 102.582 23.707 ;
     RECT  2.412 23.701 3.186 23.791 ;
     RECT  49.968 23.701 51.297 23.791 ;
     RECT  98.172 23.351 98.19 23.791 ;
     RECT  49.968 23.791 51.534 23.819 ;
     RECT  95.652 23.189 95.67 23.819 ;
     RECT  102.528 23.707 102.582 23.819 ;
     RECT  99.615 23.279 100.746 23.827 ;
     RECT  46.764 23.827 46.782 23.927 ;
     RECT  98.172 23.791 98.406 23.971 ;
     RECT  52.488 23.009 52.902 23.999 ;
     RECT  99.468 23.827 100.746 24.061 ;
     RECT  98.172 23.971 98.55 24.089 ;
     RECT  97.164 23.351 97.182 24.125 ;
     RECT  99.468 24.061 101.178 24.161 ;
     RECT  5.544 24.205 5.562 24.235 ;
     RECT  6.552 23.357 6.57 24.235 ;
     RECT  99.468 24.161 101.07 24.241 ;
     RECT  5.544 24.235 6.57 24.269 ;
     RECT  5.688 24.269 6.57 24.359 ;
     RECT  54.612 23.189 54.63 24.367 ;
     RECT  99.324 24.241 101.07 24.395 ;
     RECT  2.412 23.791 3.978 24.413 ;
     RECT  54.612 24.367 54.702 24.467 ;
     RECT  3.528 24.413 3.978 24.475 ;
     RECT  98.172 24.089 98.37 24.509 ;
     RECT  3.528 24.475 4.554 24.629 ;
     RECT  6.228 24.359 6.282 24.629 ;
     RECT  3.528 24.629 3.546 24.665 ;
     RECT  4.536 24.629 4.554 24.665 ;
     RECT  94.068 23.017 94.497 24.809 ;
     RECT  2.412 24.413 2.697 24.811 ;
     RECT  95.94 24.781 95.958 24.859 ;
     RECT  99.324 24.395 99.897 24.871 ;
     RECT  50.184 23.819 51.534 24.899 ;
     RECT  95.796 24.859 95.958 24.899 ;
     RECT  96.696 24.859 96.714 25.051 ;
     RECT  98.172 24.509 98.19 25.051 ;
     RECT  96.696 25.051 98.19 25.205 ;
     RECT  6.264 24.629 6.282 25.285 ;
     RECT  100.692 24.395 101.07 25.285 ;
     RECT  6.264 25.285 6.642 25.313 ;
     RECT  95.724 24.907 95.742 25.313 ;
     RECT  99.252 24.871 99.897 25.321 ;
     RECT  100.692 25.285 101.178 25.321 ;
     RECT  99.252 25.321 101.178 25.349 ;
     RECT  96.948 25.205 98.19 25.475 ;
     RECT  5.256 25.051 5.274 25.591 ;
     RECT  4.14 25.591 5.274 25.627 ;
     RECT  6.624 25.313 6.642 25.661 ;
     RECT  2.304 24.811 2.697 25.745 ;
     RECT  4.14 25.627 5.49 25.861 ;
     RECT  102.564 23.819 102.582 25.867 ;
     RECT  98.172 25.475 98.19 25.963 ;
     RECT  50.328 24.899 51.534 25.979 ;
     RECT  102.528 25.867 102.582 25.979 ;
     RECT  98.172 25.963 98.442 26.015 ;
     RECT  3.708 25.861 5.49 26.095 ;
     RECT  2.415 25.745 2.697 26.107 ;
     RECT  3.492 26.095 5.49 26.107 ;
     RECT  99.615 25.349 101.178 26.131 ;
     RECT  2.415 26.107 5.49 26.141 ;
     RECT  6.84 25.987 6.858 26.159 ;
     RECT  94.215 24.809 94.497 26.221 ;
     RECT  50.328 25.979 51.426 26.249 ;
     RECT  99.54 26.131 101.178 26.249 ;
     RECT  2.415 26.141 2.898 26.285 ;
     RECT  45.036 21.631 45.897 26.321 ;
     RECT  94.215 26.221 94.698 26.393 ;
     RECT  3.996 26.141 5.49 26.401 ;
     RECT  99.54 26.249 100.314 26.401 ;
     RECT  49.176 26.401 49.266 26.519 ;
     RECT  99.288 26.401 100.314 26.519 ;
     RECT  99.54 26.519 100.314 26.555 ;
     RECT  2.415 26.285 2.79 26.573 ;
     RECT  3.996 26.401 5.742 26.669 ;
     RECT  5.652 26.669 5.742 26.671 ;
     RECT  95.832 26.257 95.85 26.683 ;
     RECT  97.344 26.251 97.362 26.731 ;
     RECT  102.564 25.979 102.582 26.731 ;
     RECT  7.815 19.805 8.097 26.761 ;
     RECT  98.172 26.015 98.298 26.761 ;
     RECT  5.652 26.671 6.318 26.789 ;
     RECT  95.616 26.683 95.85 26.789 ;
     RECT  102.024 26.731 102.582 26.789 ;
     RECT  98.172 26.761 98.586 26.825 ;
     RECT  99.615 26.555 100.314 26.825 ;
     RECT  97.128 26.731 97.362 26.941 ;
     RECT  2.415 26.573 2.697 26.971 ;
     RECT  2.304 26.971 2.697 27.095 ;
     RECT  96.84 26.941 97.362 27.095 ;
     RECT  3.996 26.669 4.482 27.211 ;
     RECT  95.616 26.789 95.634 27.301 ;
     RECT  98.244 26.825 98.586 27.301 ;
     RECT  3.6 27.211 4.482 27.337 ;
     RECT  95.544 27.301 95.634 27.365 ;
     RECT  0.54 27.337 0.558 27.437 ;
     RECT  95.544 27.365 95.562 27.473 ;
     RECT  99.615 26.825 99.897 27.481 ;
     RECT  50.328 26.249 51.354 27.509 ;
     RECT  97.38 27.301 97.398 27.635 ;
     RECT  102.564 26.789 102.582 27.635 ;
     RECT  94.215 26.393 94.497 27.643 ;
     RECT  99.504 27.481 99.897 27.679 ;
     RECT  101.16 26.249 101.178 27.679 ;
     RECT  98.244 27.301 98.622 27.715 ;
     RECT  99.504 27.679 101.178 27.715 ;
     RECT  3.42 27.337 4.482 27.751 ;
     RECT  5.724 26.789 5.742 27.751 ;
     RECT  50.832 27.509 51.354 27.751 ;
     RECT  52.488 23.999 52.506 27.751 ;
     RECT  2.415 27.095 2.697 27.835 ;
     RECT  3.42 27.751 5.742 27.869 ;
     RECT  98.244 27.715 101.178 27.869 ;
     RECT  7.092 26.761 8.097 27.877 ;
     RECT  3.42 27.869 4.698 27.941 ;
     RECT  5.436 27.869 5.742 28.139 ;
     RECT  50.832 27.751 52.506 28.139 ;
     RECT  101.988 28.027 102.006 28.139 ;
     RECT  3.996 27.941 4.698 28.175 ;
     RECT  97.236 28.255 97.254 28.267 ;
     RECT  49.248 26.519 49.266 28.283 ;
     RECT  52.02 28.139 52.506 28.291 ;
     RECT  6.696 27.877 8.097 28.319 ;
     RECT  52.02 28.291 52.578 28.409 ;
     RECT  97.056 28.267 97.254 28.409 ;
     RECT  6.696 28.319 6.966 28.445 ;
     RECT  97.056 28.409 97.074 28.525 ;
     RECT  96.48 28.525 97.074 28.553 ;
     RECT  6.696 28.445 6.714 28.561 ;
     RECT  98.244 27.869 101.07 28.561 ;
     RECT  6.228 28.561 6.714 28.679 ;
     RECT  5.436 28.139 5.454 28.715 ;
     RECT  94.215 27.643 94.662 28.859 ;
     RECT  94.215 28.859 94.497 28.921 ;
     RECT  98.028 28.561 101.07 28.921 ;
     RECT  47.304 28.381 47.322 28.949 ;
     RECT  96.48 28.553 96.642 28.949 ;
     RECT  96.48 28.949 96.498 29.021 ;
     RECT  4.464 28.175 4.482 29.029 ;
     RECT  97.92 28.921 101.07 29.065 ;
     RECT  4.032 29.029 4.626 29.083 ;
     RECT  4.032 29.083 4.734 29.255 ;
     RECT  97.92 29.065 101.214 29.255 ;
     RECT  98.064 29.255 101.214 29.489 ;
     RECT  2.304 27.835 2.697 29.563 ;
     RECT  50.832 28.139 51.297 29.641 ;
     RECT  52.02 28.409 52.506 29.641 ;
     RECT  93.492 28.921 94.497 29.641 ;
     RECT  50.832 29.641 52.506 29.669 ;
     RECT  99 29.489 101.214 29.759 ;
     RECT  2.304 29.563 3.078 29.795 ;
     RECT  4.392 29.255 4.734 29.795 ;
     RECT  4.536 29.795 4.734 29.911 ;
     RECT  5.688 28.921 5.706 29.911 ;
     RECT  50.832 29.669 51.642 30.001 ;
     RECT  2.304 29.795 2.697 30.065 ;
     RECT  4.536 29.911 5.706 30.065 ;
     RECT  99 29.759 100.17 30.065 ;
     RECT  5.688 30.065 5.706 30.145 ;
     RECT  6.696 28.679 6.714 30.145 ;
     RECT  102.564 28.453 102.582 30.181 ;
     RECT  102.024 30.181 102.582 30.221 ;
     RECT  5.688 30.145 6.714 30.299 ;
     RECT  99.18 30.065 100.17 30.299 ;
     RECT  50.724 30.001 51.642 30.307 ;
     RECT  4.536 30.065 4.554 30.335 ;
     RECT  95.616 30.271 95.634 30.371 ;
     RECT  50.184 30.307 51.642 30.407 ;
     RECT  99.18 30.299 99.897 30.443 ;
     RECT  50.436 30.407 51.642 30.451 ;
     RECT  96.48 30.415 96.498 30.451 ;
     RECT  98.064 29.489 98.262 30.451 ;
     RECT  95.4 30.415 95.418 30.461 ;
     RECT  96.336 30.451 96.498 30.461 ;
     RECT  93.492 29.641 94.662 30.479 ;
     RECT  96.336 30.461 96.354 30.605 ;
     RECT  100.62 30.721 100.638 30.847 ;
     RECT  97.704 30.451 98.262 30.875 ;
     RECT  100.62 30.847 100.926 30.875 ;
     RECT  5.688 30.299 6.03 30.949 ;
     RECT  94.215 30.479 94.662 30.983 ;
     RECT  5.58 30.949 6.03 30.989 ;
     RECT  50.436 30.451 51.678 30.991 ;
     RECT  52.488 29.669 52.506 30.991 ;
     RECT  98.172 30.875 98.262 30.991 ;
     RECT  100.908 30.875 100.926 31.019 ;
     RECT  4.068 30.721 4.482 31.109 ;
     RECT  2.34 30.065 2.697 31.291 ;
     RECT  2.304 31.291 2.697 31.415 ;
     RECT  4.068 31.109 4.266 31.531 ;
     RECT  99.576 30.443 99.897 31.531 ;
     RECT  98.172 30.991 98.73 31.621 ;
     RECT  97.128 31.531 97.146 31.649 ;
     RECT  2.415 31.415 2.697 31.723 ;
     RECT  3.564 31.531 4.266 31.723 ;
     RECT  98.064 31.621 98.73 31.729 ;
     RECT  99.576 31.531 99.954 31.729 ;
     RECT  101.052 31.081 101.07 31.765 ;
     RECT  5.58 30.989 5.994 31.801 ;
     RECT  7.815 28.319 8.097 31.801 ;
     RECT  98.064 31.729 99.954 31.801 ;
     RECT  101.052 31.765 101.178 31.801 ;
     RECT  96.984 31.771 97.002 31.829 ;
     RECT  5.58 31.801 6.246 31.867 ;
     RECT  7.272 31.801 8.097 31.867 ;
     RECT  5.58 31.867 8.097 31.891 ;
     RECT  96.156 31.771 96.174 31.891 ;
     RECT  5.436 31.891 8.097 31.901 ;
     RECT  6.228 31.901 8.097 31.919 ;
     RECT  46.764 31.801 46.782 31.919 ;
     RECT  2.415 31.723 4.266 31.955 ;
     RECT  2.415 31.955 2.697 32.155 ;
     RECT  94.215 30.983 94.497 32.269 ;
     RECT  3.672 31.955 4.266 32.341 ;
     RECT  94.215 32.269 94.662 32.341 ;
     RECT  50.436 30.991 52.506 32.369 ;
     RECT  98.064 31.801 101.178 32.431 ;
     RECT  50.436 32.369 51.297 32.459 ;
     RECT  96.156 31.891 96.75 32.467 ;
     RECT  3.672 32.341 4.698 32.495 ;
     RECT  94.215 32.341 94.734 32.495 ;
     RECT  95.94 32.467 96.75 32.495 ;
     RECT  97.596 32.431 101.178 32.495 ;
     RECT  99.615 32.495 101.178 32.531 ;
     RECT  97.596 32.495 98.658 32.765 ;
     RECT  4.248 32.495 4.698 32.909 ;
     RECT  47.88 32.701 47.898 32.971 ;
     RECT  4.392 32.909 4.698 32.999 ;
     RECT  99.615 32.531 100.566 32.999 ;
     RECT  3.456 32.881 3.474 33.035 ;
     RECT  5.436 31.901 5.49 33.043 ;
     RECT  98.244 32.765 98.658 33.269 ;
     RECT  102.564 30.221 102.582 33.269 ;
     RECT  99.615 32.999 100.314 33.421 ;
     RECT  5.112 33.043 5.49 33.499 ;
     RECT  6.228 31.919 6.858 33.499 ;
     RECT  5.112 33.499 6.858 33.539 ;
     RECT  47.304 32.971 47.898 33.539 ;
     RECT  99.432 33.421 100.314 33.575 ;
     RECT  50.544 32.459 51.297 33.583 ;
     RECT  95.94 32.495 95.958 33.643 ;
     RECT  96.732 32.495 96.75 33.643 ;
     RECT  95.94 33.643 96.75 33.677 ;
     RECT  102.6 33.583 102.618 33.677 ;
     RECT  96.588 33.677 96.75 33.691 ;
     RECT  6.48 33.539 6.858 33.719 ;
     RECT  98.244 33.269 98.514 33.781 ;
     RECT  99.504 33.575 100.314 33.781 ;
     RECT  101.196 33.655 101.214 33.781 ;
     RECT  99.504 33.781 101.214 33.809 ;
     RECT  97.74 33.781 98.514 33.881 ;
     RECT  99.504 33.809 101.178 33.881 ;
     RECT  2.304 32.155 2.697 33.917 ;
     RECT  2.34 33.917 2.697 33.953 ;
     RECT  2.415 33.953 2.697 33.961 ;
     RECT  5.112 33.539 5.49 33.961 ;
     RECT  6.48 33.719 6.642 34.013 ;
     RECT  6.624 34.013 6.642 34.079 ;
     RECT  96.588 33.691 96.93 34.157 ;
     RECT  3.816 34.159 3.834 34.219 ;
     RECT  4.932 33.961 5.49 34.219 ;
     RECT  50.112 33.583 51.297 34.231 ;
     RECT  97.884 33.881 98.514 34.231 ;
     RECT  50.076 34.231 51.297 34.349 ;
     RECT  97.092 34.231 97.11 34.349 ;
     RECT  2.415 33.961 2.754 34.501 ;
     RECT  3.816 34.219 5.49 34.501 ;
     RECT  99.504 33.881 100.314 34.501 ;
     RECT  102.564 34.075 102.582 34.501 ;
     RECT  2.415 34.501 5.562 34.529 ;
     RECT  102.528 34.501 102.582 34.541 ;
     RECT  2.415 34.529 4.014 34.619 ;
     RECT  47.88 33.539 47.898 34.619 ;
     RECT  2.415 34.619 3.906 34.655 ;
     RECT  99.468 34.501 100.314 34.735 ;
     RECT  101.124 33.881 101.178 34.735 ;
     RECT  2.415 34.655 2.697 34.747 ;
     RECT  97.884 34.231 98.586 34.771 ;
     RECT  99.468 34.735 101.178 34.771 ;
     RECT  97.884 34.771 101.178 34.799 ;
     RECT  6.624 35.005 6.642 35.041 ;
     RECT  6.624 35.041 6.786 35.069 ;
     RECT  6.768 35.069 6.786 35.159 ;
     RECT  98.244 34.799 101.178 35.159 ;
     RECT  3.888 34.655 3.906 35.195 ;
     RECT  98.244 35.159 100.314 35.195 ;
     RECT  101.16 35.159 101.178 35.231 ;
     RECT  4.932 34.529 5.562 35.311 ;
     RECT  97.452 35.227 97.47 35.311 ;
     RECT  96.948 35.311 97.47 35.357 ;
     RECT  50.112 34.349 51.297 35.401 ;
     RECT  7.815 31.919 8.097 35.419 ;
     RECT  7.815 35.419 8.298 35.465 ;
     RECT  99.615 35.195 100.314 35.501 ;
     RECT  50.112 35.401 51.57 35.537 ;
     RECT  50.292 35.537 51.57 35.545 ;
     RECT  52.488 32.369 52.506 35.545 ;
     RECT  94.215 32.495 94.497 35.581 ;
     RECT  96.948 35.357 97.218 35.581 ;
     RECT  6.84 35.401 6.858 35.609 ;
     RECT  43.884 33.781 43.902 35.609 ;
     RECT  2.412 34.747 2.697 35.611 ;
     RECT  50.292 35.545 52.506 35.699 ;
     RECT  94.215 35.581 95.526 35.699 ;
     RECT  94.215 35.699 94.662 35.707 ;
     RECT  2.304 35.611 2.697 35.735 ;
     RECT  4.932 35.311 5.706 35.815 ;
     RECT  96.624 35.581 97.218 35.851 ;
     RECT  3.924 35.815 5.706 35.941 ;
     RECT  3.924 35.941 6.21 35.969 ;
     RECT  49.032 35.671 49.05 35.969 ;
     RECT  96.264 35.851 97.218 35.981 ;
     RECT  96.264 35.981 96.534 36.005 ;
     RECT  96.516 36.005 96.534 36.041 ;
     RECT  100.728 35.941 100.746 36.121 ;
     RECT  102.564 34.541 102.582 36.235 ;
     RECT  94.068 35.707 94.662 36.239 ;
     RECT  3.924 35.969 5.382 36.275 ;
     RECT  100.728 36.121 101.214 36.275 ;
     RECT  98.244 35.195 98.442 36.355 ;
     RECT  99.615 35.501 99.897 36.355 ;
     RECT  100.728 36.275 100.962 36.355 ;
     RECT  4.716 36.275 5.382 36.419 ;
     RECT  98.244 36.355 100.962 36.427 ;
     RECT  2.415 35.735 2.697 36.475 ;
     RECT  6.156 35.969 6.21 36.475 ;
     RECT  102.528 36.235 102.582 36.509 ;
     RECT  2.304 36.475 2.697 36.545 ;
     RECT  97.524 36.427 100.962 36.545 ;
     RECT  6.156 36.475 6.894 36.661 ;
     RECT  6.156 36.661 6.93 36.779 ;
     RECT  102.564 36.509 102.582 36.779 ;
     RECT  4.86 36.419 5.382 36.815 ;
     RECT  2.415 36.545 2.697 36.895 ;
     RECT  5.256 36.815 5.382 36.931 ;
     RECT  6.156 36.779 6.642 36.931 ;
     RECT  5.256 36.931 6.642 37.049 ;
     RECT  97.524 36.545 99.897 37.057 ;
     RECT  5.256 37.049 5.274 37.085 ;
     RECT  96.912 37.057 99.897 37.085 ;
     RECT  102.6 37.021 102.618 37.133 ;
     RECT  100.728 36.545 100.962 37.165 ;
     RECT  47.304 37.021 47.322 37.319 ;
     RECT  52.02 35.699 52.506 37.319 ;
     RECT  100.728 37.165 101.178 37.319 ;
     RECT  2.415 36.895 2.79 37.327 ;
     RECT  97.848 37.085 99.897 37.327 ;
     RECT  100.728 37.319 100.998 37.327 ;
     RECT  2.415 37.327 2.826 37.471 ;
     RECT  95.508 35.699 95.526 37.471 ;
     RECT  94.068 36.239 94.497 37.499 ;
     RECT  50.292 35.699 51.297 37.561 ;
     RECT  2.415 37.471 3.15 37.589 ;
     RECT  95.508 37.471 95.67 37.589 ;
     RECT  95.508 37.589 95.526 37.625 ;
     RECT  97.848 37.327 100.998 37.625 ;
     RECT  4.032 37.561 4.122 37.741 ;
     RECT  96.912 37.085 97.074 37.741 ;
     RECT  2.415 37.589 2.697 37.771 ;
     RECT  49.608 37.561 51.297 37.859 ;
     RECT  94.215 37.499 94.497 37.867 ;
     RECT  2.304 37.771 2.697 37.895 ;
     RECT  4.032 37.741 4.23 37.895 ;
     RECT  96.696 37.741 97.074 37.895 ;
     RECT  98.1 37.625 100.998 37.895 ;
     RECT  94.215 37.867 94.662 37.967 ;
     RECT  50.292 37.859 51.297 37.975 ;
     RECT  6.156 37.049 6.174 38.003 ;
     RECT  5.148 37.579 5.166 38.011 ;
     RECT  50.292 37.975 51.39 38.039 ;
     RECT  4.536 38.011 5.166 38.129 ;
     RECT  96.84 37.895 97.074 38.129 ;
     RECT  98.244 37.895 100.998 38.129 ;
     RECT  4.536 38.129 4.698 38.165 ;
     RECT  96.84 38.129 96.858 38.165 ;
     RECT  50.832 38.039 51.39 38.173 ;
     RECT  0.54 38.173 0.558 38.237 ;
     RECT  98.244 38.129 100.206 38.399 ;
     RECT  102.564 37.531 102.582 38.435 ;
     RECT  100.944 38.129 100.998 38.515 ;
     RECT  2.415 37.895 2.697 38.635 ;
     RECT  2.304 38.635 2.697 38.705 ;
     RECT  4.536 38.165 4.554 38.713 ;
     RECT  50.832 38.173 51.606 38.821 ;
     RECT  52.488 37.319 52.506 38.821 ;
     RECT  100.944 38.515 101.178 38.827 ;
     RECT  94.215 37.967 94.497 38.923 ;
     RECT  50.832 38.821 52.506 38.939 ;
     RECT  49.32 38.641 49.338 38.947 ;
     RECT  97.236 38.923 97.254 38.975 ;
     RECT  4.032 38.713 4.554 39.067 ;
     RECT  94.215 38.923 94.662 39.091 ;
     RECT  98.244 38.399 98.262 39.091 ;
     RECT  6.12 38.821 6.138 39.101 ;
     RECT  92.916 37.327 92.934 39.119 ;
     RECT  100.944 38.827 101.646 39.119 ;
     RECT  94.215 39.091 94.806 39.209 ;
     RECT  98.172 39.091 98.262 39.245 ;
     RECT  98.244 39.245 98.262 39.361 ;
     RECT  99.072 38.399 100.206 39.361 ;
     RECT  100.944 39.119 101.07 39.361 ;
     RECT  4.032 39.067 4.986 39.479 ;
     RECT  97.164 39.289 97.182 39.479 ;
     RECT  98.244 39.361 101.07 39.479 ;
     RECT  2.415 38.705 2.697 39.487 ;
     RECT  4.032 39.479 4.194 39.515 ;
     RECT  95.976 39.181 95.994 39.515 ;
     RECT  2.415 39.487 2.826 39.533 ;
     RECT  4.968 39.479 4.986 39.631 ;
     RECT  3.78 39.631 3.906 39.785 ;
     RECT  94.215 39.209 94.662 39.917 ;
     RECT  2.415 39.533 2.697 39.931 ;
     RECT  45.615 26.321 45.897 39.991 ;
     RECT  49.032 38.947 49.338 40.019 ;
     RECT  98.244 39.479 100.674 40.019 ;
     RECT  98.244 40.019 100.422 40.021 ;
     RECT  4.968 39.631 5.058 40.171 ;
     RECT  5.832 39.631 5.85 40.171 ;
     RECT  3.888 39.785 3.906 40.325 ;
     RECT  50.832 38.939 51.606 40.531 ;
     RECT  49.032 40.019 49.05 40.559 ;
     RECT  96.768 40.507 96.786 40.559 ;
     RECT  94.215 39.917 94.59 40.603 ;
     RECT  50.076 40.171 50.094 40.639 ;
     RECT  50.832 40.531 51.642 40.639 ;
     RECT  45.036 39.991 45.897 40.667 ;
     RECT  4.968 40.171 5.85 40.711 ;
     RECT  97.776 40.021 100.422 40.711 ;
     RECT  50.076 40.639 51.642 40.739 ;
     RECT  4.896 40.711 5.994 40.829 ;
     RECT  50.256 40.739 51.642 40.829 ;
     RECT  97.704 40.711 100.422 40.945 ;
     RECT  94.068 40.603 94.59 40.973 ;
     RECT  2.304 39.931 2.697 40.981 ;
     RECT  97.704 40.945 100.638 40.981 ;
     RECT  102.564 39.253 102.582 40.987 ;
     RECT  2.304 40.981 2.862 41.099 ;
     RECT  97.704 40.981 101.142 41.099 ;
     RECT  102.528 40.987 102.582 41.099 ;
     RECT  95.544 40.981 95.562 41.135 ;
     RECT  50.328 40.829 51.642 41.243 ;
     RECT  97.704 41.099 98.262 41.243 ;
     RECT  3.924 41.215 3.942 41.251 ;
     RECT  4.896 40.829 5.85 41.251 ;
     RECT  7.815 35.465 8.097 41.251 ;
     RECT  96.408 41.251 96.426 41.369 ;
     RECT  3.78 41.251 4.086 41.405 ;
     RECT  3.924 41.405 4.086 41.563 ;
     RECT  4.86 41.251 5.85 41.563 ;
     RECT  3.924 41.563 5.85 41.597 ;
     RECT  3.996 41.597 5.85 41.675 ;
     RECT  99.615 41.099 101.142 41.675 ;
     RECT  4.248 41.675 5.85 41.791 ;
     RECT  101.052 41.675 101.142 41.851 ;
     RECT  50.328 41.243 51.297 41.881 ;
     RECT  97.164 41.611 97.182 41.899 ;
     RECT  49.032 41.341 49.05 41.909 ;
     RECT  101.052 41.851 101.718 41.909 ;
     RECT  4.248 41.791 6.066 41.945 ;
     RECT  45.615 40.667 45.897 41.947 ;
     RECT  98.244 41.243 98.262 41.989 ;
     RECT  13.215 2.413 13.497 42.025 ;
     RECT  24.015 2.413 24.297 42.025 ;
     RECT  34.815 2.413 35.097 42.025 ;
     RECT  7.596 41.251 8.097 42.061 ;
     RECT  50.22 41.881 51.297 42.061 ;
     RECT  99.615 41.675 100.278 42.061 ;
     RECT  13.104 42.025 13.497 42.077 ;
     RECT  23.904 42.025 24.297 42.077 ;
     RECT  34.704 42.025 35.097 42.077 ;
     RECT  42.768 41.947 42.786 42.077 ;
     RECT  101.7 41.909 101.718 42.089 ;
     RECT  50.22 42.061 51.354 42.139 ;
     RECT  7.596 42.061 8.55 42.179 ;
     RECT  45.615 41.947 46.53 42.179 ;
     RECT  99.108 42.061 100.278 42.179 ;
     RECT  97.02 41.899 97.182 42.331 ;
     RECT  98.172 41.989 98.262 42.331 ;
     RECT  4.572 41.945 6.066 42.359 ;
     RECT  7.596 42.179 8.097 42.365 ;
     RECT  99.615 42.179 100.278 42.421 ;
     RECT  6.804 42.151 6.822 42.449 ;
     RECT  97.02 42.331 98.262 42.449 ;
     RECT  50.22 42.139 51.606 42.565 ;
     RECT  52.488 38.939 52.506 42.565 ;
     RECT  95.724 42.493 95.742 42.565 ;
     RECT  97.164 42.449 98.262 42.565 ;
     RECT  95.724 42.565 95.994 42.601 ;
     RECT  90.684 42.493 90.702 42.629 ;
     RECT  94.068 40.973 94.497 42.629 ;
     RECT  99.615 42.421 100.314 42.691 ;
     RECT  95.652 42.601 95.994 42.715 ;
     RECT  4.644 42.359 6.066 42.719 ;
     RECT  50.22 42.565 52.506 42.719 ;
     RECT  3.78 42.601 3.798 42.755 ;
     RECT  95.508 42.715 95.994 42.755 ;
     RECT  99.615 42.691 101.034 42.989 ;
     RECT  2.304 41.099 2.697 43.025 ;
     RECT  97.164 42.565 98.874 43.025 ;
     RECT  94.215 42.629 94.497 43.069 ;
     RECT  102.564 41.099 102.582 43.147 ;
     RECT  50.22 42.719 51.606 43.169 ;
     RECT  94.215 43.069 94.662 43.169 ;
     RECT  52.488 42.719 52.506 43.231 ;
     RECT  53.712 23.009 53.73 43.231 ;
     RECT  56.415 2.413 56.697 43.231 ;
     RECT  67.215 2.413 67.497 43.231 ;
     RECT  78.015 2.413 78.297 43.231 ;
     RECT  88.815 2.413 89.097 43.231 ;
     RECT  102.528 43.147 102.582 43.259 ;
     RECT  52.488 43.231 53.73 43.277 ;
     RECT  56.304 43.231 56.697 43.277 ;
     RECT  67.104 43.231 67.497 43.277 ;
     RECT  77.904 43.231 78.297 43.277 ;
     RECT  88.704 43.231 89.097 43.277 ;
     RECT  97.308 43.025 98.874 43.303 ;
     RECT  99.615 42.989 100.314 43.303 ;
     RECT  97.308 43.303 100.314 43.325 ;
     RECT  50.724 43.169 51.606 43.331 ;
     RECT  97.56 43.325 100.314 43.331 ;
     RECT  0.54 43.267 0.558 43.421 ;
     RECT  4.176 43.141 4.626 43.529 ;
     RECT  50.724 43.331 51.354 43.529 ;
     RECT  4.176 43.529 4.266 43.565 ;
     RECT  4.248 43.565 4.266 43.601 ;
     RECT  5.4 42.719 6.066 43.709 ;
     RECT  2.415 43.025 2.697 43.807 ;
     RECT  97.56 43.331 100.062 43.835 ;
     RECT  7.815 42.365 8.097 43.843 ;
     RECT  95.976 42.755 95.994 43.843 ;
     RECT  2.415 43.807 2.79 43.853 ;
     RECT  7.815 43.843 8.19 43.901 ;
     RECT  95.976 43.843 96.426 43.901 ;
     RECT  6.804 43.807 6.822 44.069 ;
     RECT  5.4 43.709 5.706 44.105 ;
     RECT  97.56 43.835 98.19 44.105 ;
     RECT  99.18 43.835 100.062 44.141 ;
     RECT  99.615 44.141 100.062 44.185 ;
     RECT  2.415 43.853 2.697 44.251 ;
     RECT  4.176 44.311 4.194 44.347 ;
     RECT  2.304 44.251 2.697 44.375 ;
     RECT  97.704 44.105 98.19 44.375 ;
     RECT  4.176 44.347 4.482 44.383 ;
     RECT  52.488 43.277 52.542 44.491 ;
     RECT  53.712 43.277 53.73 44.491 ;
     RECT  95.976 43.901 95.994 44.609 ;
     RECT  4.176 44.383 4.626 44.645 ;
     RECT  99.615 44.185 100.17 44.761 ;
     RECT  101.16 43.141 101.178 44.761 ;
     RECT  95.832 44.725 95.85 44.765 ;
     RECT  96.768 44.761 96.93 44.851 ;
     RECT  102.564 43.259 102.582 44.875 ;
     RECT  5.4 44.105 5.598 44.879 ;
     RECT  96.768 44.851 96.966 44.915 ;
     RECT  99.615 44.761 101.178 44.915 ;
     RECT  101.16 44.915 101.178 44.951 ;
     RECT  7.815 43.901 8.097 45.019 ;
     RECT  98.172 44.375 98.19 45.031 ;
     RECT  2.34 44.375 2.697 45.115 ;
     RECT  52.488 44.491 53.73 45.121 ;
     RECT  4.536 44.645 4.626 45.265 ;
     RECT  5.4 44.879 5.418 45.265 ;
     RECT  96.912 44.915 96.966 45.293 ;
     RECT  94.215 43.169 94.497 45.301 ;
     RECT  99.615 44.915 100.422 45.301 ;
     RECT  50.832 43.529 51.354 45.329 ;
     RECT  2.304 45.115 2.697 45.455 ;
     RECT  7.704 45.019 8.097 45.455 ;
     RECT  8.892 45.463 8.91 45.599 ;
     RECT  99.36 45.301 100.422 45.661 ;
     RECT  6.804 45.391 6.822 45.689 ;
     RECT  102.528 44.875 102.582 45.689 ;
     RECT  99.36 45.661 101.07 45.725 ;
     RECT  98.172 45.031 98.586 45.733 ;
     RECT  4.536 45.265 5.418 45.761 ;
     RECT  94.215 45.301 94.662 45.797 ;
     RECT  98.172 45.733 98.622 45.841 ;
     RECT  4.536 45.761 5.31 45.931 ;
     RECT  99.432 45.725 101.07 45.931 ;
     RECT  47.304 45.427 47.322 45.959 ;
     RECT  2.415 45.455 2.697 45.967 ;
     RECT  2.415 45.967 2.826 46.013 ;
     RECT  97.488 45.841 98.622 46.067 ;
     RECT  4.356 45.931 5.31 46.111 ;
     RECT  96.516 45.805 96.534 46.205 ;
     RECT  4.248 46.111 5.31 46.229 ;
     RECT  4.248 46.229 4.266 46.265 ;
     RECT  95.4 46.171 95.418 46.265 ;
     RECT  92.34 43.843 92.358 46.373 ;
     RECT  2.415 46.013 2.697 46.411 ;
     RECT  5.184 46.229 5.31 46.507 ;
     RECT  2.304 46.411 2.697 46.535 ;
     RECT  96.336 46.381 96.354 46.535 ;
     RECT  99.432 45.931 101.178 46.615 ;
     RECT  97.488 46.067 98.19 46.747 ;
     RECT  99.432 46.615 101.214 46.769 ;
     RECT  94.215 45.797 94.497 46.777 ;
     RECT  3.996 46.651 4.014 46.805 ;
     RECT  99.432 46.769 101.178 46.841 ;
     RECT  52.38 45.121 53.73 46.877 ;
     RECT  52.38 46.877 52.686 46.913 ;
     RECT  2.415 46.535 2.697 46.921 ;
     RECT  97.272 46.747 98.19 46.921 ;
     RECT  99.432 46.841 100.35 46.921 ;
     RECT  48.456 45.463 48.474 47.039 ;
     RECT  99.324 46.921 100.35 47.075 ;
     RECT  6.588 46.651 6.606 47.119 ;
     RECT  97.272 46.921 98.406 47.155 ;
     RECT  2.415 46.921 3.006 47.191 ;
     RECT  5.184 46.507 5.67 47.191 ;
     RECT  7.815 45.455 8.097 47.191 ;
     RECT  50.004 46.111 50.022 47.191 ;
     RECT  50.832 45.329 51.297 47.191 ;
     RECT  97.272 47.155 98.442 47.191 ;
     RECT  2.415 47.191 3.366 47.275 ;
     RECT  4.788 47.191 5.67 47.281 ;
     RECT  6.588 47.119 7.038 47.309 ;
     RECT  7.815 47.191 8.334 47.309 ;
     RECT  10.8 47.119 10.818 47.309 ;
     RECT  4.788 47.281 5.706 47.317 ;
     RECT  6.588 47.309 7.002 47.317 ;
     RECT  2.304 47.275 3.366 47.345 ;
     RECT  94.215 46.777 94.662 47.353 ;
     RECT  4.788 47.317 7.002 47.357 ;
     RECT  97.272 47.191 98.55 47.425 ;
     RECT  50.004 47.191 51.297 47.453 ;
     RECT  94.215 47.353 94.698 47.461 ;
     RECT  50.004 47.453 50.022 47.489 ;
     RECT  96.912 47.425 98.55 47.563 ;
     RECT  6.804 47.357 7.002 47.579 ;
     RECT  94.215 47.461 94.77 47.579 ;
     RECT  102.564 45.689 102.582 47.579 ;
     RECT  4.788 47.357 5.706 47.615 ;
     RECT  94.215 47.579 94.698 47.615 ;
     RECT  96.732 47.563 98.55 47.615 ;
     RECT  97.452 47.615 98.55 47.623 ;
     RECT  99.576 47.075 100.35 47.731 ;
     RECT  101.16 46.841 101.178 47.731 ;
     RECT  2.415 47.345 3.366 47.851 ;
     RECT  4.536 47.821 4.554 47.851 ;
     RECT  95.544 47.731 95.562 47.885 ;
     RECT  99.576 47.731 101.214 47.899 ;
     RECT  50.832 47.453 51.297 48.001 ;
     RECT  5.292 47.615 5.49 48.029 ;
     RECT  2.415 47.851 4.554 48.119 ;
     RECT  50.832 48.001 51.606 48.119 ;
     RECT  6.984 47.579 7.002 48.127 ;
     RECT  46.8 47.191 46.818 48.127 ;
     RECT  46.764 48.127 46.818 48.227 ;
     RECT  6.984 48.127 7.074 48.263 ;
     RECT  52.488 46.913 52.614 48.271 ;
     RECT  97.452 47.623 98.586 48.271 ;
     RECT  99.576 47.899 101.718 48.271 ;
     RECT  97.452 48.271 101.718 48.299 ;
     RECT  6.984 48.263 7.002 48.317 ;
     RECT  3.456 48.119 4.554 48.425 ;
     RECT  97.452 48.299 101.178 48.425 ;
     RECT  4.536 48.425 4.554 48.569 ;
     RECT  2.415 48.119 2.697 48.571 ;
     RECT  6.228 48.541 6.246 48.659 ;
     RECT  52.38 48.271 52.614 48.659 ;
     RECT  97.452 48.425 100.422 48.667 ;
     RECT  2.304 48.571 2.697 48.695 ;
     RECT  5.436 48.029 5.49 48.929 ;
     RECT  97.272 48.667 100.422 48.929 ;
     RECT  97.272 48.929 97.29 48.965 ;
     RECT  0.108 48.937 0.126 49.037 ;
     RECT  2.415 48.695 2.697 49.081 ;
     RECT  2.415 49.081 2.754 49.435 ;
     RECT  4.572 48.811 4.59 49.435 ;
     RECT  7.815 47.309 8.097 49.441 ;
     RECT  7.815 49.441 8.298 49.477 ;
     RECT  48.456 48.667 48.474 49.477 ;
     RECT  2.304 49.435 2.754 49.505 ;
     RECT  5.76 49.351 5.778 49.505 ;
     RECT  7.815 49.477 8.37 49.517 ;
     RECT  47.88 49.477 48.474 49.549 ;
     RECT  7.815 49.517 8.298 49.613 ;
     RECT  4.428 49.435 4.59 49.621 ;
     RECT  52.38 48.659 52.506 49.649 ;
     RECT  3.924 49.621 4.59 49.711 ;
     RECT  46.8 48.227 46.818 49.739 ;
     RECT  96.336 49.675 96.354 49.739 ;
     RECT  50.832 48.119 51.39 49.747 ;
     RECT  47.88 49.549 49.05 49.811 ;
     RECT  98.172 48.929 100.314 49.819 ;
     RECT  101.16 48.425 101.178 49.819 ;
     RECT  2.415 49.505 2.754 49.855 ;
     RECT  50.724 49.747 51.39 49.855 ;
     RECT  3.924 49.711 5.13 49.891 ;
     RECT  3.852 49.891 5.13 49.919 ;
     RECT  97.272 49.891 97.29 49.981 ;
     RECT  98.172 49.819 101.178 49.981 ;
     RECT  3.852 49.919 3.87 50.045 ;
     RECT  97.272 49.981 101.178 50.045 ;
     RECT  2.415 49.855 2.826 50.287 ;
     RECT  5.076 49.919 5.13 50.302 ;
     RECT  97.992 50.045 101.178 50.315 ;
     RECT  2.412 50.287 2.826 50.431 ;
     RECT  5.904 49.891 5.922 50.431 ;
     RECT  100.908 50.315 101.178 50.431 ;
     RECT  102.564 48.331 102.582 50.491 ;
     RECT  5.652 50.431 6.462 50.549 ;
     RECT  47.88 49.811 48.474 50.549 ;
     RECT  50.292 49.855 51.39 50.549 ;
     RECT  2.412 50.431 3.15 50.585 ;
     RECT  97.992 50.315 99.897 50.693 ;
     RECT  102.024 50.491 102.582 50.729 ;
     RECT  2.412 50.585 3.114 50.731 ;
     RECT  49.212 50.701 49.23 50.819 ;
     RECT  100.908 50.431 101.214 50.819 ;
     RECT  97.992 50.693 98.73 50.827 ;
     RECT  97.776 50.827 98.73 50.935 ;
     RECT  102.564 50.729 102.582 50.963 ;
     RECT  47.88 50.549 47.898 51.061 ;
     RECT  47.304 51.061 47.898 51.089 ;
     RECT  5.688 50.549 6.462 51.169 ;
     RECT  97.056 50.935 98.73 51.293 ;
     RECT  101.016 50.819 101.214 51.355 ;
     RECT  92.34 51.061 92.358 51.359 ;
     RECT  2.304 50.731 3.114 51.395 ;
     RECT  5.688 51.169 6.822 51.395 ;
     RECT  5.904 51.395 6.822 51.403 ;
     RECT  94.215 47.615 94.497 51.403 ;
     RECT  4.248 51.307 4.266 51.511 ;
     RECT  97.38 51.293 98.73 51.511 ;
     RECT  99.54 50.693 99.897 51.511 ;
     RECT  5.904 51.403 6.858 51.539 ;
     RECT  50.292 50.549 51.297 51.539 ;
     RECT  5.904 51.539 6.462 51.629 ;
     RECT  97.38 51.511 100.17 51.629 ;
     RECT  94.215 51.403 94.59 51.637 ;
     RECT  96.264 51.475 96.282 51.665 ;
     RECT  101.016 51.355 101.61 51.745 ;
     RECT  4.032 51.511 4.41 51.781 ;
     RECT  99.615 51.629 100.17 51.781 ;
     RECT  100.908 51.745 101.61 51.781 ;
     RECT  52.488 49.649 52.506 51.871 ;
     RECT  3.42 51.781 4.41 52.051 ;
     RECT  99.615 51.781 101.61 52.169 ;
     RECT  3.42 52.051 4.59 52.205 ;
     RECT  2.304 51.395 2.697 52.321 ;
     RECT  50.832 51.539 51.297 52.321 ;
     RECT  52.488 51.871 52.686 52.321 ;
     RECT  6.444 51.629 6.462 52.349 ;
     RECT  97.38 51.629 98.838 52.349 ;
     RECT  101.592 52.169 101.61 52.349 ;
     RECT  2.304 52.321 3.114 52.439 ;
     RECT  50.832 52.321 52.794 52.439 ;
     RECT  99.615 52.169 100.746 52.439 ;
     RECT  99.615 52.439 100.062 52.475 ;
     RECT  3.852 52.205 4.59 52.591 ;
     RECT  47.304 51.089 47.322 52.619 ;
     RECT  48.96 51.403 48.978 52.681 ;
     RECT  98.172 52.349 98.838 52.709 ;
     RECT  102.564 51.787 102.582 52.709 ;
     RECT  94.215 51.637 94.662 52.717 ;
     RECT  97.164 52.411 97.182 52.745 ;
     RECT  98.172 52.709 98.694 52.745 ;
     RECT  7.815 49.613 8.097 52.825 ;
     RECT  98.172 52.745 98.622 52.889 ;
     RECT  95.832 52.549 95.85 52.951 ;
     RECT  48.96 52.681 49.122 52.979 ;
     RECT  94.215 52.717 94.806 52.979 ;
     RECT  2.304 52.439 2.697 53.015 ;
     RECT  3.852 52.591 5.022 53.015 ;
     RECT  7.704 52.825 8.097 53.021 ;
     RECT  102.6 52.987 102.618 53.117 ;
     RECT  3.924 53.015 5.022 53.131 ;
     RECT  5.796 52.411 5.814 53.131 ;
     RECT  95.76 52.951 95.85 53.131 ;
     RECT  95.76 53.131 96.102 53.285 ;
     RECT  49.032 52.979 49.086 53.429 ;
     RECT  95.976 53.285 96.102 53.519 ;
     RECT  3.924 53.131 5.814 53.555 ;
     RECT  95.976 53.519 95.994 53.555 ;
     RECT  98.172 52.889 98.442 53.671 ;
     RECT  99.615 52.475 99.897 53.671 ;
     RECT  52.488 52.439 52.794 53.699 ;
     RECT  2.415 53.015 2.697 53.755 ;
     RECT  49.032 53.429 49.05 53.789 ;
     RECT  94.215 52.979 94.662 53.869 ;
     RECT  4.536 53.555 5.814 53.905 ;
     RECT  7.815 53.021 8.097 53.905 ;
     RECT  97.668 53.671 98.442 53.905 ;
     RECT  97.308 53.905 98.442 53.941 ;
     RECT  94.215 53.869 94.698 53.969 ;
     RECT  2.376 53.755 2.697 54.031 ;
     RECT  97.308 53.941 98.478 54.031 ;
     RECT  99.396 53.671 100.062 54.031 ;
     RECT  7.2 53.905 8.097 54.043 ;
     RECT  7.056 54.043 8.097 54.059 ;
     RECT  102.564 53.515 102.582 54.059 ;
     RECT  4.536 53.905 6.246 54.067 ;
     RECT  7.056 54.059 7.074 54.067 ;
     RECT  4.536 54.067 7.074 54.095 ;
     RECT  97.308 54.031 100.062 54.103 ;
     RECT  2.376 54.031 3.258 54.131 ;
     RECT  97.164 54.103 100.062 54.131 ;
     RECT  101.16 52.951 101.178 54.175 ;
     RECT  99.615 54.131 100.062 54.211 ;
     RECT  101.16 54.175 101.214 54.211 ;
     RECT  0.108 54.067 0.126 54.221 ;
     RECT  4.536 54.095 6.93 54.329 ;
     RECT  97.164 54.131 98.802 54.329 ;
     RECT  99.615 54.211 101.214 54.379 ;
     RECT  97.452 54.329 98.802 54.401 ;
     RECT  99.615 54.379 101.502 54.509 ;
     RECT  6.912 54.329 6.93 54.869 ;
     RECT  99.615 54.509 101.178 54.869 ;
     RECT  102.564 54.811 102.582 54.869 ;
     RECT  3.564 54.751 3.582 54.905 ;
     RECT  91.224 52.951 91.242 54.949 ;
     RECT  90.648 54.949 91.242 54.977 ;
     RECT  50.832 52.439 51.297 55.021 ;
     RECT  94.215 53.969 94.662 55.021 ;
     RECT  90.648 54.977 90.666 55.049 ;
     RECT  2.412 54.131 2.697 55.051 ;
     RECT  101.088 54.869 101.178 55.139 ;
     RECT  2.304 55.051 2.697 55.175 ;
     RECT  94.215 55.021 95.382 55.175 ;
     RECT  50.832 55.021 51.606 55.255 ;
     RECT  4.536 54.329 5.958 55.277 ;
     RECT  103.572 54.679 103.59 55.277 ;
     RECT  3.852 55.291 4.158 55.409 ;
     RECT  50.832 55.255 51.714 55.409 ;
     RECT  3.852 55.409 3.87 55.445 ;
     RECT  2.415 55.175 2.697 55.561 ;
     RECT  99.615 54.869 99.897 55.561 ;
     RECT  101.088 55.139 101.106 55.795 ;
     RECT  6.84 55.651 6.858 55.819 ;
     RECT  97.452 54.401 98.37 55.819 ;
     RECT  4.968 55.277 5.958 55.831 ;
     RECT  6.84 55.819 7.038 55.831 ;
     RECT  52.488 53.699 52.506 55.831 ;
     RECT  99.216 55.561 99.897 55.831 ;
     RECT  100.908 55.795 101.106 55.831 ;
     RECT  4.968 55.831 7.038 55.859 ;
     RECT  2.415 55.561 2.826 55.915 ;
     RECT  4.968 55.859 6.246 55.949 ;
     RECT  2.304 55.915 2.826 55.985 ;
     RECT  7.815 54.059 8.097 56.059 ;
     RECT  7.815 56.059 8.19 56.101 ;
     RECT  99.216 55.831 101.106 56.101 ;
     RECT  7.815 56.101 8.37 56.219 ;
     RECT  99.216 56.101 101.142 56.255 ;
     RECT  99.216 56.255 100.926 56.291 ;
     RECT  2.415 55.985 2.826 56.347 ;
     RECT  97.308 55.819 98.37 56.371 ;
     RECT  4.968 55.949 5.814 56.489 ;
     RECT  94.215 55.175 95.202 56.489 ;
     RECT  97.308 56.371 98.694 56.525 ;
     RECT  2.415 56.347 3.078 56.641 ;
     RECT  50.832 55.409 51.297 56.641 ;
     RECT  97.308 56.525 98.118 56.641 ;
     RECT  96.048 56.605 96.066 56.669 ;
     RECT  4.968 56.489 5.274 56.731 ;
     RECT  2.415 56.641 3.258 56.759 ;
     RECT  2.415 56.759 2.697 56.767 ;
     RECT  96.984 56.641 98.118 56.795 ;
     RECT  99.432 56.291 100.926 56.795 ;
     RECT  4.896 56.731 5.274 56.803 ;
     RECT  4.356 56.803 5.274 56.911 ;
     RECT  3.42 56.911 5.274 57.029 ;
     RECT  3.42 57.029 4.374 57.065 ;
     RECT  4.32 57.065 4.374 57.137 ;
     RECT  50.544 56.641 51.297 57.181 ;
     RECT  99.432 56.795 99.954 57.181 ;
     RECT  49.032 56.803 49.05 57.209 ;
     RECT  2.412 56.767 2.697 57.211 ;
     RECT  97.272 56.795 98.118 57.415 ;
     RECT  98.964 57.181 99.954 57.415 ;
     RECT  6.228 56.911 6.246 57.499 ;
     RECT  7.815 56.219 8.097 57.499 ;
     RECT  5.148 57.029 5.274 57.541 ;
     RECT  6.228 57.499 8.097 57.541 ;
     RECT  3.42 57.065 3.438 57.569 ;
     RECT  5.148 57.541 8.097 57.569 ;
     RECT  97.272 57.415 99.954 57.685 ;
     RECT  101.016 57.145 101.034 57.685 ;
     RECT  50.436 57.181 51.297 57.721 ;
     RECT  101.016 57.685 101.178 57.721 ;
     RECT  102.564 55.675 102.582 57.835 ;
     RECT  47.88 55.921 47.898 57.839 ;
     RECT  94.215 56.489 94.662 57.847 ;
     RECT  5.148 57.569 6.246 57.875 ;
     RECT  4.356 57.137 4.374 58.081 ;
     RECT  5.292 57.875 6.246 58.109 ;
     RECT  102.492 57.835 102.582 58.117 ;
     RECT  2.304 57.211 2.697 58.145 ;
     RECT  5.652 58.109 6.246 58.145 ;
     RECT  7.272 57.569 8.097 58.145 ;
     RECT  97.236 57.685 99.954 58.157 ;
     RECT  95.508 58.123 95.526 58.189 ;
     RECT  3.816 58.081 4.374 58.261 ;
     RECT  97.668 58.157 99.954 58.261 ;
     RECT  100.728 57.721 101.178 58.261 ;
     RECT  93.492 57.847 94.662 58.289 ;
     RECT  102.492 58.117 102.618 58.301 ;
     RECT  50.112 57.721 51.297 58.351 ;
     RECT  3.816 58.261 4.518 58.379 ;
     RECT  49.032 57.991 49.05 58.379 ;
     RECT  3.816 58.379 4.014 58.415 ;
     RECT  95.508 58.189 95.742 58.415 ;
     RECT  94.215 58.289 94.662 58.451 ;
     RECT  5.832 58.145 6.246 58.495 ;
     RECT  52.488 55.831 52.578 58.495 ;
     RECT  53.712 46.877 53.73 58.495 ;
     RECT  2.415 58.145 2.697 58.507 ;
     RECT  95.724 58.415 95.742 58.531 ;
     RECT  5.832 58.495 6.786 58.559 ;
     RECT  97.668 58.261 101.178 58.621 ;
     RECT  6.768 58.559 6.786 58.649 ;
     RECT  2.415 58.507 2.754 58.685 ;
     RECT  95.724 58.531 96.462 58.685 ;
     RECT  97.668 58.621 101.25 58.685 ;
     RECT  102.492 58.301 102.582 58.685 ;
     RECT  97.668 58.685 98.478 58.7 ;
     RECT  99.324 58.685 101.25 58.721 ;
     RECT  97.704 58.7 98.478 58.919 ;
     RECT  2.415 58.685 2.697 58.927 ;
     RECT  3.996 58.415 4.014 58.955 ;
     RECT  5.832 58.559 6.03 59.161 ;
     RECT  98.172 58.919 98.478 59.189 ;
     RECT  4.68 59.197 4.698 59.261 ;
     RECT  98.172 59.189 98.334 59.261 ;
     RECT  50.004 58.351 51.297 59.431 ;
     RECT  4.824 59.341 4.842 59.459 ;
     RECT  3.852 59.233 3.87 59.495 ;
     RECT  99.324 58.721 101.106 59.495 ;
     RECT  5.616 59.161 6.03 59.611 ;
     RECT  5.04 59.611 6.426 59.729 ;
     RECT  49.536 59.431 51.297 59.729 ;
     RECT  5.04 59.729 6.39 59.765 ;
     RECT  49.644 59.729 51.297 59.909 ;
     RECT  47.016 58.117 47.034 59.999 ;
     RECT  96.912 59.881 96.93 60.007 ;
     RECT  98.172 59.261 98.19 60.115 ;
     RECT  2.304 58.927 2.697 60.151 ;
     RECT  98.172 60.115 98.478 60.151 ;
     RECT  99.324 59.495 100.278 60.151 ;
     RECT  49.644 59.909 50.022 60.179 ;
     RECT  97.704 60.151 100.278 60.241 ;
     RECT  102.564 58.685 102.582 60.241 ;
     RECT  2.304 60.151 3.078 60.269 ;
     RECT  97.704 60.241 100.422 60.341 ;
     RECT  4.464 60.331 4.626 60.349 ;
     RECT  96.372 60.007 96.93 60.379 ;
     RECT  97.704 60.341 100.17 60.379 ;
     RECT  96.372 60.379 100.17 60.385 ;
     RECT  4.32 60.349 4.626 60.421 ;
     RECT  101.196 59.845 101.214 60.421 ;
     RECT  102.564 60.241 102.618 60.461 ;
     RECT  3.96 60.421 4.626 60.539 ;
     RECT  5.508 59.765 6.39 60.539 ;
     RECT  96.228 60.385 100.17 60.539 ;
     RECT  100.908 60.421 101.214 60.539 ;
     RECT  3.96 60.539 4.338 60.683 ;
     RECT  50.832 59.909 51.297 60.691 ;
     RECT  5.508 60.539 5.634 60.719 ;
     RECT  52.488 58.495 53.73 60.719 ;
     RECT  50.796 60.691 51.297 60.817 ;
     RECT  100.908 60.539 100.926 60.881 ;
     RECT  6.372 60.539 6.39 60.961 ;
     RECT  6.372 60.961 6.462 61.079 ;
     RECT  54.612 24.467 54.63 61.079 ;
     RECT  96.228 60.539 99.897 61.079 ;
     RECT  94.215 58.451 94.497 61.087 ;
     RECT  3.96 60.683 4.014 61.115 ;
     RECT  5.508 60.719 5.526 61.123 ;
     RECT  2.304 60.269 2.697 61.195 ;
     RECT  5.112 61.123 5.526 61.223 ;
     RECT  2.304 61.195 3.15 61.231 ;
     RECT  54.684 61.087 54.702 61.259 ;
     RECT  96.3 61.079 99.897 61.321 ;
     RECT  96.3 61.321 100.242 61.349 ;
     RECT  96.3 61.349 98.874 61.385 ;
     RECT  97.704 61.385 98.802 61.421 ;
     RECT  101.16 61.321 101.178 61.421 ;
     RECT  5.436 61.223 5.526 61.501 ;
     RECT  6.372 61.079 6.39 61.501 ;
     RECT  53.712 60.719 53.73 61.619 ;
     RECT  2.304 61.231 3.762 61.655 ;
     RECT  49.644 60.179 49.662 61.655 ;
     RECT  94.215 61.087 94.662 61.765 ;
     RECT  90.648 61.627 90.666 61.799 ;
     RECT  94.215 61.765 95.382 61.805 ;
     RECT  98.172 61.421 98.802 61.889 ;
     RECT  96.3 61.385 96.93 61.925 ;
     RECT  5.436 61.501 6.39 61.933 ;
     RECT  45.615 42.179 45.897 61.933 ;
     RECT  94.215 61.805 94.662 61.997 ;
     RECT  2.415 61.655 3.762 62.041 ;
     RECT  99.615 61.349 100.242 62.041 ;
     RECT  2.415 62.041 4.05 62.107 ;
     RECT  102.564 60.461 102.582 62.155 ;
     RECT  99.615 62.041 100.602 62.159 ;
     RECT  102.528 62.155 102.582 62.159 ;
     RECT  5.436 61.933 6.858 62.189 ;
     RECT  45.615 61.933 46.206 62.275 ;
     RECT  99.615 62.159 99.897 62.311 ;
     RECT  2.415 62.107 4.662 62.395 ;
     RECT  5.688 62.189 6.858 62.429 ;
     RECT  45.615 62.275 46.818 62.429 ;
     RECT  52.488 60.719 52.506 62.429 ;
     RECT  2.412 62.395 4.77 62.435 ;
     RECT  2.412 62.435 4.662 62.465 ;
     RECT  5.76 62.429 6.858 62.537 ;
     RECT  5.976 62.537 6.858 62.539 ;
     RECT  50.724 60.817 51.297 62.545 ;
     RECT  100.728 62.311 100.746 62.545 ;
     RECT  102.528 62.159 102.546 62.581 ;
     RECT  5.976 62.539 7.002 62.609 ;
     RECT  102.024 62.581 102.546 62.621 ;
     RECT  2.415 62.465 4.662 62.699 ;
     RECT  5.976 62.609 6.246 62.699 ;
     RECT  4.392 62.699 4.662 62.735 ;
     RECT  6.984 62.609 7.002 62.735 ;
     RECT  2.415 62.699 3.402 62.771 ;
     RECT  4.464 62.735 4.662 62.771 ;
     RECT  96.48 61.925 96.93 62.851 ;
     RECT  98.172 61.889 98.694 62.851 ;
     RECT  99.432 62.311 99.897 62.851 ;
     RECT  100.728 62.545 101.034 62.941 ;
     RECT  6.228 62.699 6.246 62.969 ;
     RECT  47.304 62.671 47.322 62.969 ;
     RECT  102.528 62.621 102.546 62.969 ;
     RECT  100.728 62.941 101.178 63.041 ;
     RECT  50.724 62.545 51.39 63.121 ;
     RECT  96.336 62.851 96.93 63.121 ;
     RECT  98.172 62.851 99.897 63.121 ;
     RECT  96.336 63.121 97.29 63.163 ;
     RECT  95.904 63.163 97.29 63.197 ;
     RECT  95.904 63.197 95.922 63.239 ;
     RECT  98.172 63.121 100.422 63.239 ;
     RECT  96.84 63.197 97.29 63.275 ;
     RECT  0.54 63.247 0.558 63.293 ;
     RECT  96.84 63.275 96.858 63.293 ;
     RECT  4.572 62.771 4.662 63.661 ;
     RECT  2.415 62.771 3.258 63.691 ;
     RECT  4.14 63.661 4.806 63.751 ;
     RECT  3.996 63.751 4.806 63.779 ;
     RECT  45.615 62.429 46.206 63.779 ;
     RECT  99.54 63.239 100.422 63.787 ;
     RECT  99.54 63.787 100.674 63.823 ;
     RECT  99.54 63.823 100.926 63.931 ;
     RECT  3.996 63.779 4.662 64.085 ;
     RECT  5.58 63.661 5.598 64.165 ;
     RECT  99.54 63.931 101.034 64.165 ;
     RECT  2.304 63.691 3.258 64.201 ;
     RECT  6.66 64.129 6.678 64.201 ;
     RECT  45.615 63.779 45.897 64.291 ;
     RECT  99.54 64.165 101.178 64.319 ;
     RECT  4.248 64.085 4.662 64.355 ;
     RECT  99.54 64.319 100.53 64.355 ;
     RECT  5.58 64.165 5.886 64.411 ;
     RECT  6.66 64.201 6.822 64.411 ;
     RECT  98.172 63.239 98.694 64.589 ;
     RECT  2.304 64.201 3.474 64.625 ;
     RECT  98.172 64.589 98.55 64.705 ;
     RECT  50.328 63.121 51.39 64.733 ;
     RECT  99.54 64.355 99.897 64.741 ;
     RECT  97.488 64.705 98.55 64.747 ;
     RECT  50.328 64.733 51.297 64.769 ;
     RECT  5.58 64.411 6.822 64.831 ;
     RECT  96.408 64.741 96.426 64.843 ;
     RECT  45.036 64.291 45.897 64.859 ;
     RECT  96.264 64.843 96.426 64.859 ;
     RECT  96.264 64.859 96.282 64.895 ;
     RECT  97.344 64.747 98.55 64.895 ;
     RECT  5.508 64.831 6.822 64.903 ;
     RECT  7.815 58.145 8.097 64.903 ;
     RECT  2.415 64.625 3.474 64.939 ;
     RECT  4.248 64.355 4.554 64.939 ;
     RECT  0.108 64.939 0.126 65.021 ;
     RECT  5.508 64.903 8.097 65.129 ;
     RECT  99.504 64.741 99.897 65.137 ;
     RECT  97.488 64.895 98.55 65.165 ;
     RECT  102.564 63.019 102.582 65.213 ;
     RECT  99.504 65.137 99.99 65.245 ;
     RECT  99.504 65.245 101.214 65.399 ;
     RECT  99.504 65.399 99.99 65.435 ;
     RECT  49.896 65.011 49.914 65.551 ;
     RECT  51.015 64.769 51.297 65.641 ;
     RECT  102.6 65.515 102.618 65.645 ;
     RECT  98.172 65.165 98.55 65.659 ;
     RECT  49.896 65.551 50.274 65.669 ;
     RECT  51.015 65.641 51.75 65.677 ;
     RECT  98.172 65.659 98.874 65.705 ;
     RECT  5.508 65.129 5.598 65.777 ;
     RECT  2.415 64.939 4.554 65.821 ;
     RECT  50.796 65.677 51.75 65.821 ;
     RECT  46.8 65.749 46.818 65.849 ;
     RECT  2.415 65.821 4.698 65.851 ;
     RECT  50.796 65.821 52.038 65.939 ;
     RECT  101.016 65.399 101.214 65.939 ;
     RECT  2.304 65.851 4.698 65.975 ;
     RECT  6.804 65.129 8.097 66.091 ;
     RECT  51.015 65.939 52.038 66.091 ;
     RECT  5.652 65.983 5.706 66.209 ;
     RECT  4.536 65.975 4.698 66.245 ;
     RECT  101.016 65.939 101.178 66.451 ;
     RECT  100.728 66.451 101.178 66.479 ;
     RECT  100.728 66.479 101.142 66.551 ;
     RECT  2.415 65.975 3.474 66.715 ;
     RECT  94.215 61.997 94.497 66.715 ;
     RECT  94.215 66.715 94.986 66.721 ;
     RECT  99.615 65.435 99.99 66.721 ;
     RECT  49.896 65.669 49.914 66.893 ;
     RECT  2.304 66.715 3.474 66.901 ;
     RECT  97.092 66.715 97.11 66.901 ;
     RECT  98.172 65.705 98.658 66.901 ;
     RECT  102.564 66.043 102.582 66.907 ;
     RECT  6.588 66.091 8.097 66.929 ;
     RECT  9.108 66.829 9.126 66.929 ;
     RECT  2.304 66.901 3.51 66.991 ;
     RECT  5.148 66.631 5.166 66.991 ;
     RECT  45.615 64.859 45.897 66.991 ;
     RECT  5.112 66.991 5.166 67.003 ;
     RECT  102.528 66.907 102.582 67.019 ;
     RECT  7.704 66.929 8.097 67.037 ;
     RECT  94.215 66.721 95.454 67.055 ;
     RECT  98.136 66.901 98.658 67.055 ;
     RECT  2.304 66.991 4.122 67.171 ;
     RECT  5.112 67.003 5.202 67.171 ;
     RECT  97.092 66.901 97.146 67.171 ;
     RECT  2.304 67.171 4.23 67.181 ;
     RECT  52.992 67.135 53.01 67.181 ;
     RECT  96.408 67.171 97.146 67.199 ;
     RECT  96.408 67.199 97.074 67.229 ;
     RECT  98.136 67.055 98.622 67.243 ;
     RECT  51.015 66.091 52.182 67.277 ;
     RECT  98.064 67.243 98.622 67.277 ;
     RECT  98.064 67.277 98.298 67.289 ;
     RECT  96.408 67.229 96.426 67.325 ;
     RECT  101.124 66.551 101.142 67.325 ;
     RECT  99.615 66.721 100.314 67.441 ;
     RECT  45.036 66.991 45.897 67.559 ;
     RECT  52.164 67.277 52.182 67.703 ;
     RECT  51.015 67.277 51.297 67.711 ;
     RECT  5.04 67.171 5.202 67.801 ;
     RECT  99.615 67.441 100.71 67.801 ;
     RECT  6.588 66.929 6.606 67.829 ;
     RECT  52.776 67.711 52.794 67.829 ;
     RECT  99.288 67.801 100.71 67.901 ;
     RECT  2.412 67.181 4.23 67.945 ;
     RECT  5.04 67.801 5.526 67.945 ;
     RECT  95.436 67.055 95.454 67.981 ;
     RECT  2.412 67.945 5.526 68.011 ;
     RECT  94.215 67.055 94.662 68.107 ;
     RECT  95.436 67.981 95.886 68.107 ;
     RECT  2.304 68.011 5.526 68.135 ;
     RECT  94.215 68.107 95.886 68.135 ;
     RECT  99.288 67.901 99.897 68.135 ;
     RECT  100.728 68.071 100.746 68.215 ;
     RECT  98.064 67.289 98.226 68.251 ;
     RECT  96.66 68.251 96.678 68.341 ;
     RECT  94.215 68.135 95.454 68.369 ;
     RECT  50.544 67.711 51.297 68.377 ;
     RECT  98.064 68.251 98.334 68.395 ;
     RECT  6.444 68.347 6.462 68.405 ;
     RECT  94.215 68.369 95.31 68.405 ;
     RECT  96.228 68.341 96.678 68.405 ;
     RECT  96.228 68.405 96.246 68.429 ;
     RECT  0.108 68.377 0.126 68.477 ;
     RECT  2.415 68.135 5.526 68.485 ;
     RECT  2.415 68.485 6.246 68.549 ;
     RECT  5.508 68.549 6.246 68.639 ;
     RECT  46.764 68.521 46.782 68.639 ;
     RECT  97.488 68.395 98.334 68.675 ;
     RECT  97.524 68.675 98.334 68.755 ;
     RECT  2.415 68.549 4.698 68.783 ;
     RECT  94.215 68.405 94.662 68.783 ;
     RECT  100.728 68.215 101.178 68.791 ;
     RECT  2.415 68.783 3.474 68.875 ;
     RECT  102.564 67.019 102.582 68.953 ;
     RECT  102.564 68.953 102.618 69.101 ;
     RECT  97.524 68.755 98.874 69.187 ;
     RECT  99.615 68.135 99.897 69.187 ;
     RECT  4.536 68.783 4.698 69.215 ;
     RECT  97.524 69.187 99.897 69.295 ;
     RECT  100.656 68.791 101.178 69.295 ;
     RECT  5.508 68.639 5.706 69.331 ;
     RECT  2.304 68.875 3.474 69.341 ;
     RECT  5.256 69.331 5.706 69.755 ;
     RECT  97.524 69.295 101.178 69.791 ;
     RECT  95.832 69.835 95.85 69.931 ;
     RECT  7.815 67.037 8.097 69.961 ;
     RECT  95.688 69.931 95.85 69.961 ;
     RECT  50.184 68.377 51.297 69.989 ;
     RECT  95.292 69.961 95.85 69.989 ;
     RECT  47.304 69.691 47.322 69.997 ;
     RECT  6.552 69.727 6.57 70.061 ;
     RECT  7.416 69.961 8.097 70.061 ;
     RECT  5.292 69.755 5.706 70.069 ;
     RECT  97.524 69.791 100.89 70.069 ;
     RECT  5.292 70.069 6.246 70.109 ;
     RECT  50.184 69.989 50.202 70.133 ;
     RECT  2.415 69.341 3.474 70.171 ;
     RECT  6.228 70.109 6.246 70.259 ;
     RECT  97.164 70.069 100.89 70.259 ;
     RECT  5.292 70.109 5.454 70.295 ;
     RECT  95.292 69.989 95.31 70.295 ;
     RECT  97.164 70.259 97.182 70.295 ;
     RECT  98.172 70.259 99.99 70.295 ;
     RECT  2.304 70.171 3.474 70.411 ;
     RECT  4.536 70.267 4.554 70.411 ;
     RECT  51.015 69.989 51.297 70.411 ;
     RECT  90.648 70.105 90.666 70.439 ;
     RECT  96.228 70.405 96.246 70.445 ;
     RECT  2.304 70.411 3.582 70.565 ;
     RECT  100.728 70.259 100.89 70.645 ;
     RECT  4.5 70.411 4.554 70.699 ;
     RECT  100.728 70.645 101.214 70.799 ;
     RECT  2.304 70.565 3.546 70.835 ;
     RECT  100.728 70.799 100.746 70.835 ;
     RECT  51.015 70.411 51.354 70.951 ;
     RECT  4.5 70.699 4.986 71.069 ;
     RECT  0.108 71.035 0.126 71.165 ;
     RECT  98.172 70.295 99.954 71.213 ;
     RECT  4.5 71.069 4.662 71.221 ;
     RECT  99.18 71.213 99.954 71.221 ;
     RECT  102.564 69.101 102.582 71.227 ;
     RECT  50.904 70.951 51.354 71.311 ;
     RECT  96.3 71.041 96.318 71.339 ;
     RECT  4.464 71.221 4.662 71.347 ;
     RECT  99.18 71.221 100.494 71.375 ;
     RECT  2.415 70.835 3.546 71.491 ;
     RECT  4.356 71.347 4.662 71.491 ;
     RECT  2.415 71.491 4.662 71.609 ;
     RECT  99.576 71.375 100.494 71.609 ;
     RECT  99.576 71.609 99.897 71.645 ;
     RECT  102.528 71.227 102.582 71.659 ;
     RECT  2.415 71.609 4.626 71.717 ;
     RECT  7.815 70.061 8.097 71.725 ;
     RECT  7.704 71.725 8.097 71.789 ;
     RECT  102.024 71.659 102.582 71.789 ;
     RECT  96.156 71.455 96.174 71.803 ;
     RECT  95.508 71.803 96.174 71.837 ;
     RECT  5.724 71.581 5.742 71.879 ;
     RECT  100.908 71.725 100.926 71.879 ;
     RECT  2.415 71.717 4.59 71.899 ;
     RECT  47.016 69.997 47.322 71.915 ;
     RECT  97.344 71.491 97.362 71.915 ;
     RECT  95.508 71.837 95.67 72.149 ;
     RECT  95.508 72.149 95.526 72.185 ;
     RECT  50.724 71.311 51.354 72.301 ;
     RECT  98.172 71.213 98.19 72.301 ;
     RECT  98.172 72.301 98.586 72.419 ;
     RECT  2.304 71.899 4.59 72.455 ;
     RECT  96.912 72.301 96.93 72.455 ;
     RECT  4.248 72.455 4.59 72.571 ;
     RECT  99.615 71.645 99.897 72.661 ;
     RECT  48.456 71.041 48.474 72.689 ;
     RECT  4.248 72.571 4.698 72.725 ;
     RECT  99.615 72.661 100.422 72.761 ;
     RECT  99.615 72.761 99.897 72.841 ;
     RECT  5.472 72.571 5.49 72.931 ;
     RECT  102.564 71.789 102.582 72.931 ;
     RECT  7.815 71.789 8.097 72.955 ;
     RECT  102.564 72.931 102.618 72.989 ;
     RECT  97.02 72.907 97.074 73.075 ;
     RECT  49.644 72.841 49.662 73.103 ;
     RECT  50.724 72.301 51.642 73.111 ;
     RECT  2.34 72.455 3.474 73.195 ;
     RECT  101.16 72.301 101.178 73.201 ;
     RECT  6.984 73.111 7.002 73.229 ;
     RECT  100.728 73.201 101.178 73.229 ;
     RECT  2.304 73.195 3.474 73.265 ;
     RECT  4.824 72.931 5.49 73.265 ;
     RECT  5.472 73.265 5.49 73.381 ;
     RECT  7.815 72.955 8.19 73.381 ;
     RECT  97.02 73.075 97.254 73.381 ;
     RECT  98.172 72.419 98.334 73.381 ;
     RECT  99.324 72.841 99.897 73.381 ;
     RECT  2.415 73.265 3.474 73.471 ;
     RECT  96.876 73.381 97.254 73.471 ;
     RECT  7.815 73.381 8.37 73.499 ;
     RECT  47.304 71.915 47.322 73.499 ;
     RECT  50.724 73.111 51.894 73.499 ;
     RECT  98.172 73.381 99.897 73.499 ;
     RECT  98.172 73.499 98.802 73.535 ;
     RECT  50.724 73.499 51.642 73.651 ;
     RECT  98.172 73.535 98.19 73.651 ;
     RECT  0.54 73.507 0.558 73.661 ;
     RECT  96.156 73.471 97.254 73.921 ;
     RECT  97.992 73.651 98.19 73.921 ;
     RECT  99.615 73.499 99.897 73.921 ;
     RECT  100.728 73.229 100.746 73.921 ;
     RECT  2.415 73.471 3.906 74.047 ;
     RECT  5.472 73.381 5.634 74.047 ;
     RECT  49.068 73.237 49.086 74.047 ;
     RECT  96.156 73.921 98.19 74.075 ;
     RECT  2.415 74.047 4.482 74.083 ;
     RECT  96.156 74.075 97.254 74.147 ;
     RECT  99.615 73.921 100.746 74.155 ;
     RECT  5.472 74.047 5.778 74.191 ;
     RECT  5.472 74.191 6.498 74.219 ;
     RECT  94.215 68.783 94.497 74.281 ;
     RECT  98.172 74.075 98.19 74.299 ;
     RECT  49.032 74.047 49.086 74.309 ;
     RECT  50.544 73.651 51.642 74.309 ;
     RECT  2.415 74.083 4.626 74.345 ;
     RECT  98.172 74.299 98.874 74.345 ;
     RECT  94.215 74.281 94.662 74.453 ;
     RECT  4.5 74.345 4.626 74.489 ;
     RECT  2.415 74.345 3.474 74.491 ;
     RECT  52.092 74.461 52.11 74.579 ;
     RECT  50.544 74.309 51.297 74.587 ;
     RECT  2.304 74.491 3.474 74.615 ;
     RECT  97.236 74.147 97.254 74.669 ;
     RECT  5.472 74.219 5.706 74.849 ;
     RECT  4.5 74.489 4.518 74.885 ;
     RECT  98.172 74.345 98.766 74.885 ;
     RECT  102.564 72.989 102.582 75.115 ;
     RECT  50.472 74.587 51.297 75.119 ;
     RECT  99.615 74.155 101.178 75.119 ;
     RECT  2.34 74.615 3.474 75.355 ;
     RECT  96.156 74.147 96.174 75.361 ;
     RECT  49.068 74.309 49.086 75.389 ;
     RECT  2.304 75.355 3.474 75.425 ;
     RECT  5.328 75.091 5.346 75.425 ;
     RECT  6.48 74.219 6.498 75.505 ;
     RECT  2.34 75.425 3.474 75.541 ;
     RECT  6.48 75.505 6.534 75.581 ;
     RECT  2.34 75.541 3.582 75.811 ;
     RECT  95.868 75.361 96.174 75.835 ;
     RECT  95.724 75.835 96.174 75.965 ;
     RECT  96.948 75.541 96.966 76.009 ;
     RECT  99.615 75.119 100.926 76.009 ;
     RECT  96.372 76.009 96.966 76.045 ;
     RECT  98.964 76.009 100.926 76.045 ;
     RECT  2.34 75.811 3.726 76.081 ;
     RECT  4.752 75.811 4.77 76.081 ;
     RECT  96.372 76.045 97.074 76.081 ;
     RECT  98.172 74.885 98.19 76.081 ;
     RECT  98.964 76.045 101.178 76.081 ;
     RECT  50.544 75.119 51.297 76.109 ;
     RECT  102.024 75.115 102.582 76.109 ;
     RECT  6.48 75.581 6.498 76.199 ;
     RECT  96.372 76.081 101.178 76.271 ;
     RECT  2.34 76.081 3.798 76.351 ;
     RECT  4.644 76.081 4.77 76.351 ;
     RECT  2.34 76.351 4.914 76.363 ;
     RECT  49.032 76.207 49.05 76.469 ;
     RECT  2.34 76.363 5.202 76.505 ;
     RECT  50.58 76.109 51.297 76.577 ;
     RECT  47.304 75.361 47.322 76.649 ;
     RECT  96.372 76.271 100.314 76.649 ;
     RECT  2.34 76.505 3.474 76.651 ;
     RECT  97.524 76.649 100.314 76.739 ;
     RECT  96.372 76.649 96.606 76.747 ;
     RECT  95.76 76.747 96.606 76.775 ;
     RECT  4.644 76.505 5.202 76.819 ;
     RECT  97.524 76.739 98.622 77.009 ;
     RECT  101.196 76.855 101.214 77.009 ;
     RECT  4.644 76.819 5.382 77.045 ;
     RECT  6.984 77.08 7.002 77.117 ;
     RECT  2.304 76.651 3.474 77.153 ;
     RECT  95.76 76.775 95.778 77.153 ;
     RECT  99.615 76.739 100.314 77.251 ;
     RECT  97.524 77.009 98.19 77.315 ;
     RECT  99.615 77.251 100.422 77.431 ;
     RECT  2.412 77.153 3.474 77.585 ;
     RECT  2.415 77.585 3.474 77.701 ;
     RECT  4.644 77.045 5.13 77.701 ;
     RECT  99.615 77.431 100.602 77.701 ;
     RECT  102.564 76.109 102.582 77.701 ;
     RECT  102.024 77.701 102.582 77.741 ;
     RECT  50.652 76.577 51.297 77.791 ;
     RECT  2.415 77.701 3.726 77.819 ;
     RECT  98.964 77.701 100.602 77.819 ;
     RECT  50.148 77.791 51.297 77.863 ;
     RECT  4.5 77.701 5.13 77.935 ;
     RECT  98.172 77.315 98.19 77.935 ;
     RECT  6.624 77.701 6.642 77.971 ;
     RECT  45.615 67.559 45.897 77.971 ;
     RECT  99.615 77.819 100.602 77.971 ;
     RECT  98.172 77.935 98.802 77.981 ;
     RECT  4.5 77.935 5.67 78.061 ;
     RECT  2.415 77.819 3.582 78.077 ;
     RECT  6.624 77.971 6.858 78.089 ;
     RECT  50.148 77.863 51.498 78.089 ;
     RECT  99.615 77.971 101.178 78.125 ;
     RECT  98.172 77.981 98.478 78.205 ;
     RECT  4.392 78.061 5.67 78.233 ;
     RECT  94.215 74.453 94.497 78.241 ;
     RECT  4.392 78.233 5.346 78.359 ;
     RECT  97.668 78.205 98.478 78.367 ;
     RECT  2.415 78.077 3.474 78.379 ;
     RECT  4.392 78.359 4.554 78.395 ;
     RECT  96.588 76.775 96.606 78.431 ;
     RECT  50.148 78.089 51.297 78.511 ;
     RECT  45.036 77.971 45.897 78.539 ;
     RECT  102.564 77.741 102.582 78.571 ;
     RECT  49.968 78.511 51.297 78.629 ;
     RECT  99.615 78.125 101.142 78.629 ;
     RECT  102.024 78.571 102.582 78.629 ;
     RECT  6.516 78.205 6.534 78.665 ;
     RECT  97.452 78.367 98.478 78.665 ;
     RECT  94.215 78.241 94.662 78.667 ;
     RECT  43.884 76.981 43.902 78.809 ;
     RECT  6.228 78.781 6.246 78.899 ;
     RECT  50.076 78.629 51.297 78.899 ;
     RECT  94.215 78.667 95.058 78.899 ;
     RECT  2.304 78.379 3.474 78.935 ;
     RECT  5.328 78.359 5.346 78.935 ;
     RECT  51.015 78.899 51.297 79.015 ;
     RECT  2.415 78.935 3.474 79.051 ;
     RECT  96.516 78.601 96.534 79.051 ;
     RECT  54.684 78.907 54.702 79.079 ;
     RECT  90.648 78.907 90.666 79.079 ;
     RECT  2.415 79.051 3.582 79.205 ;
     RECT  95.976 79.051 96.534 79.205 ;
     RECT  0.108 79.213 0.126 79.277 ;
     RECT  97.452 78.665 98.19 79.285 ;
     RECT  100.728 78.629 101.142 79.285 ;
     RECT  97.344 79.285 98.19 79.313 ;
     RECT  4.5 78.395 4.554 79.321 ;
     RECT  98.172 79.313 98.19 79.435 ;
     RECT  51.015 79.015 51.39 79.439 ;
     RECT  100.728 79.285 101.214 79.439 ;
     RECT  2.415 79.205 3.51 79.475 ;
     RECT  98.172 79.435 98.622 79.475 ;
     RECT  94.215 78.899 94.662 79.547 ;
     RECT  99.615 78.629 99.897 79.555 ;
     RECT  99.615 79.555 99.99 79.591 ;
     RECT  2.415 79.475 3.474 79.675 ;
     RECT  97.344 79.313 97.362 79.681 ;
     RECT  50.076 78.899 50.238 79.709 ;
     RECT  2.412 79.675 3.474 79.745 ;
     RECT  97.272 79.681 97.362 79.745 ;
     RECT  99.576 79.591 100.422 79.745 ;
     RECT  4.32 79.321 4.554 79.819 ;
     RECT  5.508 79.177 5.526 79.819 ;
     RECT  4.32 79.819 5.526 79.853 ;
     RECT  97.272 79.745 97.29 79.853 ;
     RECT  51.015 79.439 51.297 79.951 ;
     RECT  96.516 79.205 96.534 80.221 ;
     RECT  50.904 79.951 51.297 80.249 ;
     RECT  98.172 79.475 98.514 80.249 ;
     RECT  50.076 79.709 50.094 80.429 ;
     RECT  4.536 79.853 5.526 80.491 ;
     RECT  96.516 80.221 97.254 80.519 ;
     RECT  98.172 80.249 98.262 80.519 ;
     RECT  101.16 79.439 101.178 80.519 ;
     RECT  2.415 79.745 3.474 80.527 ;
     RECT  98.172 80.519 98.226 80.629 ;
     RECT  6.876 80.527 6.894 80.635 ;
     RECT  99.615 79.745 99.897 80.635 ;
     RECT  96.372 80.629 96.39 80.669 ;
     RECT  2.304 80.527 3.474 80.671 ;
     RECT  4.536 80.491 5.994 80.671 ;
     RECT  97.236 80.519 97.254 80.671 ;
     RECT  98.1 80.629 98.226 80.671 ;
     RECT  99.615 80.635 100.278 80.671 ;
     RECT  2.304 80.671 5.994 80.789 ;
     RECT  99.036 80.671 100.278 80.789 ;
     RECT  2.304 80.789 5.742 80.825 ;
     RECT  99.036 80.789 99.897 80.825 ;
     RECT  4.788 80.825 5.742 80.897 ;
     RECT  49.032 80.527 49.05 81.059 ;
     RECT  97.236 80.671 98.226 81.095 ;
     RECT  51.015 80.249 51.297 81.211 ;
     RECT  6.804 80.635 6.894 81.307 ;
     RECT  50.4 81.211 51.606 81.329 ;
     RECT  4.824 80.897 5.742 81.341 ;
     RECT  4.824 81.341 5.598 81.365 ;
     RECT  101.016 80.905 101.034 81.445 ;
     RECT  2.304 80.825 3.474 81.473 ;
     RECT  6.804 81.307 6.93 81.481 ;
     RECT  7.815 73.499 8.097 81.481 ;
     RECT  100.62 81.445 101.214 81.599 ;
     RECT  5.364 81.365 5.598 81.635 ;
     RECT  50.508 81.329 51.606 81.635 ;
     RECT  99.288 80.825 99.897 81.715 ;
     RECT  97.236 81.095 97.254 81.739 ;
     RECT  99.216 81.715 99.897 81.751 ;
     RECT  6.66 81.481 8.097 81.869 ;
     RECT  97.092 81.739 97.254 81.869 ;
     RECT  98.136 81.095 98.226 81.869 ;
     RECT  97.092 81.869 97.11 82.021 ;
     RECT  98.172 81.869 98.226 82.021 ;
     RECT  99.108 81.751 100.35 82.021 ;
     RECT  102.564 78.629 102.582 82.027 ;
     RECT  96.912 82.021 97.11 82.049 ;
     RECT  94.215 79.547 94.497 82.075 ;
     RECT  98.172 82.021 100.35 82.139 ;
     RECT  5.58 81.635 5.598 82.175 ;
     RECT  2.415 81.473 3.474 82.291 ;
     RECT  6.66 81.869 6.822 82.319 ;
     RECT  102.528 82.027 102.582 82.459 ;
     RECT  99.615 82.139 100.35 82.525 ;
     RECT  101.16 81.599 101.178 82.525 ;
     RECT  90.648 82.381 90.666 82.553 ;
     RECT  2.415 82.291 3.906 82.561 ;
     RECT  102.024 82.459 102.582 82.589 ;
     RECT  2.415 82.561 4.59 82.679 ;
     RECT  2.415 82.679 4.554 82.699 ;
     RECT  96.912 82.049 96.93 82.715 ;
     RECT  99.615 82.525 101.178 82.751 ;
     RECT  101.016 82.751 101.178 82.831 ;
     RECT  6.66 82.319 6.678 82.859 ;
     RECT  98.172 82.139 98.586 82.939 ;
     RECT  51.015 81.635 51.606 82.949 ;
     RECT  98.064 82.939 98.874 82.985 ;
     RECT  94.215 82.075 94.662 83.093 ;
     RECT  51.015 82.949 51.498 83.191 ;
     RECT  2.304 82.699 4.554 83.219 ;
     RECT  43.884 81.337 43.902 83.219 ;
     RECT  101.016 82.831 101.214 83.219 ;
     RECT  2.304 83.219 3.618 83.255 ;
     RECT  101.016 83.219 101.034 83.255 ;
     RECT  50.436 83.191 51.498 83.399 ;
     RECT  5.364 82.831 5.382 83.461 ;
     RECT  4.428 83.219 4.554 83.641 ;
     RECT  5.364 83.461 5.49 83.641 ;
     RECT  50.436 83.399 51.297 83.641 ;
     RECT  99.615 82.751 99.954 83.641 ;
     RECT  50.184 83.641 51.297 83.731 ;
     RECT  6.624 83.605 6.642 83.744 ;
     RECT  102.564 82.589 102.582 83.755 ;
     RECT  99 83.641 100.674 83.759 ;
     RECT  2.415 83.255 3.51 83.995 ;
     RECT  4.428 83.641 5.49 84.001 ;
     RECT  6.228 83.744 6.642 84.001 ;
     RECT  4.428 84.001 6.642 84.029 ;
     RECT  6.444 84.029 6.642 84.037 ;
     RECT  2.304 83.995 3.51 84.065 ;
     RECT  94.215 83.093 94.497 84.109 ;
     RECT  98.064 82.985 98.226 84.109 ;
     RECT  99 83.759 99.897 84.109 ;
     RECT  4.428 84.029 5.706 84.125 ;
     RECT  2.415 84.065 3.51 84.181 ;
     RECT  97.272 83.755 97.29 84.181 ;
     RECT  6.444 84.037 6.858 84.209 ;
     RECT  4.536 84.125 5.706 84.221 ;
     RECT  96.732 84.181 97.29 84.271 ;
     RECT  98.064 84.109 99.897 84.271 ;
     RECT  48.708 81.841 48.726 84.299 ;
     RECT  96.732 84.271 99.897 84.299 ;
     RECT  94.215 84.109 94.662 84.371 ;
     RECT  4.536 84.221 5.67 84.569 ;
     RECT  102.528 83.755 102.582 84.569 ;
     RECT  101.16 84.181 101.178 84.605 ;
     RECT  54.684 84.541 54.702 84.641 ;
     RECT  2.415 84.181 3.582 84.721 ;
     RECT  49.608 83.731 51.297 84.721 ;
     RECT  97.02 84.299 99.897 84.721 ;
     RECT  6.444 84.209 6.75 84.839 ;
     RECT  2.415 84.721 3.798 84.847 ;
     RECT  2.412 84.847 3.798 84.875 ;
     RECT  49.608 84.721 51.39 84.883 ;
     RECT  6.552 84.839 6.57 84.893 ;
     RECT  4.572 84.569 5.67 84.898 ;
     RECT  100.98 84.811 100.998 84.911 ;
     RECT  4.572 84.898 5.202 85.109 ;
     RECT  4.572 85.109 4.59 85.145 ;
     RECT  97.02 84.721 100.134 85.145 ;
     RECT  99.615 85.145 100.134 85.225 ;
     RECT  2.412 84.875 3.474 85.291 ;
     RECT  97.02 85.145 97.182 85.379 ;
     RECT  7.815 81.869 8.097 85.495 ;
     RECT  49.608 84.883 51.498 85.559 ;
     RECT  2.304 85.291 3.474 85.627 ;
     RECT  7.815 85.495 8.406 85.627 ;
     RECT  7.416 85.627 8.406 85.649 ;
     RECT  49.608 85.559 49.626 85.649 ;
     RECT  52.74 85.495 52.758 85.649 ;
     RECT  95.364 85.531 95.382 85.649 ;
     RECT  94.215 84.371 94.497 85.657 ;
     RECT  7.416 85.649 8.097 85.685 ;
     RECT  94.215 85.657 94.878 85.709 ;
     RECT  97.02 85.379 97.038 85.709 ;
     RECT  2.304 85.627 4.122 85.793 ;
     RECT  98.172 85.145 98.802 85.915 ;
     RECT  7.596 85.685 8.097 85.919 ;
     RECT  90.648 85.729 90.666 85.919 ;
     RECT  95.688 85.801 95.814 85.955 ;
     RECT  5.472 85.801 5.49 86.035 ;
     RECT  99.615 85.225 100.314 86.035 ;
     RECT  2.415 85.793 4.122 86.071 ;
     RECT  99.615 86.035 100.926 86.071 ;
     RECT  2.415 86.071 4.266 86.189 ;
     RECT  2.415 86.189 4.086 86.225 ;
     RECT  99.615 86.071 101.034 86.261 ;
     RECT  50.472 85.559 51.498 86.333 ;
     RECT  100.908 86.261 101.034 86.341 ;
     RECT  102.564 84.569 102.582 86.347 ;
     RECT  52.776 86.341 52.794 86.459 ;
     RECT  100.908 86.341 101.214 86.459 ;
     RECT  102.528 86.347 102.582 86.459 ;
     RECT  100.944 86.459 101.214 86.495 ;
     RECT  5.076 86.035 5.49 86.587 ;
     RECT  98.028 85.915 98.802 86.611 ;
     RECT  99.615 86.261 100.062 86.611 ;
     RECT  98.028 86.611 100.062 86.635 ;
     RECT  97.632 86.635 100.062 86.729 ;
     RECT  51.015 86.333 51.498 86.837 ;
     RECT  5.076 86.587 5.526 86.845 ;
     RECT  4.86 86.845 5.526 86.881 ;
     RECT  100.944 86.495 101.178 86.909 ;
     RECT  2.415 86.225 4.014 87.019 ;
     RECT  2.304 87.019 4.014 87.035 ;
     RECT  98.172 86.729 100.062 87.035 ;
     RECT  4.86 86.881 5.706 87.211 ;
     RECT  95.688 85.955 95.706 87.211 ;
     RECT  4.86 87.211 6.21 87.245 ;
     RECT  5.652 87.245 6.21 87.305 ;
     RECT  95.616 87.211 95.706 87.539 ;
     RECT  95.616 87.539 95.634 87.575 ;
     RECT  4.788 87.421 4.806 87.655 ;
     RECT  97.164 87.421 97.182 87.655 ;
     RECT  101.16 86.909 101.178 87.655 ;
     RECT  51.015 86.837 51.426 87.691 ;
     RECT  97.02 87.655 97.182 87.691 ;
     RECT  98.172 87.035 98.838 87.691 ;
     RECT  99.615 87.035 100.062 87.691 ;
     RECT  99.615 87.691 100.314 87.781 ;
     RECT  101.16 87.655 101.214 87.781 ;
     RECT  99.615 87.781 101.214 87.809 ;
     RECT  4.248 87.655 4.806 87.845 ;
     RECT  2.304 87.035 3.474 87.953 ;
     RECT  98.028 87.691 98.838 87.961 ;
     RECT  99.615 87.809 100.926 87.961 ;
     RECT  52.884 86.611 52.902 87.989 ;
     RECT  98.028 87.961 100.926 88.115 ;
     RECT  96.912 87.691 97.182 88.231 ;
     RECT  96.912 88.231 97.29 88.349 ;
     RECT  98.064 88.115 100.926 88.349 ;
     RECT  102.564 86.459 102.582 88.507 ;
     RECT  52.452 88.501 52.47 88.619 ;
     RECT  102.528 88.507 102.582 88.619 ;
     RECT  96.912 88.349 97.146 88.637 ;
     RECT  96.156 88.603 96.174 88.655 ;
     RECT  98.064 88.349 98.622 88.655 ;
     RECT  5.652 87.305 5.706 88.663 ;
     RECT  5.436 88.663 5.706 88.691 ;
     RECT  50.616 87.691 51.426 88.771 ;
     RECT  99.615 88.349 100.926 88.771 ;
     RECT  96.912 88.637 97.11 88.861 ;
     RECT  49.032 87.241 49.05 88.889 ;
     RECT  98.172 88.655 98.622 88.889 ;
     RECT  102.564 88.619 102.582 88.897 ;
     RECT  96.84 88.861 97.11 88.925 ;
     RECT  2.415 87.953 3.474 88.939 ;
     RECT  5.436 88.691 5.454 88.973 ;
     RECT  102.564 88.897 102.618 88.973 ;
     RECT  99.615 88.771 101.106 89.005 ;
     RECT  94.215 85.709 94.497 89.131 ;
     RECT  99.615 89.005 101.178 89.159 ;
     RECT  2.415 88.939 3.69 89.167 ;
     RECT  2.304 89.167 3.69 89.311 ;
     RECT  4.536 87.845 4.59 89.311 ;
     RECT  96.84 88.925 96.93 89.581 ;
     RECT  99.615 89.159 100.314 89.581 ;
     RECT  98.172 88.889 98.226 89.671 ;
     RECT  2.304 89.311 4.626 89.735 ;
     RECT  98.172 89.671 98.694 89.851 ;
     RECT  99.576 89.581 100.314 89.851 ;
     RECT  50.616 88.771 51.75 89.879 ;
     RECT  98.172 89.851 100.314 89.941 ;
     RECT  2.415 89.735 4.626 89.947 ;
     RECT  96.768 89.581 96.93 89.995 ;
     RECT  2.415 89.947 4.806 90.005 ;
     RECT  98.172 89.941 100.854 90.013 ;
     RECT  96.768 89.995 97.11 90.029 ;
     RECT  98.172 90.013 101.07 90.029 ;
     RECT  0.108 90.013 0.126 90.077 ;
     RECT  6.192 88.939 6.21 90.121 ;
     RECT  5.724 90.121 6.21 90.247 ;
     RECT  4.608 90.005 4.806 90.391 ;
     RECT  5.724 90.247 6.426 90.391 ;
     RECT  97.092 90.029 97.11 90.391 ;
     RECT  50.976 89.879 51.75 90.419 ;
     RECT  99.615 90.029 101.07 90.419 ;
     RECT  2.415 90.005 3.474 90.475 ;
     RECT  4.608 90.391 6.786 90.509 ;
     RECT  97.092 90.391 97.254 90.509 ;
     RECT  99.615 90.419 100.53 90.509 ;
     RECT  2.304 90.475 3.474 90.815 ;
     RECT  2.412 90.815 3.474 90.931 ;
     RECT  93.636 89.131 94.497 91.021 ;
     RECT  98.172 90.029 98.694 91.049 ;
     RECT  98.172 91.049 98.37 91.085 ;
     RECT  102.564 88.973 102.582 91.099 ;
     RECT  93.636 91.021 94.662 91.147 ;
     RECT  4.608 90.509 6.57 91.181 ;
     RECT  93.636 91.147 95.346 91.193 ;
     RECT  2.412 90.931 3.798 91.195 ;
     RECT  4.608 91.181 5.886 91.195 ;
     RECT  99.615 90.509 100.422 91.195 ;
     RECT  50.976 90.419 51.297 91.201 ;
     RECT  96.084 90.751 96.102 91.201 ;
     RECT  2.412 91.195 5.886 91.229 ;
     RECT  99.216 91.195 100.422 91.291 ;
     RECT  50.976 91.201 51.678 91.319 ;
     RECT  50.976 91.319 51.297 91.327 ;
     RECT  96.084 91.201 96.462 91.355 ;
     RECT  99.216 91.291 100.854 91.355 ;
     RECT  102.024 91.099 102.582 91.427 ;
     RECT  99.615 91.355 100.854 91.435 ;
     RECT  5.58 91.229 5.886 91.469 ;
     RECT  2.412 91.229 4.194 91.589 ;
     RECT  50.724 91.327 51.297 91.589 ;
     RECT  99.615 91.435 101.178 91.589 ;
     RECT  2.412 91.589 3.978 91.771 ;
     RECT  99.615 91.589 100.746 91.859 ;
     RECT  6.768 91.327 6.858 91.895 ;
     RECT  5.724 91.469 5.886 92.011 ;
     RECT  52.884 91.741 52.902 92.011 ;
     RECT  98.172 91.085 98.19 92.011 ;
     RECT  94.215 91.193 94.662 92.101 ;
     RECT  6.876 92.011 6.966 92.129 ;
     RECT  50.976 91.589 51.297 92.129 ;
     RECT  52.236 92.011 52.902 92.129 ;
     RECT  2.304 91.771 3.978 92.165 ;
     RECT  5.724 92.011 6.102 92.209 ;
     RECT  94.215 92.101 94.734 92.237 ;
     RECT  96.912 92.011 96.93 92.245 ;
     RECT  98.172 92.011 98.37 92.281 ;
     RECT  99.615 91.859 100.314 92.281 ;
     RECT  5.688 92.209 6.102 92.309 ;
     RECT  54.684 92.101 54.702 92.309 ;
     RECT  56.415 43.277 56.697 92.371 ;
     RECT  96.912 92.245 97.218 92.371 ;
     RECT  56.415 92.371 57.15 92.429 ;
     RECT  96.84 92.371 97.218 92.429 ;
     RECT  55.584 92.395 55.602 92.435 ;
     RECT  98.064 92.281 98.37 92.515 ;
     RECT  99.18 92.281 100.314 92.515 ;
     RECT  50.184 92.395 50.202 92.551 ;
     RECT  50.184 92.551 50.274 92.669 ;
     RECT  96.084 91.355 96.102 92.669 ;
     RECT  98.064 92.515 100.314 92.669 ;
     RECT  2.304 92.165 3.474 92.705 ;
     RECT  5.688 92.309 6.03 92.705 ;
     RECT  98.064 92.669 98.37 92.705 ;
     RECT  50.256 92.669 50.274 92.717 ;
     RECT  10.836 92.713 10.854 92.813 ;
     RECT  102.564 91.427 102.582 92.827 ;
     RECT  95.94 92.785 95.958 92.861 ;
     RECT  6.876 92.129 6.894 92.911 ;
     RECT  51.015 92.129 51.297 92.911 ;
     RECT  98.064 92.705 98.19 92.923 ;
     RECT  102.528 92.827 102.582 92.939 ;
     RECT  97.02 92.429 97.218 92.975 ;
     RECT  4.464 93.019 4.482 93.067 ;
     RECT  2.34 92.705 3.474 93.091 ;
     RECT  4.464 93.067 4.662 93.091 ;
     RECT  2.34 93.091 3.69 93.101 ;
     RECT  94.215 92.237 94.497 93.181 ;
     RECT  52.668 92.129 52.902 93.209 ;
     RECT  97.128 92.975 97.218 93.209 ;
     RECT  2.415 93.101 3.69 93.245 ;
     RECT  4.464 93.091 4.806 93.245 ;
     RECT  94.215 93.181 94.698 93.352 ;
     RECT  51.015 92.911 51.498 93.361 ;
     RECT  52.668 93.209 52.794 93.389 ;
     RECT  4.644 93.245 4.806 93.451 ;
     RECT  97.992 92.923 98.19 93.451 ;
     RECT  99.216 92.669 100.314 93.451 ;
     RECT  46.8 92.947 46.818 93.479 ;
     RECT  97.992 93.451 100.314 93.485 ;
     RECT  5.868 92.705 6.03 93.499 ;
     RECT  6.84 92.911 6.894 93.499 ;
     RECT  98.172 93.485 100.314 93.515 ;
     RECT  5.868 93.499 6.894 93.533 ;
     RECT  101.052 92.821 101.07 93.595 ;
     RECT  99.216 93.515 100.314 93.631 ;
     RECT  101.052 93.595 101.106 93.631 ;
     RECT  51.015 93.361 51.606 93.721 ;
     RECT  4.644 93.451 5.058 93.785 ;
     RECT  99.216 93.631 101.106 93.785 ;
     RECT  99.615 93.785 101.106 93.821 ;
     RECT  6.228 93.533 6.894 93.901 ;
     RECT  7.815 85.919 8.097 93.901 ;
     RECT  51.015 93.721 51.93 93.901 ;
     RECT  52.668 93.389 52.686 93.901 ;
     RECT  99.615 93.821 100.098 93.929 ;
     RECT  2.415 93.245 3.474 93.931 ;
     RECT  94.215 93.352 94.734 93.991 ;
     RECT  6.228 93.901 8.097 94.019 ;
     RECT  51.015 93.901 52.686 94.019 ;
     RECT  99.615 93.929 100.062 94.019 ;
     RECT  4.644 93.785 4.806 94.027 ;
     RECT  6.228 94.019 6.894 94.289 ;
     RECT  96.912 94.171 96.93 94.289 ;
     RECT  100.872 93.821 101.106 94.405 ;
     RECT  98.172 93.515 98.19 94.441 ;
     RECT  96.768 94.441 96.786 94.531 ;
     RECT  97.704 94.441 98.262 94.555 ;
     RECT  4.536 94.027 4.806 94.559 ;
     RECT  94.215 93.991 94.806 94.559 ;
     RECT  96.156 94.531 96.786 94.589 ;
     RECT  94.215 94.559 94.662 94.595 ;
     RECT  97.632 94.555 98.262 94.595 ;
     RECT  100.872 94.405 101.178 94.711 ;
     RECT  2.304 93.931 3.474 94.829 ;
     RECT  49.032 94.297 49.05 94.829 ;
     RECT  96.156 94.589 96.75 94.829 ;
     RECT  96.156 94.829 96.174 94.865 ;
     RECT  99.615 94.019 99.897 94.945 ;
     RECT  100.656 94.711 101.178 94.945 ;
     RECT  7.815 94.019 8.097 94.981 ;
     RECT  51.015 94.019 52.038 94.981 ;
     RECT  97.668 94.595 98.262 94.981 ;
     RECT  102.564 92.939 102.582 94.981 ;
     RECT  102.024 94.981 102.582 95.021 ;
     RECT  6.228 94.289 6.678 95.071 ;
     RECT  5.292 95.071 6.678 95.083 ;
     RECT  97.668 94.981 98.658 95.099 ;
     RECT  99.615 94.945 101.178 95.099 ;
     RECT  50.544 94.981 52.038 95.107 ;
     RECT  5.292 95.083 6.786 95.135 ;
     RECT  7.776 94.981 8.097 95.171 ;
     RECT  99.615 95.099 99.954 95.251 ;
     RECT  0.108 95.143 0.126 95.261 ;
     RECT  50.04 95.107 52.038 95.279 ;
     RECT  5.292 95.135 6.246 95.369 ;
     RECT  4.536 94.559 4.554 95.405 ;
     RECT  5.292 95.369 6.066 95.405 ;
     RECT  101.16 95.099 101.178 95.405 ;
     RECT  94.215 94.595 94.497 95.449 ;
     RECT  97.668 95.099 98.622 95.521 ;
     RECT  2.415 94.829 3.474 95.647 ;
     RECT  5.688 95.405 6.066 95.741 ;
     RECT  52.02 95.279 52.038 95.819 ;
     RECT  99.432 95.251 99.954 95.881 ;
     RECT  5.688 95.741 5.706 95.909 ;
     RECT  4.716 95.719 4.734 95.945 ;
     RECT  99.432 95.881 100.314 95.981 ;
     RECT  97.416 95.521 98.622 96.061 ;
     RECT  2.412 95.647 3.474 96.091 ;
     RECT  97.416 96.061 98.694 96.125 ;
     RECT  94.215 95.449 94.662 96.139 ;
     RECT  2.304 96.091 3.474 96.151 ;
     RECT  92.016 94.027 92.034 96.179 ;
     RECT  94.215 96.139 95.202 96.215 ;
     RECT  97.884 96.125 98.694 96.331 ;
     RECT  99.432 95.981 100.062 96.331 ;
     RECT  2.304 96.151 3.726 96.427 ;
     RECT  90.648 96.331 90.666 96.449 ;
     RECT  95.688 96.331 95.706 96.449 ;
     RECT  97.884 96.331 100.062 96.485 ;
     RECT  2.304 96.427 4.302 96.593 ;
     RECT  46.764 96.421 46.782 96.719 ;
     RECT  2.415 96.593 4.302 96.791 ;
     RECT  50.04 95.279 51.297 96.871 ;
     RECT  98.064 96.485 100.062 96.871 ;
     RECT  98.064 96.871 100.386 96.893 ;
     RECT  99.072 96.893 100.386 97.025 ;
     RECT  102.564 95.021 102.582 97.147 ;
     RECT  5.076 96.427 5.382 97.195 ;
     RECT  4.752 97.195 5.382 97.259 ;
     RECT  50.04 96.871 51.39 97.259 ;
     RECT  98.064 96.893 98.226 97.259 ;
     RECT  96.336 97.231 96.354 97.277 ;
     RECT  4.896 97.259 5.382 97.411 ;
     RECT  98.064 97.259 98.19 97.411 ;
     RECT  94.215 96.215 94.497 97.501 ;
     RECT  97.488 97.411 98.19 97.565 ;
     RECT  102.528 97.147 102.582 97.579 ;
     RECT  101.988 97.579 102.582 97.637 ;
     RECT  7.815 95.171 8.097 97.645 ;
     RECT  4.896 97.411 5.67 97.681 ;
     RECT  100.62 97.141 100.926 97.799 ;
     RECT  4.896 97.681 5.886 97.835 ;
     RECT  99.072 97.025 99.897 97.835 ;
     RECT  2.415 96.791 3.978 97.951 ;
     RECT  100.764 97.799 100.926 97.951 ;
     RECT  2.415 97.951 4.05 98.059 ;
     RECT  4.896 97.835 5.67 98.059 ;
     RECT  100.764 97.951 101.142 98.069 ;
     RECT  2.415 98.059 5.67 98.105 ;
     RECT  50.616 97.259 51.39 98.105 ;
     RECT  95.544 98.059 95.562 98.105 ;
     RECT  101.124 98.069 101.142 98.105 ;
     RECT  6.84 98.041 6.858 98.141 ;
     RECT  90.648 98.077 90.666 98.177 ;
     RECT  93.492 97.501 94.497 98.221 ;
     RECT  4.284 98.105 5.67 98.249 ;
     RECT  2.415 98.105 3.474 98.251 ;
     RECT  52.416 98.221 52.506 98.339 ;
     RECT  96.516 98.221 96.534 98.375 ;
     RECT  99.432 97.835 99.897 98.581 ;
     RECT  50.724 98.105 51.39 98.609 ;
     RECT  93.492 98.221 94.662 98.609 ;
     RECT  98.064 97.565 98.19 98.725 ;
     RECT  98.064 98.725 98.226 98.753 ;
     RECT  99.396 98.581 99.897 98.761 ;
     RECT  99.216 98.761 99.897 98.851 ;
     RECT  101.16 98.725 101.178 98.851 ;
     RECT  51.015 98.609 51.39 98.879 ;
     RECT  2.304 98.251 3.474 99.031 ;
     RECT  4.284 98.249 4.914 99.031 ;
     RECT  5.652 98.249 5.67 99.031 ;
     RECT  99.216 98.851 101.178 99.031 ;
     RECT  98.172 98.753 98.226 99.053 ;
     RECT  2.304 99.031 6.246 99.149 ;
     RECT  7.704 97.645 8.097 99.149 ;
     RECT  99.144 99.031 101.178 99.185 ;
     RECT  5.544 99.149 6.246 99.197 ;
     RECT  102.564 97.637 102.582 99.307 ;
     RECT  90.648 99.301 90.666 99.455 ;
     RECT  99.324 99.185 101.178 99.455 ;
     RECT  102.024 99.307 102.582 99.527 ;
     RECT  96.912 99.301 96.93 99.571 ;
     RECT  98.172 99.053 98.19 99.571 ;
     RECT  5.616 99.197 6.246 99.599 ;
     RECT  93.492 98.609 94.626 99.599 ;
     RECT  96.768 99.571 96.93 99.629 ;
     RECT  102.564 99.527 102.582 99.661 ;
     RECT  95.544 99.571 95.562 99.725 ;
     RECT  102.564 99.661 102.618 99.773 ;
     RECT  94.215 99.599 94.626 100.039 ;
     RECT  99.324 99.455 100.926 100.039 ;
     RECT  2.304 99.149 4.77 100.111 ;
     RECT  5.616 99.599 5.778 100.111 ;
     RECT  97.704 99.571 98.19 100.111 ;
     RECT  53.892 98.041 53.91 100.139 ;
     RECT  94.215 100.039 94.662 100.139 ;
     RECT  99.216 100.039 100.926 100.237 ;
     RECT  2.304 100.111 5.778 100.265 ;
     RECT  97.38 100.111 98.19 100.307 ;
     RECT  99.072 100.237 100.926 100.345 ;
     RECT  4.752 100.265 5.778 100.349 ;
     RECT  99.072 100.345 101.214 100.499 ;
     RECT  2.304 100.265 3.474 100.535 ;
     RECT  51.015 98.879 51.297 100.651 ;
     RECT  98.064 100.307 98.19 100.651 ;
     RECT  52.668 98.581 52.686 100.679 ;
     RECT  54.684 100.615 54.702 100.769 ;
     RECT  96.048 100.615 96.066 100.769 ;
     RECT  99.072 100.499 101.178 100.841 ;
     RECT  99.072 100.841 101.142 100.891 ;
     RECT  98.064 100.651 98.226 100.925 ;
     RECT  48.456 99.121 48.474 101.039 ;
     RECT  96.336 100.849 96.93 101.075 ;
     RECT  50.22 99.661 50.238 101.119 ;
     RECT  46.764 101.047 46.782 101.147 ;
     RECT  4.788 100.349 5.778 101.191 ;
     RECT  50.184 101.119 50.238 101.219 ;
     RECT  2.415 100.535 3.474 101.275 ;
     RECT  102.564 99.773 102.582 101.281 ;
     RECT  4.788 101.191 6.354 101.309 ;
     RECT  96.336 101.075 96.822 101.309 ;
     RECT  4.788 101.309 5.778 101.345 ;
     RECT  98.964 100.891 101.142 101.345 ;
     RECT  98.172 100.925 98.226 101.425 ;
     RECT  96.336 101.309 96.642 101.453 ;
     RECT  96.624 101.453 96.642 101.459 ;
     RECT  102.564 101.281 102.618 101.501 ;
     RECT  99.615 101.345 101.142 101.579 ;
     RECT  98.172 101.425 98.586 101.615 ;
     RECT  2.304 101.275 3.474 101.731 ;
     RECT  2.304 101.731 3.582 101.741 ;
     RECT  5.688 101.345 5.778 101.759 ;
     RECT  94.215 100.139 94.497 101.821 ;
     RECT  4.464 101.467 4.698 101.849 ;
     RECT  101.16 101.731 101.178 101.885 ;
     RECT  4.608 101.849 4.698 101.993 ;
     RECT  2.34 101.741 3.582 102.001 ;
     RECT  52.344 101.731 52.47 102.001 ;
     RECT  4.68 101.993 4.698 102.119 ;
     RECT  94.215 101.821 94.662 102.119 ;
     RECT  2.34 102.001 3.87 102.155 ;
     RECT  97.128 102.229 97.146 102.269 ;
     RECT  98.172 101.615 98.19 102.271 ;
     RECT  5.76 101.759 5.778 102.361 ;
     RECT  50.184 101.219 50.202 102.361 ;
     RECT  51.015 100.651 51.39 102.361 ;
     RECT  5.76 102.361 6.066 102.389 ;
     RECT  4.932 102.271 4.95 102.425 ;
     RECT  98.064 102.271 98.19 102.425 ;
     RECT  6.048 102.389 6.066 102.541 ;
     RECT  6.048 102.541 6.282 102.569 ;
     RECT  2.34 102.155 3.474 102.571 ;
     RECT  95.724 102.619 95.742 102.631 ;
     RECT  50.184 102.361 51.39 102.659 ;
     RECT  2.304 102.571 3.474 102.695 ;
     RECT  50.472 102.659 51.39 102.731 ;
     RECT  95.724 102.631 96.102 102.929 ;
     RECT  97.344 102.811 97.362 102.965 ;
     RECT  101.16 102.901 101.178 103.001 ;
     RECT  6.228 102.569 6.282 103.045 ;
     RECT  95.724 102.929 95.922 103.073 ;
     RECT  97.272 103.081 97.29 103.171 ;
     RECT  6.228 103.045 6.426 103.199 ;
     RECT  47.304 102.901 47.322 103.199 ;
     RECT  96.84 103.171 97.29 103.235 ;
     RECT  99.615 101.579 99.897 103.315 ;
     RECT  2.415 102.695 3.474 103.351 ;
     RECT  99.615 103.315 100.098 103.351 ;
     RECT  2.415 103.351 3.798 103.435 ;
     RECT  52.272 102.001 52.47 103.469 ;
     RECT  2.304 103.435 3.798 103.505 ;
     RECT  2.412 103.505 3.798 103.585 ;
     RECT  4.536 103.081 4.554 103.585 ;
     RECT  98.172 102.425 98.19 103.585 ;
     RECT  99.615 103.351 101.142 103.621 ;
     RECT  102.564 101.501 102.582 103.621 ;
     RECT  102.024 103.621 102.582 103.661 ;
     RECT  50.472 102.731 51.297 103.711 ;
     RECT  2.412 103.585 4.554 103.723 ;
     RECT  99.576 103.621 101.142 103.739 ;
     RECT  2.412 103.723 4.806 103.891 ;
     RECT  98.172 103.585 98.766 103.891 ;
     RECT  2.412 103.891 4.95 103.901 ;
     RECT  52.272 103.469 52.29 103.919 ;
     RECT  50.076 103.711 51.297 104.009 ;
     RECT  99.576 103.739 100.602 104.009 ;
     RECT  95.904 103.073 95.922 104.017 ;
     RECT  2.415 103.901 4.95 104.045 ;
     RECT  98.1 103.891 98.766 104.161 ;
     RECT  99.576 104.009 100.53 104.161 ;
     RECT  97.956 104.161 100.53 104.237 ;
     RECT  4.536 104.045 4.95 104.251 ;
     RECT  95.904 104.017 96.066 104.279 ;
     RECT  98.172 104.237 100.53 104.279 ;
     RECT  95.904 104.279 95.922 104.285 ;
     RECT  96.84 103.235 96.858 104.287 ;
     RECT  4.536 104.251 5.13 104.315 ;
     RECT  6.408 103.199 6.426 104.315 ;
     RECT  98.172 104.279 100.314 104.315 ;
     RECT  0.108 104.287 0.126 104.333 ;
     RECT  47.88 103.441 47.898 104.521 ;
     RECT  5.112 104.315 5.13 104.585 ;
     RECT  96.84 104.287 96.93 104.585 ;
     RECT  7.815 99.149 8.097 104.665 ;
     RECT  2.415 104.045 3.474 104.731 ;
     RECT  2.304 104.731 3.474 104.791 ;
     RECT  2.304 104.791 3.834 104.855 ;
     RECT  7.38 104.665 8.097 104.861 ;
     RECT  96.84 104.585 96.858 104.875 ;
     RECT  50.076 104.009 50.13 104.971 ;
     RECT  51.015 104.009 51.297 104.971 ;
     RECT  99.072 104.315 100.314 105.061 ;
     RECT  47.304 104.521 47.898 105.089 ;
     RECT  50.076 104.971 51.297 105.089 ;
     RECT  96.696 104.875 96.858 105.089 ;
     RECT  96.696 105.089 96.714 105.125 ;
     RECT  98.172 104.315 98.19 105.205 ;
     RECT  99.072 105.061 100.746 105.205 ;
     RECT  2.415 104.855 3.834 105.241 ;
     RECT  98.172 105.205 100.746 105.241 ;
     RECT  2.415 105.241 4.482 105.331 ;
     RECT  5.328 104.827 5.634 105.331 ;
     RECT  102.564 103.661 102.582 105.355 ;
     RECT  102.528 105.355 102.582 105.359 ;
     RECT  97.632 105.241 101.214 105.395 ;
     RECT  2.415 105.331 5.634 105.403 ;
     RECT  98.064 105.395 100.926 105.431 ;
     RECT  2.415 105.403 5.706 105.595 ;
     RECT  51.015 105.089 51.297 105.601 ;
     RECT  50.076 105.089 50.13 105.773 ;
     RECT  102.528 105.359 102.546 105.781 ;
     RECT  50.112 105.773 50.13 105.809 ;
     RECT  99 105.431 100.926 105.899 ;
     RECT  2.34 105.595 5.706 105.935 ;
     RECT  96.048 105.781 96.066 105.943 ;
     RECT  94.215 102.119 94.497 105.979 ;
     RECT  95.868 105.943 96.066 106.013 ;
     RECT  98.064 105.431 98.226 106.013 ;
     RECT  5.328 105.935 5.706 106.015 ;
     RECT  2.34 105.935 3.474 106.027 ;
     RECT  5.328 106.015 6.318 106.043 ;
     RECT  51.015 105.601 51.354 106.051 ;
     RECT  97.164 105.943 97.182 106.205 ;
     RECT  99 105.899 99.897 106.205 ;
     RECT  100.908 105.899 100.926 106.241 ;
     RECT  98.172 106.013 98.226 106.411 ;
     RECT  47.304 105.089 47.322 106.439 ;
     RECT  102.024 105.781 102.546 106.439 ;
     RECT  94.215 105.979 94.662 106.447 ;
     RECT  94.212 106.447 94.662 106.493 ;
     RECT  50.184 106.447 50.202 106.519 ;
     RECT  51.015 106.051 51.426 106.519 ;
     RECT  50.184 106.519 51.426 106.547 ;
     RECT  6.3 106.043 6.318 106.589 ;
     RECT  50.436 106.547 51.426 106.591 ;
     RECT  52.164 105.511 52.182 106.591 ;
     RECT  94.215 106.493 94.662 106.591 ;
     RECT  5.328 106.043 5.346 106.709 ;
     RECT  6.444 106.591 6.822 106.709 ;
     RECT  96.336 106.411 96.354 106.709 ;
     RECT  98.172 106.411 98.622 106.709 ;
     RECT  94.215 106.591 95.202 106.745 ;
     RECT  46.764 106.717 46.782 106.817 ;
     RECT  4.248 105.935 4.482 106.852 ;
     RECT  2.304 106.027 3.474 106.861 ;
     RECT  4.248 106.852 4.518 106.861 ;
     RECT  6.444 106.709 6.462 106.979 ;
     RECT  2.304 106.861 4.518 107.015 ;
     RECT  2.415 107.015 4.518 107.131 ;
     RECT  50.436 106.591 52.182 107.249 ;
     RECT  2.415 107.131 4.59 107.365 ;
     RECT  99.615 106.205 99.897 107.365 ;
     RECT  99.288 107.365 99.897 107.401 ;
     RECT  101.16 107.095 101.178 107.401 ;
     RECT  98.172 106.709 98.19 107.515 ;
     RECT  52.164 107.249 52.182 107.519 ;
     RECT  99.288 107.401 101.178 107.519 ;
     RECT  99.288 107.519 101.142 107.549 ;
     RECT  2.415 107.365 5.13 107.755 ;
     RECT  2.304 107.755 5.13 107.825 ;
     RECT  102.564 106.651 102.582 107.947 ;
     RECT  50.436 107.249 51.426 107.969 ;
     RECT  6.876 107.755 6.894 108.031 ;
     RECT  98.172 107.515 98.406 108.031 ;
     RECT  47.376 107.761 47.394 108.059 ;
     RECT  102.528 107.947 102.582 108.059 ;
     RECT  2.34 107.825 5.13 108.067 ;
     RECT  6.048 107.401 6.066 108.067 ;
     RECT  96.912 107.941 96.93 108.067 ;
     RECT  99.504 107.549 101.142 108.095 ;
     RECT  94.215 106.745 94.497 108.103 ;
     RECT  50.436 107.969 51.297 108.131 ;
     RECT  6.804 108.031 6.894 108.175 ;
     RECT  7.815 104.861 8.097 108.175 ;
     RECT  96.84 108.067 96.93 108.211 ;
     RECT  98.172 108.031 98.622 108.211 ;
     RECT  2.34 108.067 6.066 108.221 ;
     RECT  54.684 108.103 54.702 108.239 ;
     RECT  6.804 108.175 8.097 108.329 ;
     RECT  97.812 108.211 98.622 108.365 ;
     RECT  94.068 108.103 94.497 108.409 ;
     RECT  98.172 108.365 98.622 108.409 ;
     RECT  99.504 108.095 101.034 108.409 ;
     RECT  96.696 108.211 96.93 108.481 ;
     RECT  52.92 106.861 52.938 108.509 ;
     RECT  6.804 108.329 6.822 108.599 ;
     RECT  98.172 108.409 101.034 108.599 ;
     RECT  2.415 108.221 6.066 108.635 ;
     RECT  96.696 108.481 97.074 108.643 ;
     RECT  94.068 108.409 94.662 108.751 ;
     RECT  6.048 108.635 6.066 108.779 ;
     RECT  50.94 108.131 51.297 108.869 ;
     RECT  52.992 108.751 53.118 108.869 ;
     RECT  96.696 108.643 97.362 108.869 ;
     RECT  98.964 108.599 101.034 108.869 ;
     RECT  99.18 108.869 101.034 108.985 ;
     RECT  2.415 108.635 5.31 109.051 ;
     RECT  94.068 108.751 95.202 109.139 ;
     RECT  2.304 109.051 5.31 109.175 ;
     RECT  98.172 108.599 98.19 109.291 ;
     RECT  2.415 109.175 5.31 109.409 ;
     RECT  99.18 108.985 101.178 109.409 ;
     RECT  4.392 109.409 5.31 109.445 ;
     RECT  97.056 108.869 97.074 109.469 ;
     RECT  0.108 109.417 0.126 109.517 ;
     RECT  7.815 108.329 8.097 109.525 ;
     RECT  100.944 109.409 101.178 109.525 ;
     RECT  98.028 109.291 98.19 109.651 ;
     RECT  7.308 109.525 8.097 109.679 ;
     RECT  47.304 108.067 47.322 109.679 ;
     RECT  52.668 109.525 52.686 109.679 ;
     RECT  54.612 109.651 54.63 109.723 ;
     RECT  92.592 109.723 92.61 109.759 ;
     RECT  96.156 109.435 96.174 109.759 ;
     RECT  52.776 109.687 52.866 109.787 ;
     RECT  54.612 109.723 54.738 109.831 ;
     RECT  49.032 108.103 49.05 109.859 ;
     RECT  54.612 109.831 54.81 109.859 ;
     RECT  92.592 109.759 92.682 109.859 ;
     RECT  94.068 109.139 94.914 109.859 ;
     RECT  96.156 109.759 96.39 109.859 ;
     RECT  6.372 109.831 6.39 109.901 ;
     RECT  2.415 109.409 3.582 109.915 ;
     RECT  96.156 109.859 96.318 109.921 ;
     RECT  54.684 109.859 54.81 109.949 ;
     RECT  94.215 109.859 94.914 109.949 ;
     RECT  95.76 109.921 96.318 109.949 ;
     RECT  2.304 109.915 3.582 109.985 ;
     RECT  52.776 109.787 52.794 109.985 ;
     RECT  54.684 109.949 54.702 109.985 ;
     RECT  102.564 108.059 102.582 109.993 ;
     RECT  94.215 109.949 94.77 109.997 ;
     RECT  95.76 109.949 96.174 109.997 ;
     RECT  102.564 109.993 102.618 110.141 ;
     RECT  4.644 109.445 5.31 110.219 ;
     RECT  97.272 109.651 98.19 110.219 ;
     RECT  100.944 109.525 101.214 110.219 ;
     RECT  97.272 110.219 97.398 110.255 ;
     RECT  99.18 109.409 99.897 110.489 ;
     RECT  95.76 109.997 95.85 110.561 ;
     RECT  2.415 109.985 3.582 110.587 ;
     RECT  99.216 110.489 99.897 110.641 ;
     RECT  100.944 110.219 101.034 110.641 ;
     RECT  51.015 108.869 51.297 110.731 ;
     RECT  2.415 110.587 4.23 110.759 ;
     RECT  2.415 110.759 3.582 110.779 ;
     RECT  2.304 110.779 3.582 110.795 ;
     RECT  50.976 110.731 51.297 110.911 ;
     RECT  5.292 110.219 5.31 110.939 ;
     RECT  98.172 110.219 98.19 111.001 ;
     RECT  50.364 110.911 51.297 111.029 ;
     RECT  102.564 110.141 102.582 111.029 ;
     RECT  98.136 111.001 98.19 111.037 ;
     RECT  4.464 111.001 4.482 111.109 ;
     RECT  99.216 110.641 101.034 111.109 ;
     RECT  98.136 111.037 98.226 111.173 ;
     RECT  95.76 110.561 95.778 111.197 ;
     RECT  4.464 111.109 5.238 111.299 ;
     RECT  4.464 111.299 4.482 111.335 ;
     RECT  45.615 78.539 45.897 111.541 ;
     RECT  97.38 110.255 97.398 111.569 ;
     RECT  101.988 111.403 102.006 111.569 ;
     RECT  5.22 111.299 5.238 111.605 ;
     RECT  6.192 111.109 6.21 111.685 ;
     RECT  98.172 111.173 98.226 111.721 ;
     RECT  6.192 111.685 6.426 111.725 ;
     RECT  97.236 111.685 97.254 111.725 ;
     RECT  92.592 109.859 92.61 111.839 ;
     RECT  98.172 111.721 98.442 111.875 ;
     RECT  102.024 111.835 102.582 111.875 ;
     RECT  2.304 110.795 3.474 111.991 ;
     RECT  95.616 111.955 95.634 112.013 ;
     RECT  2.304 111.991 4.05 112.075 ;
     RECT  96.552 111.991 96.57 112.117 ;
     RECT  2.304 112.075 4.554 112.145 ;
     RECT  96.336 112.117 96.57 112.145 ;
     RECT  94.215 109.997 94.497 112.153 ;
     RECT  50.976 111.029 51.297 112.181 ;
     RECT  99.216 111.109 101.178 112.225 ;
     RECT  94.215 112.153 94.662 112.253 ;
     RECT  54.684 112.153 54.702 112.289 ;
     RECT  102.024 111.875 102.042 112.301 ;
     RECT  2.415 112.145 3.654 112.649 ;
     RECT  2.415 112.649 3.546 112.685 ;
     RECT  98.964 112.225 101.178 112.699 ;
     RECT  98.172 111.875 98.19 112.801 ;
     RECT  98.964 112.699 101.61 112.801 ;
     RECT  97.2 112.801 97.218 112.877 ;
     RECT  96.336 112.145 96.354 112.891 ;
     RECT  2.415 112.685 3.51 112.927 ;
     RECT  51.015 112.181 51.297 112.927 ;
     RECT  6.192 111.725 6.21 112.963 ;
     RECT  6.984 112.843 7.002 112.963 ;
     RECT  6.192 112.963 7.002 113.071 ;
     RECT  98.172 112.801 101.61 113.099 ;
     RECT  51.015 112.927 51.714 113.161 ;
     RECT  96.336 112.891 96.498 113.189 ;
     RECT  5.724 113.071 7.002 113.225 ;
     RECT  5.724 113.225 6.822 113.341 ;
     RECT  50.724 113.161 51.714 113.341 ;
     RECT  98.172 113.099 101.178 113.341 ;
     RECT  96.336 113.189 96.426 113.369 ;
     RECT  2.412 112.927 3.51 113.371 ;
     RECT  5.472 113.341 6.822 113.459 ;
     RECT  45.036 111.541 45.897 113.459 ;
     RECT  95.472 113.419 95.49 113.459 ;
     RECT  2.304 113.371 3.51 113.495 ;
     RECT  5.472 113.459 5.742 113.495 ;
     RECT  98.028 113.341 101.178 113.495 ;
     RECT  96.408 113.369 96.426 113.765 ;
     RECT  2.415 113.495 3.51 113.881 ;
     RECT  4.536 112.145 4.554 113.881 ;
     RECT  6.768 113.459 6.822 113.882 ;
     RECT  2.415 113.881 3.726 113.971 ;
     RECT  4.5 113.881 4.554 113.971 ;
     RECT  102.564 113.131 102.582 113.971 ;
     RECT  6.768 113.882 6.786 113.999 ;
     RECT  102.564 113.971 102.618 114.029 ;
     RECT  98.064 113.495 101.178 114.077 ;
     RECT  5.652 113.495 5.742 114.179 ;
     RECT  2.415 113.971 4.554 114.235 ;
     RECT  50.724 113.341 51.822 114.241 ;
     RECT  99.072 114.077 101.178 114.269 ;
     RECT  2.304 114.235 4.554 114.305 ;
     RECT  2.415 114.305 4.554 114.511 ;
     RECT  97.128 113.971 97.146 114.511 ;
     RECT  98.064 114.077 98.226 114.539 ;
     RECT  102.024 114.427 102.042 114.539 ;
     RECT  96.984 114.511 97.146 114.557 ;
     RECT  2.415 114.511 4.77 114.571 ;
     RECT  5.652 114.179 5.706 114.571 ;
     RECT  0.108 114.547 0.126 114.701 ;
     RECT  49.032 114.511 49.05 114.809 ;
     RECT  99.072 114.269 100.314 114.845 ;
     RECT  50.724 114.241 51.966 114.961 ;
     RECT  99.18 114.845 100.314 115.051 ;
     RECT  95.796 115.045 95.814 115.085 ;
     RECT  2.415 114.571 5.706 115.087 ;
     RECT  98.064 114.539 98.19 115.123 ;
     RECT  99.18 115.051 100.422 115.151 ;
     RECT  2.304 115.087 5.706 115.259 ;
     RECT  97.164 115.123 98.19 115.349 ;
     RECT  99.18 115.151 99.897 115.349 ;
     RECT  2.304 115.259 5.67 115.385 ;
     RECT  97.164 115.349 97.182 115.385 ;
     RECT  2.304 115.385 4.77 115.619 ;
     RECT  94.215 112.253 94.497 115.699 ;
     RECT  98.064 115.349 98.19 115.699 ;
     RECT  50.544 114.961 51.966 115.771 ;
     RECT  94.215 115.699 94.662 115.771 ;
     RECT  50.22 115.771 51.966 115.799 ;
     RECT  50.22 115.799 51.297 115.889 ;
     RECT  94.215 115.771 94.734 115.889 ;
     RECT  98.064 115.699 98.478 115.889 ;
     RECT  98.064 115.889 98.334 116.033 ;
     RECT  5.652 115.385 5.67 116.041 ;
     RECT  99.252 115.349 99.897 116.041 ;
     RECT  101.16 115.321 101.178 116.041 ;
     RECT  5.652 116.041 5.814 116.159 ;
     RECT  2.304 115.619 3.978 116.195 ;
     RECT  4.752 115.619 4.77 116.239 ;
     RECT  98.064 116.033 98.226 116.239 ;
     RECT  97.488 116.239 98.226 116.285 ;
     RECT  99.252 116.041 101.178 116.429 ;
     RECT  6.804 114.889 6.822 116.443 ;
     RECT  4.752 116.239 5.166 116.465 ;
     RECT  102.564 114.859 102.582 116.581 ;
     RECT  47.304 114.781 47.322 116.609 ;
     RECT  100.656 116.429 101.178 116.609 ;
     RECT  102.024 116.581 102.582 116.621 ;
     RECT  94.215 115.889 94.497 116.671 ;
     RECT  97.596 116.285 98.226 116.699 ;
     RECT  100.728 116.609 101.178 116.699 ;
     RECT  102.564 116.621 102.582 116.699 ;
     RECT  94.215 116.671 95.058 116.717 ;
     RECT  5.976 116.443 6.822 116.735 ;
     RECT  50.472 115.889 51.297 116.815 ;
     RECT  99.252 116.429 99.897 116.851 ;
     RECT  2.304 116.195 3.474 116.861 ;
     RECT  6.156 116.735 6.822 116.879 ;
     RECT  97.596 116.699 98.19 116.969 ;
     RECT  96.804 116.815 96.822 117.005 ;
     RECT  99 116.851 99.897 117.005 ;
     RECT  100.8 116.699 101.178 117.019 ;
     RECT  2.415 116.861 3.474 117.121 ;
     RECT  52.092 116.401 52.11 117.211 ;
     RECT  2.415 117.121 3.978 117.275 ;
     RECT  4.752 116.465 4.77 117.355 ;
     RECT  100.8 117.019 101.538 117.419 ;
     RECT  4.356 117.355 4.77 117.437 ;
     RECT  94.215 116.717 94.497 117.481 ;
     RECT  100.8 117.419 101.214 117.481 ;
     RECT  102.6 117.319 102.618 117.485 ;
     RECT  100.728 117.481 101.214 117.509 ;
     RECT  5.688 117.481 5.706 117.625 ;
     RECT  98.172 116.969 98.19 117.625 ;
     RECT  52.092 117.211 52.686 117.661 ;
     RECT  99.216 117.005 99.897 117.661 ;
     RECT  5.688 117.625 5.814 117.677 ;
     RECT  6.624 116.879 6.822 117.689 ;
     RECT  2.415 117.275 3.474 117.691 ;
     RECT  52.092 117.661 52.794 117.779 ;
     RECT  2.304 117.691 3.474 117.815 ;
     RECT  94.215 117.481 94.662 117.823 ;
     RECT  4.536 117.437 4.77 117.931 ;
     RECT  5.688 117.677 5.706 118.049 ;
     RECT  4.536 117.931 4.842 118.085 ;
     RECT  6.768 117.689 6.822 118.085 ;
     RECT  4.824 118.085 4.842 118.157 ;
     RECT  94.068 117.823 94.662 118.165 ;
     RECT  98.172 117.625 98.262 118.165 ;
     RECT  97.344 118.165 98.262 118.201 ;
     RECT  96.192 118.165 96.21 118.205 ;
     RECT  94.068 118.165 94.698 118.229 ;
     RECT  99.216 117.661 99.99 118.291 ;
     RECT  100.728 117.509 101.178 118.291 ;
     RECT  94.215 118.229 94.698 118.319 ;
     RECT  97.164 118.201 98.298 118.319 ;
     RECT  99.216 118.291 101.178 118.319 ;
     RECT  97.164 118.319 97.182 118.355 ;
     RECT  98.172 118.319 98.298 118.355 ;
     RECT  99.216 118.319 101.142 118.471 ;
     RECT  2.415 117.815 3.474 118.555 ;
     RECT  50.4 116.815 51.297 118.561 ;
     RECT  98.964 118.471 101.142 118.589 ;
     RECT  95.688 118.555 95.706 118.595 ;
     RECT  6.3 118.555 6.462 118.625 ;
     RECT  50.184 118.561 51.297 118.697 ;
     RECT  102.564 117.883 102.582 118.747 ;
     RECT  94.215 118.319 94.662 118.769 ;
     RECT  6.444 118.625 6.462 118.859 ;
     RECT  99.324 118.589 101.142 118.859 ;
     RECT  102.528 118.747 102.582 118.859 ;
     RECT  5.004 118.741 5.022 118.895 ;
     RECT  96.624 118.363 96.93 118.895 ;
     RECT  100.656 118.859 101.142 118.895 ;
     RECT  2.304 118.555 3.474 119.021 ;
     RECT  52.452 117.779 52.794 119.129 ;
     RECT  98.172 118.355 98.19 119.131 ;
     RECT  100.656 118.895 100.926 119.165 ;
     RECT  98.064 119.131 98.19 119.245 ;
     RECT  2.415 119.021 3.474 119.399 ;
     RECT  100.656 119.165 100.674 119.435 ;
     RECT  96.912 118.895 96.93 119.579 ;
     RECT  99.324 118.859 99.897 119.677 ;
     RECT  97.668 119.245 98.19 119.705 ;
     RECT  98.172 119.705 98.19 119.785 ;
     RECT  99.18 119.677 99.897 119.785 ;
     RECT  98.172 119.785 98.442 119.813 ;
     RECT  98.316 119.813 98.442 119.821 ;
     RECT  99.18 119.785 100.314 119.821 ;
     RECT  56.415 92.429 56.697 120.181 ;
     RECT  2.415 119.399 3.438 120.245 ;
     RECT  52.452 119.129 52.47 120.389 ;
     RECT  102.564 118.859 102.582 120.475 ;
     RECT  50.184 118.697 50.202 120.479 ;
     RECT  96.732 120.361 96.75 120.479 ;
     RECT  98.316 119.821 100.314 120.551 ;
     RECT  2.415 120.245 3.366 120.595 ;
     RECT  96.588 120.595 96.606 120.631 ;
     RECT  101.052 120.253 101.07 120.631 ;
     RECT  2.34 120.595 3.366 120.749 ;
     RECT  97.524 120.631 97.542 120.785 ;
     RECT  96.444 120.631 96.606 120.821 ;
     RECT  95.508 120.595 95.526 120.893 ;
     RECT  96.588 120.821 96.606 120.893 ;
     RECT  58.68 120.829 58.698 120.901 ;
     RECT  100.692 120.631 101.07 120.901 ;
     RECT  98.316 120.551 99.897 121.019 ;
     RECT  98.316 121.019 98.55 121.091 ;
     RECT  56.415 120.181 56.862 121.099 ;
     RECT  57.96 120.901 58.698 121.099 ;
     RECT  78.015 43.277 78.297 121.099 ;
     RECT  56.415 121.099 58.698 121.171 ;
     RECT  76.356 121.099 76.374 121.288 ;
     RECT  2.415 120.749 3.366 121.289 ;
     RECT  55.656 121.171 58.698 121.289 ;
     RECT  77.328 121.099 78.297 121.289 ;
     RECT  98.316 121.091 98.406 121.289 ;
     RECT  99.288 121.019 99.897 121.289 ;
     RECT  102.528 120.475 102.582 121.289 ;
     RECT  75.78 121.288 76.374 121.325 ;
     RECT  98.316 121.289 98.334 121.325 ;
     RECT  100.692 120.901 101.214 121.325 ;
     RECT  55.656 121.289 57.258 121.361 ;
     RECT  58.68 121.289 58.698 121.361 ;
     RECT  55.656 121.361 56.862 121.397 ;
     RECT  74.664 121.297 74.682 121.397 ;
     RECT  77.4 121.289 78.297 121.397 ;
     RECT  100.692 121.325 101.178 121.559 ;
     RECT  102.564 121.289 102.582 121.559 ;
     RECT  101.16 121.559 101.178 121.595 ;
     RECT  0.108 119.515 0.126 121.613 ;
     RECT  76.356 121.325 76.374 122.009 ;
     RECT  55.656 121.397 55.674 122.099 ;
     RECT  55.62 122.215 55.638 122.909 ;
     RECT  54.36 122.539 54.378 122.953 ;
     RECT  55.152 122.917 55.17 122.953 ;
     RECT  54.36 122.953 55.17 123.215 ;
     RECT  53.028 123.115 53.046 123.331 ;
     RECT  54.36 123.215 54.666 123.331 ;
     RECT  53.028 123.331 54.666 123.359 ;
     RECT  53.028 123.359 54.486 123.449 ;
     RECT  53.028 123.449 54.414 123.521 ;
     RECT  53.028 123.521 53.334 123.835 ;
     RECT  54.324 123.521 54.414 123.899 ;
     RECT  52.38 123.835 53.334 123.989 ;
     RECT  54.324 123.899 54.342 123.989 ;
     RECT  52.38 123.989 52.47 124.025 ;
     RECT  53.316 123.989 53.334 124.025 ;
     RECT  52.38 124.025 52.398 125.339 ;
     RECT  2.415 121.289 2.697 127.187 ;
     RECT  7.815 109.679 8.097 127.187 ;
     RECT  13.215 42.077 13.497 127.187 ;
     RECT  18.615 2.413 18.897 127.187 ;
     RECT  24.015 42.077 24.297 127.187 ;
     RECT  29.415 2.413 29.697 127.187 ;
     RECT  34.815 42.077 35.097 127.187 ;
     RECT  40.215 2.413 40.497 127.187 ;
     RECT  45.615 113.459 45.897 127.187 ;
     RECT  51.015 118.697 51.297 127.187 ;
     RECT  56.415 121.397 56.697 127.187 ;
     RECT  61.815 2.413 62.097 127.187 ;
     RECT  67.215 43.277 67.497 127.187 ;
     RECT  72.615 2.413 72.897 127.187 ;
     RECT  78.015 121.397 78.297 127.187 ;
     RECT  83.415 2.413 83.697 127.187 ;
     RECT  88.815 43.277 89.097 127.187 ;
     RECT  94.215 118.769 94.497 127.187 ;
     RECT  99.615 121.289 99.897 127.187 ;
     RECT  52.308 125.347 52.326 127.229 ;
     RECT  2.415 127.187 2.505 127.457 ;
     RECT  7.815 127.187 7.905 127.457 ;
     RECT  13.215 127.187 13.305 127.457 ;
     RECT  18.615 127.187 18.705 127.457 ;
     RECT  24.015 127.187 24.105 127.457 ;
     RECT  29.415 127.187 29.505 127.457 ;
     RECT  34.815 127.187 34.905 127.457 ;
     RECT  40.215 127.187 40.305 127.457 ;
     RECT  45.615 127.187 45.705 127.457 ;
     RECT  51.015 127.187 51.105 127.457 ;
     RECT  56.415 127.187 56.505 127.457 ;
     RECT  61.815 127.187 61.905 127.457 ;
     RECT  67.215 127.187 67.305 127.457 ;
     RECT  72.615 127.187 72.705 127.457 ;
     RECT  78.015 127.187 78.105 127.457 ;
     RECT  83.415 127.187 83.505 127.457 ;
     RECT  88.815 127.187 88.905 127.457 ;
     RECT  94.215 127.187 94.305 127.457 ;
     RECT  99.615 127.187 99.705 127.457 ;
     RECT  52.2 127.345 52.218 127.661 ;
    LAYER M4 ;
     RECT  0.06 7.968 0.137 121.608 ;
     RECT  0.137 7.968 2.408 119.448 ;
     RECT  0.137 120.72 2.408 120.744 ;
     RECT  2.408 2.148 2.512 127.452 ;
     RECT  2.512 2.418 2.704 127.182 ;
     RECT  2.704 58.512 2.765 58.536 ;
     RECT  2.704 84.432 2.765 84.456 ;
     RECT  2.704 26.112 2.801 26.568 ;
     RECT  2.704 36.912 2.801 37.368 ;
     RECT  2.704 43.824 2.801 43.848 ;
     RECT  2.704 61.968 2.801 62.856 ;
     RECT  2.704 66.288 2.801 66.312 ;
     RECT  2.704 117.264 2.801 117.288 ;
     RECT  2.704 8.832 2.837 8.856 ;
     RECT  2.704 15.312 2.837 15.336 ;
     RECT  2.704 17.904 2.837 17.928 ;
     RECT  2.704 24.384 2.837 24.408 ;
     RECT  2.801 37.344 2.837 37.368 ;
     RECT  2.704 39.504 2.837 39.528 ;
     RECT  2.704 45.984 2.837 46.008 ;
     RECT  2.704 49.872 2.837 49.896 ;
     RECT  2.704 69.744 2.837 69.768 ;
     RECT  2.704 76.224 2.837 76.248 ;
     RECT  2.704 82.272 2.837 82.296 ;
     RECT  2.704 86.592 2.837 86.616 ;
     RECT  2.704 97.392 2.837 97.848 ;
     RECT  2.704 31.728 2.981 31.752 ;
     RECT  2.704 103.008 2.981 103.032 ;
     RECT  2.704 22.176 3.017 22.776 ;
     RECT  2.704 71.136 3.017 71.16 ;
     RECT  2.704 29.568 3.089 29.592 ;
     RECT  2.704 56.352 3.089 56.376 ;
     RECT  2.801 61.968 3.089 61.992 ;
     RECT  2.704 51.168 3.125 51.192 ;
     RECT  2.704 77.952 3.125 78.072 ;
     RECT  2.704 100.848 3.125 100.872 ;
     RECT  3.884 9.744 3.925 9.768 ;
     RECT  3.925 9.072 3.971 9.768 ;
     RECT  2.704 47.856 4.057 47.88 ;
     RECT  2.801 26.112 4.069 26.136 ;
     RECT  4.057 47.856 4.097 48.216 ;
     RECT  4.069 26.112 4.115 27.288 ;
     RECT  4.22 32.88 4.307 32.904 ;
     RECT  4.229 34.224 4.313 34.248 ;
     RECT  4.316 45.936 4.357 45.96 ;
     RECT  4.357 45.6 4.403 45.96 ;
     RECT  4.316 53.376 4.403 53.4 ;
     RECT  4.405 18.624 4.492 18.648 ;
     RECT  4.405 49.44 4.492 49.464 ;
     RECT  4.115 26.64 4.493 27.288 ;
     RECT  4.357 44.448 4.493 44.472 ;
     RECT  4.201 110.592 4.501 110.616 ;
     RECT  2.704 112.08 4.501 112.104 ;
     RECT  4.021 13.632 4.517 13.656 ;
     RECT  4.357 54.72 4.525 54.744 ;
     RECT  4.345 87.744 4.547 87.768 ;
     RECT  4.129 11.808 4.549 11.832 ;
     RECT  4.517 13.104 4.549 13.656 ;
     RECT  4.501 110.592 4.549 112.104 ;
     RECT  4.525 54.72 4.565 55.272 ;
     RECT  3.125 78.048 4.565 78.072 ;
     RECT  4.549 109.872 4.588 112.104 ;
     RECT  4.549 11.808 4.595 13.656 ;
     RECT  4.237 51.312 4.595 51.336 ;
     RECT  4.588 109.872 4.595 111.144 ;
     RECT  4.595 11.856 4.601 13.656 ;
     RECT  4.309 79.824 4.633 79.848 ;
     RECT  4.345 117.408 4.669 117.432 ;
     RECT  3.913 41.568 4.673 41.592 ;
     RECT  3.877 62.112 4.673 62.136 ;
     RECT  4.345 108.816 4.673 108.84 ;
     RECT  4.129 96.432 4.7 96.456 ;
     RECT  4.345 98.064 4.7 98.088 ;
     RECT  4.669 117.408 4.709 117.672 ;
     RECT  4.7 96.432 4.741 98.088 ;
     RECT  3.733 115.104 4.741 115.128 ;
     RECT  4.453 29.088 4.745 29.112 ;
     RECT  4.453 103.728 4.748 103.752 ;
     RECT  4.741 96.432 4.787 98.664 ;
     RECT  4.748 103.728 4.817 103.896 ;
     RECT  4.748 89.952 4.835 89.976 ;
     RECT  4.817 103.872 4.835 103.896 ;
     RECT  4.493 26.64 4.961 26.664 ;
     RECT  4.595 111.12 4.961 111.144 ;
     RECT  4.345 17.088 5.033 17.112 ;
     RECT  4.741 76.368 5.101 76.392 ;
     RECT  4.549 50.256 5.105 50.28 ;
     RECT  4.669 59.232 5.125 59.256 ;
     RECT  4.525 70.704 5.125 70.728 ;
     RECT  4.093 67.008 5.132 67.032 ;
     RECT  4.633 25.632 5.135 25.656 ;
     RECT  4.601 11.856 5.141 12.36 ;
     RECT  5.125 58.704 5.171 59.256 ;
     RECT  5.125 69.84 5.171 70.728 ;
     RECT  4.417 84.096 5.173 84.12 ;
     RECT  4.093 37.584 5.177 37.608 ;
     RECT  4.403 45.6 5.213 45.624 ;
     RECT  5.132 67.008 5.219 67.224 ;
     RECT  4.633 79.824 5.249 80.712 ;
     RECT  4.345 56.88 5.285 56.904 ;
     RECT  4.097 48.192 5.42 48.216 ;
     RECT  5.42 19.2 5.425 19.224 ;
     RECT  3.971 9.072 5.465 9.096 ;
     RECT  4.093 85.632 5.468 85.656 ;
     RECT  5.101 86.64 5.468 87.24 ;
     RECT  5.141 11.856 5.507 11.88 ;
     RECT  5.425 19.2 5.507 19.656 ;
     RECT  5.135 25.632 5.507 25.944 ;
     RECT  5.42 48.192 5.507 48.312 ;
     RECT  4.787 98.64 5.516 98.664 ;
     RECT  4.525 23.328 5.533 23.352 ;
     RECT  5.468 85.632 5.555 87.24 ;
     RECT  4.525 68.352 5.557 68.376 ;
     RECT  5.171 69.84 5.557 70.104 ;
     RECT  4.453 74.064 5.557 74.088 ;
     RECT  4.021 91.2 5.557 91.224 ;
     RECT  4.633 93.072 5.557 93.096 ;
     RECT  4.453 60.336 5.569 60.36 ;
     RECT  5.516 98.64 5.603 99.192 ;
     RECT  5.276 108.528 5.603 108.552 ;
     RECT  5.557 74.064 5.605 74.664 ;
     RECT  5.101 76.368 5.605 77.112 ;
     RECT  4.453 105.408 5.605 105.432 ;
     RECT  3.017 22.176 5.609 22.2 ;
     RECT  5.569 60.336 5.609 60.456 ;
     RECT  4.741 114.528 5.612 115.128 ;
     RECT  5.219 67.008 5.641 67.032 ;
     RECT  5.173 84.096 5.641 84.216 ;
     RECT  5.555 85.632 5.641 85.656 ;
     RECT  5.557 68.352 5.644 70.104 ;
     RECT  5.605 74.064 5.645 77.112 ;
     RECT  5.605 104.832 5.645 105.432 ;
     RECT  5.461 41.04 5.651 41.064 ;
     RECT  5.645 75.552 5.651 77.112 ;
     RECT  5.641 46.704 5.653 46.728 ;
     RECT  5.507 48.192 5.653 48.216 ;
     RECT  5.612 114.528 5.681 116.04 ;
     RECT  5.653 46.704 5.699 48.216 ;
     RECT  4.565 55.152 5.699 55.272 ;
     RECT  4.741 62.16 5.699 62.424 ;
     RECT  5.651 76.704 5.699 77.112 ;
     RECT  5.557 91.2 5.699 91.464 ;
     RECT  5.681 116.016 5.699 116.04 ;
     RECT  4.787 96.432 5.701 96.456 ;
     RECT  5.507 19.392 5.713 19.656 ;
     RECT  5.249 80.688 5.713 80.712 ;
     RECT  5.701 95.712 5.713 96.456 ;
     RECT  5.644 69.84 5.717 70.104 ;
     RECT  5.681 114.528 5.717 114.552 ;
     RECT  5.699 46.704 5.725 47.352 ;
     RECT  5.641 66.096 5.725 67.032 ;
     RECT  5.717 70.032 5.74 70.104 ;
     RECT  5.641 84.096 5.74 85.656 ;
     RECT  5.713 95.088 5.747 96.456 ;
     RECT  5.713 80.688 5.753 81.336 ;
     RECT  5.281 10.848 5.785 10.872 ;
     RECT  5.173 33.504 5.789 33.528 ;
     RECT  5.699 62.4 5.789 62.424 ;
     RECT  4.741 100.32 5.789 100.344 ;
     RECT  4.453 101.472 5.789 101.496 ;
     RECT  4.237 30.96 5.821 30.984 ;
     RECT  4.633 64.176 5.857 64.2 ;
     RECT  5.557 92.688 5.857 93.096 ;
     RECT  5.785 10.848 5.861 11.4 ;
     RECT  5.171 58.704 5.861 58.728 ;
     RECT  5.857 64.176 5.897 64.44 ;
     RECT  5.533 23.328 6.041 24.264 ;
     RECT  5.821 30.96 6.041 31.896 ;
     RECT  5.747 95.088 6.077 95.736 ;
     RECT  4.549 39.072 6.149 39.096 ;
     RECT  5.555 87.216 6.221 87.24 ;
     RECT  2.704 88.944 6.221 88.968 ;
     RECT  4.709 117.648 6.245 117.672 ;
     RECT  5.713 19.392 6.275 20.568 ;
     RECT  6.041 24.24 6.293 24.264 ;
     RECT  5.897 64.416 6.293 64.44 ;
     RECT  6.217 83.76 6.301 83.784 ;
     RECT  6.245 117.648 6.323 118.584 ;
     RECT  6.275 19.392 6.329 19.656 ;
     RECT  6.323 118.56 6.329 118.584 ;
     RECT  5.857 92.688 6.365 93.528 ;
     RECT  5.609 60.432 6.401 60.456 ;
     RECT  5.857 91.152 6.437 91.176 ;
     RECT  4.595 109.872 6.467 109.896 ;
     RECT  6.38 111.696 6.467 111.72 ;
     RECT  4.561 35.856 6.469 35.88 ;
     RECT  5.644 68.352 6.473 68.376 ;
     RECT  6.428 33.984 6.515 34.008 ;
     RECT  5.651 75.552 6.545 75.576 ;
     RECT  6.277 116.448 6.545 116.616 ;
     RECT  6.289 106.56 6.563 106.584 ;
     RECT  5.74 84.864 6.581 85.656 ;
     RECT  5.507 25.632 6.653 25.656 ;
     RECT  6.505 16.512 6.755 16.536 ;
     RECT  6.277 18.144 6.797 18.168 ;
     RECT  6.077 95.088 6.797 95.112 ;
     RECT  5.725 47.328 6.956 47.352 ;
     RECT  5.699 55.248 6.997 55.272 ;
     RECT  5.965 54.096 7.004 54.12 ;
     RECT  6.86 12.432 7.109 12.456 ;
     RECT  5.861 11.376 7.237 11.4 ;
     RECT  5.461 42.048 7.585 42.072 ;
     RECT  4.453 43.248 7.585 43.272 ;
     RECT  7.585 42.048 7.669 43.272 ;
     RECT  7.237 11.232 7.808 11.4 ;
     RECT  7.109 12.432 7.808 13.08 ;
     RECT  7.1 14.304 7.808 14.328 ;
     RECT  6.329 19.392 7.808 19.416 ;
     RECT  5.713 27.984 7.808 28.008 ;
     RECT  6.041 31.872 7.808 31.896 ;
     RECT  6.469 35.04 7.808 36.504 ;
     RECT  7.669 42.048 7.808 43.896 ;
     RECT  7.649 45.024 7.808 45.048 ;
     RECT  6.956 47.328 7.808 48.312 ;
     RECT  6.997 49.488 7.808 49.512 ;
     RECT  7.669 50.832 7.808 50.856 ;
     RECT  7.045 52.992 7.808 53.016 ;
     RECT  7.004 54.048 7.808 54.12 ;
     RECT  6.997 55.248 7.808 56.088 ;
     RECT  6.793 57.504 7.808 57.528 ;
     RECT  6.217 62.544 7.808 62.568 ;
     RECT  5.725 67.008 7.808 67.032 ;
     RECT  5.74 70.032 7.808 70.056 ;
     RECT  7.649 71.76 7.808 71.784 ;
     RECT  7.669 72.96 7.808 72.984 ;
     RECT  5.699 77.088 7.808 77.112 ;
     RECT  5.753 81.312 7.808 81.336 ;
     RECT  6.581 85.632 7.808 85.656 ;
     RECT  6.365 92.688 7.808 92.808 ;
     RECT  5.603 98.64 7.808 98.664 ;
     RECT  5.645 104.832 7.808 104.856 ;
     RECT  6.517 107.76 7.808 107.784 ;
     RECT  6.421 112.848 7.808 112.872 ;
     RECT  6.545 116.448 7.808 116.472 ;
     RECT  7.808 2.148 7.912 127.452 ;
     RECT  7.912 2.418 8.104 127.182 ;
     RECT  8.104 43.872 8.201 43.896 ;
     RECT  8.104 56.064 8.201 56.088 ;
     RECT  8.104 72.96 8.201 72.984 ;
     RECT  8.104 115.104 8.243 115.128 ;
     RECT  8.104 116.64 8.243 116.664 ;
     RECT  8.104 35.424 8.309 35.448 ;
     RECT  8.104 49.488 8.381 49.512 ;
     RECT  8.104 11.232 8.417 11.256 ;
     RECT  8.104 42.048 13.208 42.072 ;
     RECT  8.104 92.688 13.208 92.712 ;
     RECT  13.208 2.148 13.312 127.452 ;
     RECT  13.312 2.418 13.504 127.182 ;
     RECT  13.504 42.048 18.608 42.072 ;
     RECT  13.504 92.688 18.608 92.712 ;
     RECT  18.608 2.148 18.712 127.452 ;
     RECT  18.712 2.418 18.904 127.182 ;
     RECT  18.904 42.048 24.008 42.072 ;
     RECT  18.904 92.688 24.008 92.712 ;
     RECT  24.008 2.148 24.112 127.452 ;
     RECT  24.112 2.418 24.304 127.182 ;
     RECT  24.304 42.048 29.408 42.072 ;
     RECT  24.304 92.688 29.408 92.712 ;
     RECT  29.408 2.148 29.512 127.452 ;
     RECT  29.512 2.418 29.704 127.182 ;
     RECT  29.704 42.048 34.808 42.072 ;
     RECT  29.704 92.688 34.808 92.712 ;
     RECT  34.808 2.148 34.912 127.452 ;
     RECT  34.912 2.418 35.104 127.182 ;
     RECT  35.104 42.048 40.208 42.072 ;
     RECT  35.104 92.688 40.208 92.712 ;
     RECT  40.208 2.148 40.312 127.452 ;
     RECT  40.312 2.418 40.504 127.182 ;
     RECT  40.504 42.048 42.757 42.072 ;
     RECT  42.757 41.952 42.797 42.072 ;
     RECT  42.797 41.952 45.608 41.976 ;
     RECT  40.504 92.688 45.608 92.712 ;
     RECT  45.608 2.148 45.712 127.452 ;
     RECT  45.712 2.418 45.904 127.182 ;
     RECT  45.904 41.952 46.541 42.168 ;
     RECT  45.904 92.688 50.173 92.712 ;
     RECT  46.541 42.144 50.713 42.168 ;
     RECT  50.713 42 51.008 42.168 ;
     RECT  50.173 92.4 51.008 92.712 ;
     RECT  51.008 2.148 51.112 127.452 ;
     RECT  51.112 2.418 51.304 127.452 ;
     RECT  51.304 67.152 51.517 67.272 ;
     RECT  51.304 42 51.587 43.32 ;
     RECT  51.587 42.144 51.617 43.32 ;
     RECT  51.617 43.248 51.635 43.32 ;
     RECT  51.445 129.456 51.635 129.48 ;
     RECT  51.617 42.144 51.731 42.168 ;
     RECT  52.021 127.632 52.229 127.656 ;
     RECT  51.517 67.152 53.021 67.176 ;
     RECT  53.017 123.12 54.349 123.144 ;
     RECT  54.349 122.544 54.389 123.144 ;
     RECT  54.389 122.544 54.433 122.568 ;
     RECT  51.635 43.248 56.408 43.272 ;
     RECT  51.304 92.4 56.408 92.424 ;
     RECT  54.373 121.104 56.408 121.128 ;
     RECT  56.408 2.148 56.512 127.452 ;
     RECT  56.512 2.418 56.704 127.182 ;
     RECT  56.704 43.248 61.808 43.272 ;
     RECT  56.704 92.4 61.808 92.424 ;
     RECT  56.704 121.104 61.808 121.128 ;
     RECT  61.808 2.148 61.912 127.452 ;
     RECT  61.912 2.418 62.104 127.182 ;
     RECT  62.104 43.248 67.208 43.272 ;
     RECT  62.104 92.4 67.208 92.424 ;
     RECT  62.104 121.104 67.208 121.128 ;
     RECT  67.208 2.148 67.312 127.452 ;
     RECT  67.312 2.418 67.504 127.182 ;
     RECT  67.504 43.248 72.608 43.272 ;
     RECT  67.504 92.4 72.608 92.424 ;
     RECT  67.504 121.104 72.608 121.128 ;
     RECT  72.608 2.148 72.712 127.452 ;
     RECT  72.712 2.418 72.904 127.182 ;
     RECT  72.904 121.104 75.769 121.128 ;
     RECT  72.904 43.248 78.008 43.272 ;
     RECT  72.904 92.4 78.008 92.424 ;
     RECT  75.769 121.104 78.008 121.32 ;
     RECT  78.008 2.148 78.112 127.452 ;
     RECT  78.112 2.418 78.304 127.182 ;
     RECT  78.304 43.248 83.408 43.272 ;
     RECT  78.304 92.4 83.408 92.424 ;
     RECT  78.304 121.104 83.408 121.32 ;
     RECT  83.408 2.148 83.512 127.452 ;
     RECT  83.512 2.418 83.704 127.182 ;
     RECT  83.704 43.248 88.808 43.272 ;
     RECT  83.704 92.4 88.808 92.424 ;
     RECT  83.704 121.104 88.808 121.32 ;
     RECT  88.808 2.148 88.912 127.452 ;
     RECT  88.912 2.418 89.104 127.182 ;
     RECT  94.165 9.504 94.208 9.528 ;
     RECT  89.104 43.248 94.208 43.272 ;
     RECT  89.104 92.4 94.208 92.424 ;
     RECT  94.201 106.464 94.208 106.488 ;
     RECT  89.104 121.104 94.208 121.32 ;
     RECT  94.208 2.148 94.312 127.452 ;
     RECT  94.312 2.418 94.504 127.182 ;
     RECT  94.504 54.672 94.643 54.888 ;
     RECT  94.504 38.928 94.673 39.912 ;
     RECT  94.504 51.888 94.673 52.584 ;
     RECT  94.504 105.984 94.673 106.488 ;
     RECT  94.643 54.672 94.684 54.696 ;
     RECT  94.504 16.272 95.219 16.824 ;
     RECT  94.504 96.144 95.219 96.168 ;
     RECT  94.504 14.496 95.459 15.048 ;
     RECT  94.504 43.248 95.497 43.272 ;
     RECT  94.504 99.168 95.555 99.192 ;
     RECT  94.504 98.064 95.573 98.088 ;
     RECT  94.504 113.424 95.603 113.448 ;
     RECT  94.504 87.216 95.645 87.24 ;
     RECT  95.557 111.168 95.645 112.008 ;
     RECT  95.459 14.496 95.681 14.52 ;
     RECT  95.569 21.648 95.747 21.672 ;
     RECT  95.66 69.936 95.747 69.96 ;
     RECT  94.504 9.504 95.749 9.528 ;
     RECT  95.701 68.064 95.788 68.088 ;
     RECT  95.749 9.12 95.789 9.528 ;
     RECT  95.645 111.168 95.789 111.72 ;
     RECT  95.677 118.56 95.797 118.584 ;
     RECT  95.756 115.056 95.843 115.08 ;
     RECT  94.504 116.688 95.843 116.712 ;
     RECT  95.797 118.176 95.843 118.584 ;
     RECT  95.701 20.448 95.861 20.472 ;
     RECT  94.504 61.776 95.891 61.8 ;
     RECT  94.504 92.4 95.9 92.424 ;
     RECT  95.9 92.4 95.941 92.856 ;
     RECT  94.504 91.152 95.987 91.176 ;
     RECT  95.941 92.256 95.987 92.856 ;
     RECT  94.504 109.968 96.145 109.992 ;
     RECT  96.145 109.44 96.185 109.992 ;
     RECT  95.497 71.808 96.323 71.832 ;
     RECT  94.504 78.672 96.325 78.696 ;
     RECT  95.893 104.256 96.325 104.28 ;
     RECT  95.829 63.168 96.365 63.192 ;
     RECT  96.325 78.384 96.371 78.696 ;
     RECT  96.325 104.256 96.371 104.904 ;
     RECT  95.497 42.72 96.397 43.272 ;
     RECT  95.821 44.736 96.397 44.76 ;
     RECT  96.332 80.64 96.419 80.664 ;
     RECT  96.428 28.992 96.469 29.016 ;
     RECT  94.504 30.432 96.469 30.456 ;
     RECT  96.397 42.72 96.469 44.76 ;
     RECT  94.504 46.176 96.469 46.2 ;
     RECT  94.504 47.568 96.469 47.592 ;
     RECT  96.469 28.992 96.515 30.456 ;
     RECT  96.469 42.72 96.515 47.592 ;
     RECT  96.515 45.264 96.545 47.592 ;
     RECT  96.515 29.712 96.573 30.456 ;
     RECT  95.929 33.648 96.577 33.672 ;
     RECT  96.577 33.648 96.617 34.152 ;
     RECT  96.371 104.88 96.725 104.904 ;
     RECT  96.217 18.384 96.805 18.408 ;
     RECT  96.649 19.392 96.805 19.416 ;
     RECT  96.805 18.384 96.851 19.416 ;
     RECT  96.851 18.384 96.853 18.84 ;
     RECT  95.987 92.256 96.869 92.424 ;
     RECT  95.219 16.272 96.899 16.296 ;
     RECT  96.757 40.512 96.901 40.536 ;
     RECT  96.515 42.72 96.901 43.32 ;
     RECT  96.037 56.64 96.901 56.664 ;
     RECT  95.497 58.128 96.901 58.152 ;
     RECT  96.757 99.6 96.901 99.624 ;
     RECT  94.504 11.904 96.905 11.928 ;
     RECT  95.713 13.008 96.905 13.032 ;
     RECT  96.901 35.232 96.908 35.256 ;
     RECT  95.468 37.584 96.941 37.608 ;
     RECT  94.504 82.08 96.941 82.104 ;
     RECT  96.869 92.256 96.941 92.376 ;
     RECT  96.617 34.128 96.947 34.152 ;
     RECT  96.901 40.032 96.947 40.536 ;
     RECT  96.901 56.112 96.947 58.152 ;
     RECT  95.797 22.752 96.977 22.776 ;
     RECT  94.504 66.72 97.004 66.744 ;
     RECT  95.713 75.84 97.004 75.864 ;
     RECT  96.145 88.608 97.004 88.632 ;
     RECT  95.605 26.688 97.045 26.712 ;
     RECT  97.004 51.264 97.045 51.288 ;
     RECT  96.947 57.552 97.045 58.152 ;
     RECT  97.004 75.84 97.045 76.104 ;
     RECT  96.185 109.44 97.045 109.464 ;
     RECT  96.853 17.616 97.049 18.84 ;
     RECT  96.901 41.904 97.049 43.32 ;
     RECT  97.045 108.72 97.085 109.464 ;
     RECT  97.004 66.72 97.091 67.224 ;
     RECT  97.004 87.696 97.091 88.632 ;
     RECT  96.901 99.6 97.093 100.152 ;
     RECT  96.613 101.424 97.093 101.448 ;
     RECT  95.713 102.624 97.093 102.648 ;
     RECT  97.093 99.6 97.139 100.296 ;
     RECT  97.093 101.424 97.139 102.648 ;
     RECT  96.325 113.328 97.148 113.352 ;
     RECT  97.091 88.32 97.157 88.632 ;
     RECT  97.139 102.24 97.18 102.264 ;
     RECT  97.045 26.688 97.187 26.76 ;
     RECT  94.504 120.864 97.187 121.32 ;
     RECT  96.908 35.232 97.189 35.352 ;
     RECT  97.148 112.848 97.235 113.352 ;
     RECT  96.325 49.68 97.237 49.704 ;
     RECT  97.045 75.84 97.237 76.2 ;
     RECT  97.045 83.76 97.261 83.784 ;
     RECT  94.673 38.928 97.265 38.952 ;
     RECT  95.789 111.696 97.265 111.72 ;
     RECT  96.545 46.752 97.283 47.592 ;
     RECT  97.237 48.912 97.283 49.704 ;
     RECT  97.237 75.84 97.283 76.344 ;
     RECT  96.947 56.112 97.297 56.136 ;
     RECT  97.283 46.752 97.301 46.968 ;
     RECT  97.225 74.304 97.309 74.664 ;
     RECT  97.283 48.912 97.324 48.936 ;
     RECT  97.261 83.76 97.331 84.312 ;
     RECT  97.187 26.688 97.333 26.712 ;
     RECT  96.239 64.848 97.333 64.872 ;
     RECT  97.049 42.72 97.337 43.32 ;
     RECT  97.297 55.824 97.337 56.136 ;
     RECT  95.789 9.12 97.369 9.144 ;
     RECT  97.333 26.256 97.373 26.712 ;
     RECT  97.333 64.752 97.373 64.872 ;
     RECT  97.34 11.856 97.427 11.88 ;
     RECT  97.049 18.72 97.427 18.84 ;
     RECT  97.139 100.128 97.427 100.296 ;
     RECT  97.085 108.72 97.427 108.84 ;
     RECT  97.189 35.232 97.429 35.976 ;
     RECT  97.045 50.976 97.475 51.288 ;
     RECT  94.673 52.56 97.477 52.584 ;
     RECT  97.429 35.232 97.481 36.456 ;
     RECT  97.481 35.328 97.516 36.456 ;
     RECT  97.337 43.152 97.516 43.32 ;
     RECT  96.217 68.4 97.517 68.424 ;
     RECT  96.371 78.384 97.517 78.408 ;
     RECT  97.477 52.32 97.523 52.584 ;
     RECT  97.297 54 97.523 54.024 ;
     RECT  94.504 85.68 97.621 85.704 ;
     RECT  97.523 52.32 97.625 52.344 ;
     RECT  97.045 57.552 97.697 58.728 ;
     RECT  97.475 50.976 97.765 51 ;
     RECT  97.765 50.832 97.805 51 ;
     RECT  96.941 92.304 97.981 92.376 ;
     RECT  94.504 94.56 97.985 94.584 ;
     RECT  97.697 58.656 98.005 58.728 ;
     RECT  97.369 9.024 98.012 9.144 ;
     RECT  97.141 116.256 98.012 116.28 ;
     RECT  97.405 96.096 98.015 96.12 ;
     RECT  96.325 97.248 98.015 97.272 ;
     RECT  97.621 85.68 98.051 86.664 ;
     RECT  98.012 9.024 98.053 10.008 ;
     RECT  97.873 21.648 98.053 21.672 ;
     RECT  95.756 24.864 98.053 24.888 ;
     RECT  97.373 26.256 98.053 26.28 ;
     RECT  97.091 66.72 98.053 66.744 ;
     RECT  97.427 100.272 98.053 100.296 ;
     RECT  96.973 114.528 98.053 114.552 ;
     RECT  98.012 116.256 98.053 116.712 ;
     RECT  95.843 118.176 98.053 118.2 ;
     RECT  97.049 17.616 98.089 17.64 ;
     RECT  96.573 29.712 98.093 29.736 ;
     RECT  97.516 43.296 98.093 43.32 ;
     RECT  97.981 92.304 98.093 93.48 ;
     RECT  98.015 96.096 98.093 97.272 ;
     RECT  98.053 114.048 98.093 114.552 ;
     RECT  98.053 8.928 98.099 10.824 ;
     RECT  98.053 21.648 98.099 22.488 ;
     RECT  98.053 24.48 98.099 24.888 ;
     RECT  98.093 96.096 98.099 96.888 ;
     RECT  98.053 116.256 98.099 119.16 ;
     RECT  97.081 81.744 98.125 81.768 ;
     RECT  98.099 10.8 98.137 10.824 ;
     RECT  98.099 119.136 98.137 119.16 ;
     RECT  98.099 22.464 98.14 22.488 ;
     RECT  98.06 80.64 98.147 80.664 ;
     RECT  98.125 81.744 98.165 81.864 ;
     RECT  97.337 55.824 98.197 55.848 ;
     RECT  98.197 55.296 98.237 55.848 ;
     RECT  98.156 99.024 98.243 99.048 ;
     RECT  96.829 63.264 98.273 63.288 ;
     RECT  98.099 117.648 98.273 117.672 ;
     RECT  98.204 53.568 98.291 53.592 ;
     RECT  98.237 55.296 98.291 55.32 ;
     RECT  98.005 58.656 98.345 59.256 ;
     RECT  96.277 72.912 98.345 72.936 ;
     RECT  98.051 85.92 98.345 86.472 ;
     RECT  98.348 107.712 98.377 107.736 ;
     RECT  98.099 24.48 98.381 24.504 ;
     RECT  96.217 70.416 98.381 70.44 ;
     RECT  97.331 84.288 98.381 84.312 ;
     RECT  97.945 104.208 98.389 104.232 ;
     RECT  94.673 105.984 98.389 106.008 ;
     RECT  97.301 46.944 98.417 46.968 ;
     RECT  98.389 103.68 98.435 104.232 ;
     RECT  98.389 105.216 98.435 106.008 ;
     RECT  98.377 107.52 98.435 107.736 ;
     RECT  98.053 25.968 98.453 26.28 ;
     RECT  96.545 45.264 98.453 45.288 ;
     RECT  97.373 64.752 98.485 64.776 ;
     RECT  97.657 11.808 98.513 11.832 ;
     RECT  98.444 62.352 98.531 62.376 ;
     RECT  97.187 120.864 98.561 120.888 ;
     RECT  98.449 13.584 98.579 13.608 ;
     RECT  98.513 11.808 98.597 12.36 ;
     RECT  98.093 92.304 98.627 92.328 ;
     RECT  98.485 63.84 98.629 64.776 ;
     RECT  98.089 17.616 98.633 18.264 ;
     RECT  97.805 50.832 98.633 50.856 ;
     RECT  98.053 66.72 98.633 67.272 ;
     RECT  96.145 31.776 98.677 31.8 ;
     RECT  98.557 70.512 98.725 70.536 ;
     RECT  98.093 114.048 98.809 114.072 ;
     RECT  97.045 28.272 98.869 28.296 ;
     RECT  96.947 40.032 98.876 40.056 ;
     RECT  98.099 8.928 99.608 8.952 ;
     RECT  98.453 26.256 99.608 26.28 ;
     RECT  98.869 27.744 99.608 28.296 ;
     RECT  98.677 31.008 99.608 31.8 ;
     RECT  97.516 35.952 99.608 36.456 ;
     RECT  98.557 38.256 99.608 38.28 ;
     RECT  98.876 39.888 99.608 40.056 ;
     RECT  98.917 41.04 99.608 41.064 ;
     RECT  97.697 57.552 99.608 57.576 ;
     RECT  98.345 58.656 99.608 58.68 ;
     RECT  96.757 60.384 99.608 60.408 ;
     RECT  98.629 63.84 99.608 65.688 ;
     RECT  98.633 67.248 99.608 67.272 ;
     RECT  97.513 69.408 99.608 69.432 ;
     RECT  98.725 70.512 99.608 70.824 ;
     RECT  97.309 74.304 99.608 74.328 ;
     RECT  97.283 76.32 99.608 76.344 ;
     RECT  98.725 77.952 99.608 77.976 ;
     RECT  98.593 79.44 99.608 79.464 ;
     RECT  98.165 81.84 99.608 81.864 ;
     RECT  98.053 82.944 99.608 82.968 ;
     RECT  98.345 85.92 99.608 85.944 ;
     RECT  97.157 88.32 99.608 88.344 ;
     RECT  96.757 90 99.608 90.024 ;
     RECT  98.581 91.2 99.608 91.224 ;
     RECT  98.093 93.456 99.608 93.48 ;
     RECT  98.099 96.864 99.608 96.888 ;
     RECT  98.053 100.272 99.608 100.92 ;
     RECT  98.435 103.68 99.608 103.704 ;
     RECT  98.435 105.216 99.608 105.24 ;
     RECT  98.435 107.52 99.608 107.544 ;
     RECT  97.427 108.72 99.608 108.744 ;
     RECT  98.197 111.12 99.608 111.144 ;
     RECT  99.013 112.368 99.608 112.392 ;
     RECT  98.809 113.952 99.608 114.072 ;
     RECT  98.305 115.728 99.608 115.752 ;
     RECT  99.608 2.148 99.712 127.452 ;
     RECT  99.712 2.418 99.904 127.182 ;
     RECT  99.904 27.888 100.211 27.912 ;
     RECT  99.904 29.088 100.541 29.112 ;
     RECT  101.581 51.36 102.013 51.384 ;
     RECT  101.977 111.408 102.013 111.432 ;
     RECT  101.581 112.704 102.013 112.728 ;
     RECT  101.509 117.024 102.013 117.048 ;
     RECT  102.013 26.736 102.517 26.76 ;
     RECT  101.689 41.856 102.517 41.88 ;
     RECT  102.013 62.592 102.517 62.616 ;
     RECT  102.013 71.664 102.517 71.688 ;
     RECT  102.013 82.464 102.517 82.488 ;
     RECT  101.977 97.584 102.517 97.608 ;
     RECT  102.013 105.792 102.517 106.248 ;
     RECT  101.977 17.664 102.553 17.688 ;
     RECT  102.013 19.824 102.553 19.848 ;
     RECT  101.977 21.552 102.553 21.576 ;
     RECT  102.517 23.712 102.553 23.736 ;
     RECT  102.517 25.872 102.553 26.76 ;
     RECT  101.977 28.032 102.553 28.056 ;
     RECT  102.013 30.192 102.553 30.216 ;
     RECT  102.517 34.512 102.553 34.536 ;
     RECT  102.517 36.24 102.553 36.264 ;
     RECT  101.617 38.832 102.553 38.856 ;
     RECT  102.517 40.992 102.553 41.88 ;
     RECT  102.517 43.152 102.553 43.176 ;
     RECT  102.517 44.88 102.553 44.904 ;
     RECT  101.689 47.904 102.553 47.928 ;
     RECT  102.013 50.496 102.553 51.384 ;
     RECT  101.473 54.384 102.553 54.408 ;
     RECT  102.481 57.84 102.553 57.864 ;
     RECT  102.517 62.16 102.553 62.616 ;
     RECT  102.517 66.912 102.553 66.936 ;
     RECT  102.517 71.232 102.553 71.688 ;
     RECT  102.013 75.12 102.553 75.144 ;
     RECT  102.013 77.712 102.553 78.6 ;
     RECT  102.517 82.032 102.553 82.488 ;
     RECT  102.517 83.76 102.553 83.784 ;
     RECT  102.517 86.352 102.553 86.376 ;
     RECT  102.517 88.512 102.553 88.536 ;
     RECT  102.013 91.104 102.553 91.128 ;
     RECT  102.517 92.832 102.553 92.856 ;
     RECT  102.013 94.992 102.553 95.016 ;
     RECT  102.517 97.152 102.553 97.608 ;
     RECT  102.013 99.312 102.553 99.336 ;
     RECT  102.013 103.632 102.553 103.656 ;
     RECT  102.517 105.36 102.553 106.248 ;
     RECT  102.517 107.952 102.553 107.976 ;
     RECT  102.013 111.408 102.553 112.728 ;
     RECT  102.013 114.432 102.553 114.456 ;
     RECT  102.013 116.592 102.553 117.048 ;
     RECT  102.517 118.752 102.553 118.776 ;
     RECT  102.517 120.48 102.553 120.504 ;
     RECT  102.553 9.024 102.589 120.936 ;
     RECT  102.589 8.592 103.644 120.936 ;
    LAYER M5 ;
     RECT  2.4 2.137 2.52 2.151 ;
     RECT  7.8 2.137 7.92 2.151 ;
     RECT  13.2 2.137 13.32 2.151 ;
     RECT  18.6 2.137 18.72 2.151 ;
     RECT  24 2.137 24.12 2.151 ;
     RECT  29.4 2.137 29.52 2.151 ;
     RECT  34.8 2.137 34.92 2.151 ;
     RECT  40.2 2.137 40.32 2.151 ;
     RECT  45.6 2.137 45.72 2.151 ;
     RECT  51 2.137 51.12 2.151 ;
     RECT  56.4 2.137 56.52 2.151 ;
     RECT  61.8 2.137 61.92 2.151 ;
     RECT  67.2 2.137 67.32 2.151 ;
     RECT  72.6 2.137 72.72 2.151 ;
     RECT  78 2.137 78.12 2.151 ;
     RECT  83.4 2.137 83.52 2.151 ;
     RECT  88.8 2.137 88.92 2.151 ;
     RECT  94.2 2.137 94.32 2.151 ;
     RECT  99.6 2.137 99.72 2.151 ;
     RECT  3.936 9.061 3.96 9.779 ;
     RECT  7.8 2.151 8.112 11.221 ;
     RECT  7.248 11.221 8.112 11.365 ;
     RECT  98.064 8.917 98.088 11.843 ;
     RECT  4.56 11.797 4.584 11.845 ;
     RECT  6.912 11.365 8.112 12.467 ;
     RECT  4.56 11.845 5.496 13.139 ;
     RECT  98.544 12.325 98.568 13.619 ;
     RECT  7.152 12.467 8.112 14.339 ;
     RECT  94.2 2.151 94.512 14.485 ;
     RECT  94.2 14.485 95.448 15.059 ;
     RECT  97.392 11.845 97.416 16.261 ;
     RECT  94.2 15.059 95.208 16.835 ;
     RECT  5.472 13.139 5.496 18.133 ;
     RECT  6.72 16.501 6.744 18.133 ;
     RECT  5.472 18.133 6.744 18.179 ;
     RECT  4.416 17.077 4.44 18.659 ;
     RECT  96.864 16.261 97.416 18.709 ;
     RECT  96.816 18.709 97.416 18.851 ;
     RECT  5.472 18.179 6.312 19.427 ;
     RECT  96.816 18.851 97.08 19.427 ;
     RECT  5.472 19.427 6.264 20.579 ;
     RECT  95.712 20.437 95.736 21.683 ;
     RECT  98.064 21.637 98.088 22.499 ;
     RECT  5.472 20.579 5.496 23.317 ;
     RECT  5.472 23.317 5.688 24.275 ;
     RECT  95.808 22.741 95.832 24.899 ;
     RECT  5.472 24.275 5.496 25.909 ;
     RECT  5.184 25.909 5.496 25.955 ;
     RECT  98.064 24.469 98.088 26.245 ;
     RECT  99.6 2.151 99.912 26.245 ;
     RECT  98.064 26.245 99.912 26.291 ;
     RECT  97.056 19.427 97.08 26.725 ;
     RECT  97.056 26.725 97.176 26.771 ;
     RECT  4.08 26.101 4.104 27.299 ;
     RECT  98.88 26.291 99.912 27.779 ;
     RECT  99.168 27.779 99.912 27.877 ;
     RECT  99.168 27.877 100.2 28.307 ;
     RECT  97.152 26.771 97.176 28.981 ;
     RECT  99.6 28.307 100.2 29.123 ;
     RECT  96.48 28.981 97.176 30.467 ;
     RECT  99.6 29.123 99.912 30.997 ;
     RECT  98.688 30.997 99.912 31.811 ;
     RECT  5.184 25.955 5.208 32.869 ;
     RECT  4.272 32.869 5.208 33.493 ;
     RECT  4.272 33.493 5.64 33.539 ;
     RECT  5.616 33.539 5.64 33.973 ;
     RECT  97.152 30.467 97.176 34.117 ;
     RECT  4.272 33.539 4.296 34.259 ;
     RECT  5.616 33.973 6.504 35.029 ;
     RECT  7.8 14.339 8.112 35.029 ;
     RECT  5.616 35.029 8.112 35.075 ;
     RECT  96.912 34.117 97.176 35.267 ;
     RECT  96.96 35.267 97.176 35.317 ;
     RECT  96.96 35.317 97.464 36.467 ;
     RECT  6.816 35.075 8.112 36.515 ;
     RECT  99.6 31.811 99.912 38.245 ;
     RECT  95.52 37.573 95.544 38.963 ;
     RECT  4.56 37.573 4.584 39.107 ;
     RECT  96.96 36.467 96.984 40.021 ;
     RECT  5.616 35.075 5.64 41.029 ;
     RECT  5.472 41.029 5.64 41.075 ;
     RECT  98.928 38.245 99.912 41.075 ;
     RECT  96.912 40.021 96.984 41.939 ;
     RECT  51 2.151 51.312 41.989 ;
     RECT  51 41.989 51.576 42.133 ;
     RECT  7.8 36.515 8.112 42.325 ;
     RECT  96.96 41.939 96.984 43.141 ;
     RECT  51 42.133 51.72 43.283 ;
     RECT  96.96 43.141 97.464 43.285 ;
     RECT  7.68 42.325 8.112 45.059 ;
     RECT  4.368 44.437 4.392 45.971 ;
     RECT  5.472 41.075 5.496 46.693 ;
     RECT  96.48 43.285 97.464 46.787 ;
     RECT  5.472 46.693 5.688 48.227 ;
     RECT  7.8 45.059 8.112 48.277 ;
     RECT  4.416 48.181 4.44 49.475 ;
     RECT  7.008 48.277 8.112 49.523 ;
     RECT  97.248 46.787 97.464 49.715 ;
     RECT  5.472 48.227 5.496 50.245 ;
     RECT  7.68 49.523 8.112 50.867 ;
     RECT  97.44 49.715 97.464 50.965 ;
     RECT  97.44 50.965 97.512 51.253 ;
     RECT  4.56 50.245 5.496 51.347 ;
     RECT  7.8 50.867 8.112 52.981 ;
     RECT  97.056 51.253 97.512 53.557 ;
     RECT  97.056 53.557 98.28 54.035 ;
     RECT  7.056 52.981 8.112 54.083 ;
     RECT  94.2 16.835 94.512 54.661 ;
     RECT  4.368 53.365 4.392 54.755 ;
     RECT  94.2 54.661 94.632 54.899 ;
     RECT  5.472 51.347 5.496 55.141 ;
     RECT  5.472 55.141 5.688 55.187 ;
     RECT  7.8 54.083 8.112 55.237 ;
     RECT  98.256 54.035 98.28 55.331 ;
     RECT  97.056 54.035 97.08 56.101 ;
     RECT  7.008 55.237 8.112 57.539 ;
     RECT  96.912 56.101 97.08 57.587 ;
     RECT  5.664 55.187 5.688 58.693 ;
     RECT  97.056 57.587 97.08 58.739 ;
     RECT  5.136 58.693 5.688 60.371 ;
     RECT  98.016 59.221 98.04 60.373 ;
     RECT  98.016 60.373 98.52 60.419 ;
     RECT  5.664 60.371 5.688 62.195 ;
     RECT  95.856 61.765 95.88 63.157 ;
     RECT  95.856 63.157 96.312 63.203 ;
     RECT  98.496 60.419 98.52 63.875 ;
     RECT  99.6 41.075 99.912 64.741 ;
     RECT  96.288 63.203 96.312 64.883 ;
     RECT  98.832 64.741 99.912 65.699 ;
     RECT  5.664 66.085 5.688 67.043 ;
     RECT  51 43.283 51.624 67.141 ;
     RECT  99.6 65.699 99.912 67.237 ;
     RECT  5.184 67.189 5.208 68.341 ;
     RECT  5.184 68.341 5.592 68.387 ;
     RECT  5.568 68.387 5.592 69.829 ;
     RECT  95.712 66.709 95.736 69.971 ;
     RECT  7.8 57.539 8.112 70.021 ;
     RECT  5.136 69.829 5.592 70.069 ;
     RECT  5.136 70.069 5.688 70.739 ;
     RECT  98.736 67.237 99.912 70.835 ;
     RECT  97.056 67.189 97.08 71.797 ;
     RECT  96.288 71.797 97.08 72.947 ;
     RECT  7.68 70.021 8.112 72.995 ;
     RECT  5.664 70.739 5.688 74.629 ;
     RECT  97.056 72.947 97.08 74.629 ;
     RECT  97.056 74.629 97.272 76.355 ;
     RECT  5.568 74.629 5.688 76.693 ;
     RECT  5.184 76.693 5.688 76.739 ;
     RECT  5.184 76.739 5.592 77.123 ;
     RECT  99.6 70.835 99.912 77.941 ;
     RECT  97.056 76.355 97.08 78.373 ;
     RECT  96.336 78.373 97.08 78.707 ;
     RECT  98.736 77.941 99.912 79.475 ;
     RECT  97.056 78.707 97.08 80.629 ;
     RECT  98.112 80.629 98.136 81.779 ;
     RECT  96.384 80.629 97.08 82.115 ;
     RECT  98.592 81.829 98.616 82.979 ;
     RECT  97.056 82.115 97.08 83.749 ;
     RECT  6.24 81.301 6.264 83.795 ;
     RECT  97.056 83.749 97.32 83.795 ;
     RECT  5.184 77.123 5.208 84.181 ;
     RECT  5.184 84.181 5.688 84.227 ;
     RECT  5.664 84.227 5.688 84.853 ;
     RECT  5.664 84.853 6.264 85.621 ;
     RECT  5.136 85.621 6.264 85.667 ;
     RECT  94.2 54.899 94.512 85.669 ;
     RECT  97.296 83.795 97.32 85.669 ;
     RECT  5.136 85.667 5.688 86.675 ;
     RECT  97.296 85.669 98.04 86.675 ;
     RECT  5.52 86.675 5.688 87.251 ;
     RECT  94.2 85.669 95.208 87.251 ;
     RECT  97.296 86.675 97.32 87.685 ;
     RECT  97.056 87.685 97.32 88.355 ;
     RECT  4.512 87.733 4.536 88.933 ;
     RECT  5.664 87.251 5.688 88.933 ;
     RECT  4.512 88.933 5.688 88.979 ;
     RECT  4.8 88.979 5.688 89.987 ;
     RECT  5.664 89.987 5.688 91.429 ;
     RECT  5.568 91.429 5.688 91.475 ;
     RECT  98.592 88.309 98.616 92.339 ;
     RECT  95.952 91.141 95.976 92.341 ;
     RECT  97.296 88.355 97.32 92.341 ;
     RECT  95.952 92.341 97.32 92.387 ;
     RECT  51 67.141 51.864 92.435 ;
     RECT  94.2 87.251 94.512 94.549 ;
     RECT  95.952 92.387 96.936 94.549 ;
     RECT  94.2 94.549 96.936 94.595 ;
     RECT  5.568 91.475 5.592 95.701 ;
     RECT  5.568 95.701 5.736 96.421 ;
     RECT  4.752 96.421 5.736 96.467 ;
     RECT  98.064 96.085 98.088 96.899 ;
     RECT  94.2 94.595 95.208 98.053 ;
     RECT  4.752 96.467 5.592 98.099 ;
     RECT  94.2 98.053 95.544 98.099 ;
     RECT  95.52 98.099 95.544 99.203 ;
     RECT  96.912 94.595 96.936 99.589 ;
     RECT  96.912 99.589 97.128 100.117 ;
     RECT  98.208 99.013 98.232 100.117 ;
     RECT  96.912 100.117 98.232 100.163 ;
     RECT  97.104 100.163 98.232 100.307 ;
     RECT  97.104 100.307 97.416 102.659 ;
     RECT  5.568 98.099 5.592 103.861 ;
     RECT  96.336 104.245 96.36 104.915 ;
     RECT  4.8 103.861 5.592 105.443 ;
     RECT  5.568 105.443 5.592 106.549 ;
     RECT  5.568 106.549 6.552 107.795 ;
     RECT  5.568 107.795 5.592 108.517 ;
     RECT  5.328 108.517 5.592 108.563 ;
     RECT  98.4 103.669 98.424 108.755 ;
     RECT  97.392 102.659 97.416 108.805 ;
     RECT  97.248 108.805 97.416 108.851 ;
     RECT  5.328 108.563 5.352 109.861 ;
     RECT  4.56 109.861 5.352 111.109 ;
     RECT  99.6 79.475 99.912 111.109 ;
     RECT  4.512 111.109 5.352 112.115 ;
     RECT  97.248 108.851 97.272 112.837 ;
     RECT  6.432 109.861 6.456 112.883 ;
     RECT  95.568 111.157 95.592 113.459 ;
     RECT  99.024 111.109 99.912 114.037 ;
     RECT  97.2 112.837 97.272 114.563 ;
     RECT  5.328 112.115 5.352 114.611 ;
     RECT  7.8 72.995 8.112 115.093 ;
     RECT  98.64 114.037 99.912 115.763 ;
     RECT  97.248 114.563 97.272 116.245 ;
     RECT  5.664 116.005 5.688 116.581 ;
     RECT  7.8 115.093 8.232 116.675 ;
     RECT  97.152 116.245 97.272 116.677 ;
     RECT  5.664 116.581 6.312 117.683 ;
     RECT  6.288 117.683 6.312 118.595 ;
     RECT  95.808 115.045 95.832 118.595 ;
     RECT  97.152 116.677 98.088 119.171 ;
     RECT  94.2 98.099 94.512 120.853 ;
     RECT  94.2 120.853 95.208 121.139 ;
     RECT  97.152 119.171 97.176 121.331 ;
     RECT  54.384 121.093 54.408 122.579 ;
     RECT  2.4 2.151 2.712 127.449 ;
     RECT  7.8 116.675 8.112 127.449 ;
     RECT  13.2 2.151 13.512 127.449 ;
     RECT  18.6 2.151 18.912 127.449 ;
     RECT  24 2.151 24.312 127.449 ;
     RECT  29.4 2.151 29.712 127.449 ;
     RECT  34.8 2.151 35.112 127.449 ;
     RECT  40.2 2.151 40.512 127.449 ;
     RECT  45.6 2.151 45.912 127.449 ;
     RECT  56.4 2.151 56.712 127.449 ;
     RECT  61.8 2.151 62.112 127.449 ;
     RECT  67.2 2.151 67.512 127.449 ;
     RECT  72.6 2.151 72.912 127.449 ;
     RECT  78 2.151 78.312 127.449 ;
     RECT  83.4 2.151 83.712 127.449 ;
     RECT  88.8 2.151 89.112 127.449 ;
     RECT  94.2 121.139 94.512 127.449 ;
     RECT  99.6 115.763 99.912 127.449 ;
     RECT  2.4 127.449 2.52 127.463 ;
     RECT  7.8 127.449 7.92 127.463 ;
     RECT  13.2 127.449 13.32 127.463 ;
     RECT  18.6 127.449 18.72 127.463 ;
     RECT  24 127.449 24.12 127.463 ;
     RECT  29.4 127.449 29.52 127.463 ;
     RECT  34.8 127.449 34.92 127.463 ;
     RECT  40.2 127.449 40.32 127.463 ;
     RECT  45.6 127.449 45.72 127.463 ;
     RECT  51 92.435 51.48 127.463 ;
     RECT  56.4 127.449 56.52 127.463 ;
     RECT  61.8 127.449 61.92 127.463 ;
     RECT  67.2 127.449 67.32 127.463 ;
     RECT  72.6 127.449 72.72 127.463 ;
     RECT  78 127.449 78.12 127.463 ;
     RECT  83.4 127.449 83.52 127.463 ;
     RECT  88.8 127.449 88.92 127.463 ;
     RECT  94.2 127.449 94.32 127.463 ;
     RECT  99.6 127.449 99.72 127.463 ;
     RECT  51.456 127.463 51.48 127.621 ;
     RECT  51.456 127.621 52.056 129.491 ;
     RECT  51.6 129.491 52.056 129.552 ;
     RECT  98.088 8.917 99.6 11.843 ;
     RECT  2.712 9.061 3.936 9.779 ;
     RECT  98.064 11.843 99.6 11.845 ;
     RECT  5.496 11.845 6.912 12.467 ;
     RECT  97.416 11.845 99.6 12.325 ;
     RECT  97.416 12.325 98.544 13.619 ;
     RECT  98.568 12.325 99.6 13.619 ;
     RECT  5.496 16.501 6.72 18.133 ;
     RECT  6.744 16.501 7.8 18.179 ;
     RECT  4.44 17.077 5.472 18.659 ;
     RECT  6.312 18.179 7.8 19.427 ;
     RECT  96.816 19.427 97.056 20.437 ;
     RECT  94.512 20.437 95.712 21.683 ;
     RECT  95.736 20.437 97.056 21.683 ;
     RECT  97.08 21.637 98.064 22.499 ;
     RECT  98.088 21.637 99.6 22.499 ;
     RECT  94.512 21.683 97.056 22.741 ;
     RECT  94.512 22.741 95.808 24.899 ;
     RECT  95.832 22.741 97.056 24.899 ;
     RECT  97.08 24.469 98.064 26.291 ;
     RECT  98.088 24.469 99.6 26.245 ;
     RECT  2.712 26.101 4.08 27.299 ;
     RECT  4.104 26.101 5.184 27.299 ;
     RECT  97.08 26.291 97.176 26.725 ;
     RECT  97.176 30.997 98.688 31.811 ;
     RECT  4.296 33.539 5.616 34.259 ;
     RECT  6.504 33.973 7.8 35.029 ;
     RECT  5.64 35.075 6.816 36.515 ;
     RECT  4.584 37.573 5.616 39.107 ;
     RECT  94.512 37.573 95.52 38.963 ;
     RECT  95.544 37.573 96.96 38.963 ;
     RECT  96.912 38.963 96.96 40.021 ;
     RECT  96.912 41.939 96.96 43.285 ;
     RECT  4.392 44.437 5.472 45.971 ;
     RECT  4.44 48.181 5.472 49.475 ;
     RECT  5.496 48.227 5.688 48.277 ;
     RECT  5.496 48.277 7.008 49.523 ;
     RECT  4.56 49.475 5.472 50.245 ;
     RECT  4.392 53.365 5.472 54.755 ;
     RECT  98.28 53.557 99.6 55.331 ;
     RECT  97.08 54.035 98.256 55.331 ;
     RECT  7.056 54.083 7.8 55.141 ;
     RECT  5.688 55.141 7.8 55.237 ;
     RECT  5.688 55.237 7.008 57.539 ;
     RECT  98.52 60.373 99.6 63.875 ;
     RECT  94.512 61.765 95.856 63.203 ;
     RECT  98.832 63.875 99.6 64.741 ;
     RECT  94.512 66.709 95.712 69.971 ;
     RECT  95.736 67.189 97.056 69.971 ;
     RECT  5.184 68.387 5.568 69.829 ;
     RECT  98.736 79.475 99.6 80.629 ;
     RECT  97.08 80.629 98.112 81.779 ;
     RECT  98.136 80.629 99.6 81.779 ;
     RECT  5.208 81.301 6.24 83.795 ;
     RECT  97.08 81.779 99.6 81.829 ;
     RECT  97.08 81.829 98.592 82.979 ;
     RECT  98.616 81.829 99.6 82.979 ;
     RECT  97.08 82.979 97.32 83.749 ;
     RECT  5.208 83.795 6.264 84.181 ;
     RECT  5.688 84.181 6.264 84.853 ;
     RECT  5.184 84.227 5.664 85.621 ;
     RECT  5.136 86.675 5.52 87.251 ;
     RECT  5.136 87.251 5.664 87.733 ;
     RECT  4.536 87.733 5.664 88.933 ;
     RECT  97.32 88.309 98.592 92.339 ;
     RECT  98.616 88.309 99.6 92.339 ;
     RECT  5.568 89.987 5.664 91.429 ;
     RECT  94.512 91.141 95.952 94.549 ;
     RECT  95.976 91.141 97.296 92.341 ;
     RECT  96.936 96.085 98.064 96.899 ;
     RECT  98.088 96.085 99.6 96.899 ;
     RECT  95.544 98.053 96.912 99.203 ;
     RECT  94.512 98.099 95.52 99.203 ;
     RECT  96.936 99.013 98.208 99.589 ;
     RECT  98.232 99.013 99.6 100.307 ;
     RECT  97.128 99.589 98.208 100.117 ;
     RECT  97.416 103.669 98.4 108.755 ;
     RECT  98.424 103.669 99.6 108.755 ;
     RECT  96.36 104.245 97.392 104.915 ;
     RECT  6.552 106.549 7.8 107.795 ;
     RECT  5.352 108.563 5.592 109.861 ;
     RECT  5.352 109.861 6.432 112.883 ;
     RECT  6.456 109.861 7.8 112.883 ;
     RECT  94.512 111.157 95.568 113.459 ;
     RECT  97.272 114.037 98.64 115.763 ;
     RECT  97.2 114.563 97.248 115.045 ;
     RECT  94.512 115.045 95.808 118.595 ;
     RECT  95.832 115.045 97.248 116.245 ;
     RECT  97.272 115.763 99.6 116.677 ;
     RECT  95.832 116.245 97.152 118.595 ;
     RECT  6.312 116.581 7.8 118.595 ;
     RECT  98.088 116.677 99.6 119.171 ;
  END
END dsfd_vm_static_read_q6
END LIBRARY
